VERSION 5.7 ;
  NOWIREEXTENSIONATPIN ON ;
  DIVIDERCHAR "/" ;
  BUSBITCHARS "[]" ;
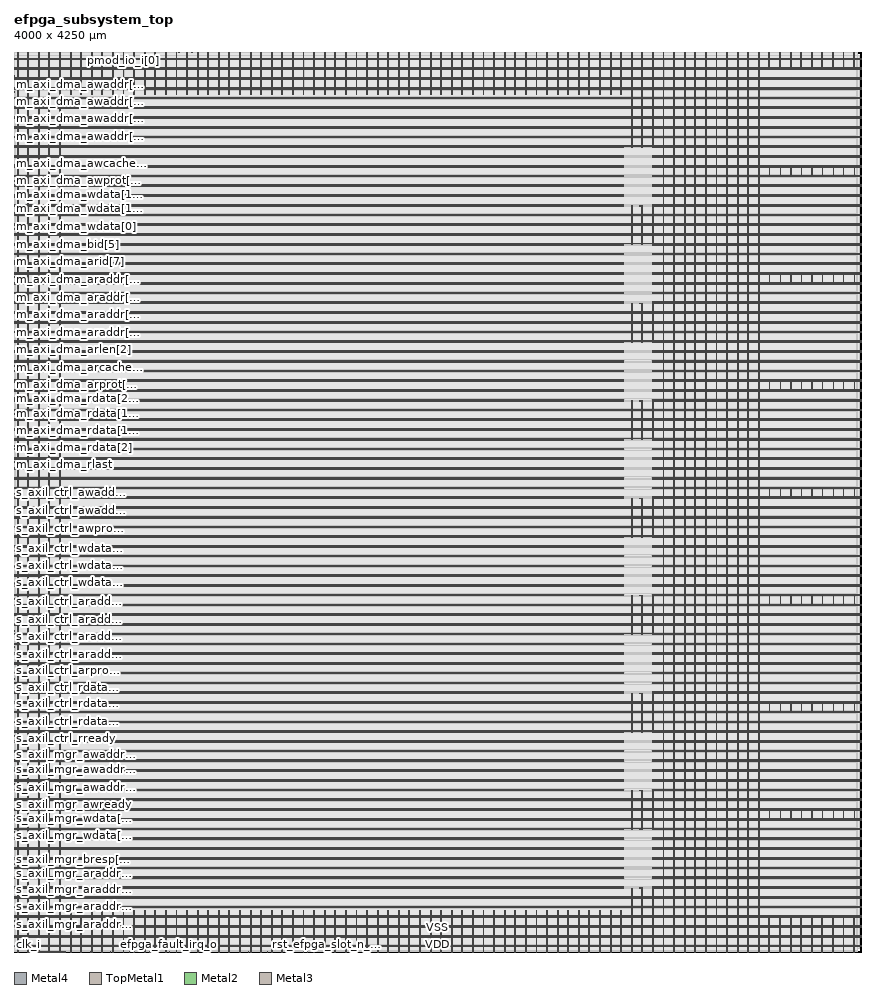
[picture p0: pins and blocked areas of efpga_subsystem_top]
MACRO efpga_subsystem_top
  CLASS BLOCK ;
  FOREIGN efpga_subsystem_top ;
  ORIGIN 0.000 0.000 ;
  SIZE 4000.000 BY 4250.000 ;
  PIN VDD
    DIRECTION INOUT ;
    USE POWER ;
    PORT
      LAYER Metal4 ;
        RECT 15.260 0.000 16.260 4250.000 ;
    END
    PORT
      LAYER Metal4 ;
        RECT 65.260 0.000 66.260 4250.000 ;
    END
    PORT
      LAYER Metal4 ;
        RECT 115.260 0.000 116.260 4250.000 ;
    END
    PORT
      LAYER Metal4 ;
        RECT 165.260 0.000 166.260 4250.000 ;
    END
    PORT
      LAYER Metal4 ;
        RECT 215.260 0.000 216.260 4250.000 ;
    END
    PORT
      LAYER Metal4 ;
        RECT 265.260 0.000 266.260 196.145 ;
    END
    PORT
      LAYER Metal4 ;
        RECT 265.260 4048.995 266.260 4250.000 ;
    END
    PORT
      LAYER Metal4 ;
        RECT 315.260 0.000 316.260 196.145 ;
    END
    PORT
      LAYER Metal4 ;
        RECT 315.260 4048.995 316.260 4250.000 ;
    END
    PORT
      LAYER Metal4 ;
        RECT 365.260 0.000 366.260 196.145 ;
    END
    PORT
      LAYER Metal4 ;
        RECT 365.260 4048.995 366.260 4250.000 ;
    END
    PORT
      LAYER Metal4 ;
        RECT 415.260 0.000 416.260 196.145 ;
    END
    PORT
      LAYER Metal4 ;
        RECT 415.260 4048.995 416.260 4250.000 ;
    END
    PORT
      LAYER Metal4 ;
        RECT 465.260 0.000 466.260 196.145 ;
    END
    PORT
      LAYER Metal4 ;
        RECT 465.260 4048.995 466.260 4250.000 ;
    END
    PORT
      LAYER Metal4 ;
        RECT 515.260 0.000 516.260 196.145 ;
    END
    PORT
      LAYER Metal4 ;
        RECT 515.260 4048.995 516.260 4250.000 ;
    END
    PORT
      LAYER Metal4 ;
        RECT 565.260 0.000 566.260 196.145 ;
    END
    PORT
      LAYER Metal4 ;
        RECT 565.260 4048.995 566.260 4250.000 ;
    END
    PORT
      LAYER Metal4 ;
        RECT 615.260 0.000 616.260 196.145 ;
    END
    PORT
      LAYER Metal4 ;
        RECT 615.260 4048.995 616.260 4250.000 ;
    END
    PORT
      LAYER Metal4 ;
        RECT 665.260 0.000 666.260 196.145 ;
    END
    PORT
      LAYER Metal4 ;
        RECT 665.260 4048.995 666.260 4250.000 ;
    END
    PORT
      LAYER Metal4 ;
        RECT 715.260 0.000 716.260 196.145 ;
    END
    PORT
      LAYER Metal4 ;
        RECT 715.260 4048.995 716.260 4250.000 ;
    END
    PORT
      LAYER Metal4 ;
        RECT 765.260 0.000 766.260 196.145 ;
    END
    PORT
      LAYER Metal4 ;
        RECT 765.260 4048.995 766.260 4250.000 ;
    END
    PORT
      LAYER Metal4 ;
        RECT 815.260 0.000 816.260 196.145 ;
    END
    PORT
      LAYER Metal4 ;
        RECT 815.260 4048.995 816.260 4250.000 ;
    END
    PORT
      LAYER Metal4 ;
        RECT 865.260 0.000 866.260 196.145 ;
    END
    PORT
      LAYER Metal4 ;
        RECT 865.260 4048.995 866.260 4250.000 ;
    END
    PORT
      LAYER Metal4 ;
        RECT 915.260 0.000 916.260 196.145 ;
    END
    PORT
      LAYER Metal4 ;
        RECT 915.260 4048.995 916.260 4250.000 ;
    END
    PORT
      LAYER Metal4 ;
        RECT 965.260 0.000 966.260 196.145 ;
    END
    PORT
      LAYER Metal4 ;
        RECT 965.260 4048.995 966.260 4250.000 ;
    END
    PORT
      LAYER Metal4 ;
        RECT 1015.260 0.000 1016.260 196.145 ;
    END
    PORT
      LAYER Metal4 ;
        RECT 1015.260 4048.995 1016.260 4250.000 ;
    END
    PORT
      LAYER Metal4 ;
        RECT 1065.260 0.000 1066.260 196.145 ;
    END
    PORT
      LAYER Metal4 ;
        RECT 1065.260 4048.995 1066.260 4250.000 ;
    END
    PORT
      LAYER Metal4 ;
        RECT 1115.260 0.000 1116.260 196.145 ;
    END
    PORT
      LAYER Metal4 ;
        RECT 1115.260 4048.995 1116.260 4250.000 ;
    END
    PORT
      LAYER Metal4 ;
        RECT 1165.260 0.000 1166.260 196.145 ;
    END
    PORT
      LAYER Metal4 ;
        RECT 1165.260 4048.995 1166.260 4250.000 ;
    END
    PORT
      LAYER Metal4 ;
        RECT 1215.260 0.000 1216.260 196.145 ;
    END
    PORT
      LAYER Metal4 ;
        RECT 1215.260 4048.995 1216.260 4250.000 ;
    END
    PORT
      LAYER Metal4 ;
        RECT 1265.260 0.000 1266.260 196.145 ;
    END
    PORT
      LAYER Metal4 ;
        RECT 1265.260 4048.995 1266.260 4250.000 ;
    END
    PORT
      LAYER Metal4 ;
        RECT 1315.260 0.000 1316.260 196.145 ;
    END
    PORT
      LAYER Metal4 ;
        RECT 1315.260 4048.995 1316.260 4250.000 ;
    END
    PORT
      LAYER Metal4 ;
        RECT 1365.260 0.000 1366.260 196.145 ;
    END
    PORT
      LAYER Metal4 ;
        RECT 1365.260 4048.995 1366.260 4250.000 ;
    END
    PORT
      LAYER Metal4 ;
        RECT 1415.260 0.000 1416.260 196.145 ;
    END
    PORT
      LAYER Metal4 ;
        RECT 1415.260 4048.995 1416.260 4250.000 ;
    END
    PORT
      LAYER Metal4 ;
        RECT 1465.260 0.000 1466.260 196.145 ;
    END
    PORT
      LAYER Metal4 ;
        RECT 1465.260 4048.995 1466.260 4250.000 ;
    END
    PORT
      LAYER Metal4 ;
        RECT 1515.260 0.000 1516.260 196.145 ;
    END
    PORT
      LAYER Metal4 ;
        RECT 1515.260 4048.995 1516.260 4250.000 ;
    END
    PORT
      LAYER Metal4 ;
        RECT 1565.260 0.000 1566.260 196.145 ;
    END
    PORT
      LAYER Metal4 ;
        RECT 1565.260 4048.995 1566.260 4250.000 ;
    END
    PORT
      LAYER Metal4 ;
        RECT 1615.260 0.000 1616.260 196.145 ;
    END
    PORT
      LAYER Metal4 ;
        RECT 1615.260 4048.995 1616.260 4250.000 ;
    END
    PORT
      LAYER Metal4 ;
        RECT 1665.260 0.000 1666.260 196.145 ;
    END
    PORT
      LAYER Metal4 ;
        RECT 1665.260 4048.995 1666.260 4250.000 ;
    END
    PORT
      LAYER Metal4 ;
        RECT 1715.260 0.000 1716.260 195.630 ;
    END
    PORT
      LAYER Metal4 ;
        RECT 1715.260 4049.510 1716.260 4250.000 ;
    END
    PORT
      LAYER Metal4 ;
        RECT 1765.260 0.000 1766.260 195.630 ;
    END
    PORT
      LAYER Metal4 ;
        RECT 1765.260 4049.510 1766.260 4250.000 ;
    END
    PORT
      LAYER Metal4 ;
        RECT 1815.260 0.000 1816.260 195.630 ;
    END
    PORT
      LAYER Metal4 ;
        RECT 1815.260 4049.510 1816.260 4250.000 ;
    END
    PORT
      LAYER Metal4 ;
        RECT 1865.260 0.000 1866.260 195.630 ;
    END
    PORT
      LAYER Metal4 ;
        RECT 1865.260 4049.510 1866.260 4250.000 ;
    END
    PORT
      LAYER Metal4 ;
        RECT 1915.260 0.000 1916.260 195.630 ;
    END
    PORT
      LAYER Metal4 ;
        RECT 1915.260 4049.510 1916.260 4250.000 ;
    END
    PORT
      LAYER Metal4 ;
        RECT 1965.260 0.000 1966.260 195.630 ;
    END
    PORT
      LAYER Metal4 ;
        RECT 1965.260 4049.510 1966.260 4250.000 ;
    END
    PORT
      LAYER Metal4 ;
        RECT 2015.260 0.000 2016.260 196.145 ;
    END
    PORT
      LAYER Metal4 ;
        RECT 2015.260 4048.995 2016.260 4250.000 ;
    END
    PORT
      LAYER Metal4 ;
        RECT 2065.260 0.000 2066.260 196.145 ;
    END
    PORT
      LAYER Metal4 ;
        RECT 2065.260 4048.995 2066.260 4250.000 ;
    END
    PORT
      LAYER Metal4 ;
        RECT 2115.260 0.000 2116.260 196.145 ;
    END
    PORT
      LAYER Metal4 ;
        RECT 2115.260 4048.995 2116.260 4250.000 ;
    END
    PORT
      LAYER Metal4 ;
        RECT 2165.260 0.000 2166.260 196.145 ;
    END
    PORT
      LAYER Metal4 ;
        RECT 2165.260 4048.995 2166.260 4250.000 ;
    END
    PORT
      LAYER Metal4 ;
        RECT 2215.260 0.000 2216.260 196.145 ;
    END
    PORT
      LAYER Metal4 ;
        RECT 2215.260 4048.995 2216.260 4250.000 ;
    END
    PORT
      LAYER Metal4 ;
        RECT 2265.260 0.000 2266.260 196.145 ;
    END
    PORT
      LAYER Metal4 ;
        RECT 2265.260 4048.995 2266.260 4250.000 ;
    END
    PORT
      LAYER Metal4 ;
        RECT 2315.260 0.000 2316.260 196.145 ;
    END
    PORT
      LAYER Metal4 ;
        RECT 2315.260 4048.995 2316.260 4250.000 ;
    END
    PORT
      LAYER Metal4 ;
        RECT 2365.260 0.000 2366.260 196.145 ;
    END
    PORT
      LAYER Metal4 ;
        RECT 2365.260 4048.995 2366.260 4250.000 ;
    END
    PORT
      LAYER Metal4 ;
        RECT 2415.260 0.000 2416.260 196.145 ;
    END
    PORT
      LAYER Metal4 ;
        RECT 2415.260 4048.995 2416.260 4250.000 ;
    END
    PORT
      LAYER Metal4 ;
        RECT 2465.260 0.000 2466.260 196.145 ;
    END
    PORT
      LAYER Metal4 ;
        RECT 2465.260 4048.995 2466.260 4250.000 ;
    END
    PORT
      LAYER Metal4 ;
        RECT 2515.260 0.000 2516.260 196.145 ;
    END
    PORT
      LAYER Metal4 ;
        RECT 2515.260 4048.995 2516.260 4250.000 ;
    END
    PORT
      LAYER Metal4 ;
        RECT 2565.260 0.000 2566.260 196.145 ;
    END
    PORT
      LAYER Metal4 ;
        RECT 2565.260 4048.995 2566.260 4250.000 ;
    END
    PORT
      LAYER Metal4 ;
        RECT 2615.260 0.000 2616.260 196.145 ;
    END
    PORT
      LAYER Metal4 ;
        RECT 2615.260 4048.995 2616.260 4250.000 ;
    END
    PORT
      LAYER Metal4 ;
        RECT 2665.260 0.000 2666.260 196.145 ;
    END
    PORT
      LAYER Metal4 ;
        RECT 2665.260 4048.995 2666.260 4250.000 ;
    END
    PORT
      LAYER Metal4 ;
        RECT 2715.260 0.000 2716.260 196.145 ;
    END
    PORT
      LAYER Metal4 ;
        RECT 2715.260 4048.995 2716.260 4250.000 ;
    END
    PORT
      LAYER Metal4 ;
        RECT 2765.260 0.000 2766.260 196.145 ;
    END
    PORT
      LAYER Metal4 ;
        RECT 2765.260 4048.995 2766.260 4250.000 ;
    END
    PORT
      LAYER Metal4 ;
        RECT 2815.260 0.000 2816.260 196.145 ;
    END
    PORT
      LAYER Metal4 ;
        RECT 2815.260 4048.995 2816.260 4250.000 ;
    END
    PORT
      LAYER Metal4 ;
        RECT 2865.260 0.000 2866.260 196.145 ;
    END
    PORT
      LAYER Metal4 ;
        RECT 2865.260 4048.995 2866.260 4250.000 ;
    END
    PORT
      LAYER Metal4 ;
        RECT 2915.260 0.000 2916.260 301.730 ;
    END
    PORT
      LAYER Metal4 ;
        RECT 2915.260 577.210 2916.260 762.050 ;
    END
    PORT
      LAYER Metal4 ;
        RECT 2915.260 1037.530 2916.260 1222.370 ;
    END
    PORT
      LAYER Metal4 ;
        RECT 2915.260 1497.850 2916.260 1682.690 ;
    END
    PORT
      LAYER Metal4 ;
        RECT 2915.260 1958.170 2916.260 2143.010 ;
    END
    PORT
      LAYER Metal4 ;
        RECT 2915.260 2418.490 2916.260 2603.330 ;
    END
    PORT
      LAYER Metal4 ;
        RECT 2915.260 2878.810 2916.260 3063.650 ;
    END
    PORT
      LAYER Metal4 ;
        RECT 2915.260 3339.130 2916.260 3523.970 ;
    END
    PORT
      LAYER Metal4 ;
        RECT 2915.260 3799.450 2916.260 4250.000 ;
    END
    PORT
      LAYER Metal4 ;
        RECT 2965.260 0.000 2966.260 301.730 ;
    END
    PORT
      LAYER Metal4 ;
        RECT 2965.260 577.210 2966.260 762.050 ;
    END
    PORT
      LAYER Metal4 ;
        RECT 2965.260 1037.530 2966.260 1222.370 ;
    END
    PORT
      LAYER Metal4 ;
        RECT 2965.260 1497.850 2966.260 1682.690 ;
    END
    PORT
      LAYER Metal4 ;
        RECT 2965.260 1958.170 2966.260 2143.010 ;
    END
    PORT
      LAYER Metal4 ;
        RECT 2965.260 2418.490 2966.260 2603.330 ;
    END
    PORT
      LAYER Metal4 ;
        RECT 2965.260 2878.810 2966.260 3063.650 ;
    END
    PORT
      LAYER Metal4 ;
        RECT 2965.260 3339.130 2966.260 3523.970 ;
    END
    PORT
      LAYER Metal4 ;
        RECT 2965.260 3799.450 2966.260 4250.000 ;
    END
    PORT
      LAYER Metal4 ;
        RECT 3015.260 0.000 3016.260 301.730 ;
    END
    PORT
      LAYER Metal4 ;
        RECT 3015.260 577.210 3016.260 762.050 ;
    END
    PORT
      LAYER Metal4 ;
        RECT 3015.260 1037.530 3016.260 1222.370 ;
    END
    PORT
      LAYER Metal4 ;
        RECT 3015.260 1497.850 3016.260 1682.690 ;
    END
    PORT
      LAYER Metal4 ;
        RECT 3015.260 1958.170 3016.260 2143.010 ;
    END
    PORT
      LAYER Metal4 ;
        RECT 3015.260 2418.490 3016.260 2603.330 ;
    END
    PORT
      LAYER Metal4 ;
        RECT 3015.260 2878.810 3016.260 3063.650 ;
    END
    PORT
      LAYER Metal4 ;
        RECT 3015.260 3339.130 3016.260 3523.970 ;
    END
    PORT
      LAYER Metal4 ;
        RECT 3015.260 3799.450 3016.260 4250.000 ;
    END
    PORT
      LAYER Metal4 ;
        RECT 3065.260 0.000 3066.260 4250.000 ;
    END
    PORT
      LAYER Metal4 ;
        RECT 3115.260 0.000 3116.260 4250.000 ;
    END
    PORT
      LAYER Metal4 ;
        RECT 3165.260 0.000 3166.260 4250.000 ;
    END
    PORT
      LAYER Metal4 ;
        RECT 3215.260 0.000 3216.260 4250.000 ;
    END
    PORT
      LAYER Metal4 ;
        RECT 3265.260 0.000 3266.260 4250.000 ;
    END
    PORT
      LAYER Metal4 ;
        RECT 3315.260 0.000 3316.260 4250.000 ;
    END
    PORT
      LAYER Metal4 ;
        RECT 3365.260 0.000 3366.260 4250.000 ;
    END
    PORT
      LAYER Metal4 ;
        RECT 3415.260 0.000 3416.260 4250.000 ;
    END
    PORT
      LAYER Metal4 ;
        RECT 3465.260 0.000 3466.260 4250.000 ;
    END
    PORT
      LAYER Metal4 ;
        RECT 3515.260 0.000 3516.260 4250.000 ;
    END
    PORT
      LAYER Metal4 ;
        RECT 3565.260 0.000 3566.260 160.655 ;
    END
    PORT
      LAYER Metal4 ;
        RECT 3565.260 4170.510 3566.260 4250.000 ;
    END
    PORT
      LAYER Metal4 ;
        RECT 3615.260 0.000 3616.260 160.655 ;
    END
    PORT
      LAYER Metal4 ;
        RECT 3615.260 4170.510 3616.260 4250.000 ;
    END
    PORT
      LAYER Metal4 ;
        RECT 3665.260 0.000 3666.260 160.655 ;
    END
    PORT
      LAYER Metal4 ;
        RECT 3665.260 4170.510 3666.260 4250.000 ;
    END
    PORT
      LAYER Metal4 ;
        RECT 3715.260 0.000 3716.260 160.655 ;
    END
    PORT
      LAYER Metal4 ;
        RECT 3715.260 4170.510 3716.260 4250.000 ;
    END
    PORT
      LAYER Metal4 ;
        RECT 3765.260 0.000 3766.260 160.655 ;
    END
    PORT
      LAYER Metal4 ;
        RECT 3765.260 4170.510 3766.260 4250.000 ;
    END
    PORT
      LAYER Metal4 ;
        RECT 3815.260 0.000 3816.260 160.655 ;
    END
    PORT
      LAYER Metal4 ;
        RECT 3815.260 4170.510 3816.260 4250.000 ;
    END
    PORT
      LAYER Metal4 ;
        RECT 3865.260 0.000 3866.260 160.655 ;
    END
    PORT
      LAYER Metal4 ;
        RECT 3865.260 4170.510 3866.260 4250.000 ;
    END
    PORT
      LAYER Metal4 ;
        RECT 3915.260 0.000 3916.260 160.655 ;
    END
    PORT
      LAYER Metal4 ;
        RECT 3915.260 4170.510 3916.260 4250.000 ;
    END
    PORT
      LAYER Metal4 ;
        RECT 3965.260 0.000 3966.260 160.655 ;
    END
    PORT
      LAYER Metal4 ;
        RECT 3965.260 4170.510 3966.260 4250.000 ;
    END
    PORT
      LAYER TopMetal1 ;
        RECT 0.000 24.120 4000.000 26.120 ;
    END
    PORT
      LAYER TopMetal1 ;
        RECT 0.000 70.150 4000.000 72.150 ;
    END
    PORT
      LAYER TopMetal1 ;
        RECT 0.000 116.180 4000.000 118.180 ;
    END
    PORT
      LAYER TopMetal1 ;
        RECT 0.000 162.210 4000.000 164.210 ;
    END
    PORT
      LAYER TopMetal1 ;
        RECT 0.000 208.240 4000.000 210.240 ;
    END
    PORT
      LAYER TopMetal1 ;
        RECT 0.000 254.270 4000.000 256.270 ;
    END
    PORT
      LAYER TopMetal1 ;
        RECT 0.000 300.300 2879.840 302.300 ;
    END
    PORT
      LAYER TopMetal1 ;
        RECT 0.000 346.330 2879.840 348.330 ;
    END
    PORT
      LAYER TopMetal1 ;
        RECT 0.000 392.360 2879.840 394.360 ;
    END
    PORT
      LAYER TopMetal1 ;
        RECT 0.000 438.390 2879.840 440.390 ;
    END
    PORT
      LAYER TopMetal1 ;
        RECT 0.000 484.420 2879.840 486.420 ;
    END
    PORT
      LAYER TopMetal1 ;
        RECT 0.000 530.450 2879.840 532.450 ;
    END
    PORT
      LAYER TopMetal1 ;
        RECT 0.000 576.480 2879.840 578.480 ;
    END
    PORT
      LAYER TopMetal1 ;
        RECT 0.000 622.510 4000.000 624.510 ;
    END
    PORT
      LAYER TopMetal1 ;
        RECT 0.000 668.540 4000.000 670.540 ;
    END
    PORT
      LAYER TopMetal1 ;
        RECT 0.000 714.570 4000.000 716.570 ;
    END
    PORT
      LAYER TopMetal1 ;
        RECT 0.000 760.600 2879.840 762.600 ;
    END
    PORT
      LAYER TopMetal1 ;
        RECT 0.000 806.630 2879.840 808.630 ;
    END
    PORT
      LAYER TopMetal1 ;
        RECT 0.000 852.660 2879.840 854.660 ;
    END
    PORT
      LAYER TopMetal1 ;
        RECT 0.000 898.690 2879.840 900.690 ;
    END
    PORT
      LAYER TopMetal1 ;
        RECT 0.000 944.720 2879.840 946.720 ;
    END
    PORT
      LAYER TopMetal1 ;
        RECT 0.000 990.750 2879.840 992.750 ;
    END
    PORT
      LAYER TopMetal1 ;
        RECT 0.000 1036.780 2879.840 1038.780 ;
    END
    PORT
      LAYER TopMetal1 ;
        RECT 0.000 1082.810 4000.000 1084.810 ;
    END
    PORT
      LAYER TopMetal1 ;
        RECT 0.000 1128.840 4000.000 1130.840 ;
    END
    PORT
      LAYER TopMetal1 ;
        RECT 0.000 1174.870 4000.000 1176.870 ;
    END
    PORT
      LAYER TopMetal1 ;
        RECT 0.000 1220.900 2879.840 1222.900 ;
    END
    PORT
      LAYER TopMetal1 ;
        RECT 0.000 1266.930 2879.840 1268.930 ;
    END
    PORT
      LAYER TopMetal1 ;
        RECT 0.000 1312.960 2879.840 1314.960 ;
    END
    PORT
      LAYER TopMetal1 ;
        RECT 0.000 1358.990 2879.840 1360.990 ;
    END
    PORT
      LAYER TopMetal1 ;
        RECT 0.000 1405.020 2879.840 1407.020 ;
    END
    PORT
      LAYER TopMetal1 ;
        RECT 0.000 1451.050 2879.840 1453.050 ;
    END
    PORT
      LAYER TopMetal1 ;
        RECT 0.000 1497.080 2879.840 1499.080 ;
    END
    PORT
      LAYER TopMetal1 ;
        RECT 0.000 1543.110 4000.000 1545.110 ;
    END
    PORT
      LAYER TopMetal1 ;
        RECT 0.000 1589.140 4000.000 1591.140 ;
    END
    PORT
      LAYER TopMetal1 ;
        RECT 0.000 1635.170 4000.000 1637.170 ;
    END
    PORT
      LAYER TopMetal1 ;
        RECT 0.000 1681.200 2879.840 1683.200 ;
    END
    PORT
      LAYER TopMetal1 ;
        RECT 0.000 1727.230 2879.840 1729.230 ;
    END
    PORT
      LAYER TopMetal1 ;
        RECT 0.000 1773.260 2879.840 1775.260 ;
    END
    PORT
      LAYER TopMetal1 ;
        RECT 0.000 1819.290 2879.840 1821.290 ;
    END
    PORT
      LAYER TopMetal1 ;
        RECT 0.000 1865.320 2879.840 1867.320 ;
    END
    PORT
      LAYER TopMetal1 ;
        RECT 0.000 1911.350 2879.840 1913.350 ;
    END
    PORT
      LAYER TopMetal1 ;
        RECT 0.000 1957.380 2879.840 1959.380 ;
    END
    PORT
      LAYER TopMetal1 ;
        RECT 0.000 2003.410 4000.000 2005.410 ;
    END
    PORT
      LAYER TopMetal1 ;
        RECT 0.000 2049.440 4000.000 2051.440 ;
    END
    PORT
      LAYER TopMetal1 ;
        RECT 0.000 2095.470 4000.000 2097.470 ;
    END
    PORT
      LAYER TopMetal1 ;
        RECT 0.000 2141.500 2879.840 2143.500 ;
    END
    PORT
      LAYER TopMetal1 ;
        RECT 0.000 2187.530 2879.840 2189.530 ;
    END
    PORT
      LAYER TopMetal1 ;
        RECT 0.000 2233.560 2879.840 2235.560 ;
    END
    PORT
      LAYER TopMetal1 ;
        RECT 0.000 2279.590 2879.840 2281.590 ;
    END
    PORT
      LAYER TopMetal1 ;
        RECT 0.000 2325.620 2879.840 2327.620 ;
    END
    PORT
      LAYER TopMetal1 ;
        RECT 0.000 2371.650 2879.840 2373.650 ;
    END
    PORT
      LAYER TopMetal1 ;
        RECT 0.000 2417.680 2879.840 2419.680 ;
    END
    PORT
      LAYER TopMetal1 ;
        RECT 0.000 2463.710 4000.000 2465.710 ;
    END
    PORT
      LAYER TopMetal1 ;
        RECT 0.000 2509.740 4000.000 2511.740 ;
    END
    PORT
      LAYER TopMetal1 ;
        RECT 0.000 2555.770 4000.000 2557.770 ;
    END
    PORT
      LAYER TopMetal1 ;
        RECT 0.000 2601.800 2879.840 2603.800 ;
    END
    PORT
      LAYER TopMetal1 ;
        RECT 0.000 2647.830 2879.840 2649.830 ;
    END
    PORT
      LAYER TopMetal1 ;
        RECT 0.000 2693.860 2879.840 2695.860 ;
    END
    PORT
      LAYER TopMetal1 ;
        RECT 0.000 2739.890 2879.840 2741.890 ;
    END
    PORT
      LAYER TopMetal1 ;
        RECT 0.000 2785.920 2879.840 2787.920 ;
    END
    PORT
      LAYER TopMetal1 ;
        RECT 0.000 2831.950 2879.840 2833.950 ;
    END
    PORT
      LAYER TopMetal1 ;
        RECT 0.000 2877.980 2879.840 2879.980 ;
    END
    PORT
      LAYER TopMetal1 ;
        RECT 0.000 2924.010 4000.000 2926.010 ;
    END
    PORT
      LAYER TopMetal1 ;
        RECT 0.000 2970.040 4000.000 2972.040 ;
    END
    PORT
      LAYER TopMetal1 ;
        RECT 0.000 3016.070 4000.000 3018.070 ;
    END
    PORT
      LAYER TopMetal1 ;
        RECT 0.000 3062.100 2879.840 3064.100 ;
    END
    PORT
      LAYER TopMetal1 ;
        RECT 0.000 3108.130 2879.840 3110.130 ;
    END
    PORT
      LAYER TopMetal1 ;
        RECT 0.000 3154.160 2879.840 3156.160 ;
    END
    PORT
      LAYER TopMetal1 ;
        RECT 0.000 3200.190 2879.840 3202.190 ;
    END
    PORT
      LAYER TopMetal1 ;
        RECT 0.000 3246.220 2879.840 3248.220 ;
    END
    PORT
      LAYER TopMetal1 ;
        RECT 0.000 3292.250 2879.840 3294.250 ;
    END
    PORT
      LAYER TopMetal1 ;
        RECT 0.000 3338.280 2879.840 3340.280 ;
    END
    PORT
      LAYER TopMetal1 ;
        RECT 0.000 3384.310 4000.000 3386.310 ;
    END
    PORT
      LAYER TopMetal1 ;
        RECT 0.000 3430.340 4000.000 3432.340 ;
    END
    PORT
      LAYER TopMetal1 ;
        RECT 0.000 3476.370 4000.000 3478.370 ;
    END
    PORT
      LAYER TopMetal1 ;
        RECT 0.000 3522.400 2879.840 3524.400 ;
    END
    PORT
      LAYER TopMetal1 ;
        RECT 0.000 3568.430 2879.840 3570.430 ;
    END
    PORT
      LAYER TopMetal1 ;
        RECT 0.000 3614.460 2879.840 3616.460 ;
    END
    PORT
      LAYER TopMetal1 ;
        RECT 0.000 3660.490 2879.840 3662.490 ;
    END
    PORT
      LAYER TopMetal1 ;
        RECT 0.000 3706.520 2879.840 3708.520 ;
    END
    PORT
      LAYER TopMetal1 ;
        RECT 0.000 3752.550 2879.840 3754.550 ;
    END
    PORT
      LAYER TopMetal1 ;
        RECT 0.000 3798.580 2879.840 3800.580 ;
    END
    PORT
      LAYER TopMetal1 ;
        RECT 0.000 3844.610 4000.000 3846.610 ;
    END
    PORT
      LAYER TopMetal1 ;
        RECT 0.000 3890.640 4000.000 3892.640 ;
    END
    PORT
      LAYER TopMetal1 ;
        RECT 0.000 3936.670 4000.000 3938.670 ;
    END
    PORT
      LAYER TopMetal1 ;
        RECT 0.000 3982.700 4000.000 3984.700 ;
    END
    PORT
      LAYER TopMetal1 ;
        RECT 0.000 4028.730 4000.000 4030.730 ;
    END
    PORT
      LAYER TopMetal1 ;
        RECT 0.000 4074.760 4000.000 4076.760 ;
    END
    PORT
      LAYER TopMetal1 ;
        RECT 0.000 4120.790 4000.000 4122.790 ;
    END
    PORT
      LAYER TopMetal1 ;
        RECT 0.000 4166.820 4000.000 4168.820 ;
    END
    PORT
      LAYER TopMetal1 ;
        RECT 0.000 4212.850 4000.000 4214.850 ;
    END
    PORT
      LAYER TopMetal1 ;
        RECT 2954.400 300.300 2969.840 302.300 ;
    END
    PORT
      LAYER TopMetal1 ;
        RECT 2954.400 576.480 2969.840 578.480 ;
    END
    PORT
      LAYER TopMetal1 ;
        RECT 2954.400 760.600 2969.840 762.600 ;
    END
    PORT
      LAYER TopMetal1 ;
        RECT 2954.400 1220.900 2969.840 1222.900 ;
    END
    PORT
      LAYER TopMetal1 ;
        RECT 2954.400 1681.200 2969.840 1683.200 ;
    END
    PORT
      LAYER TopMetal1 ;
        RECT 2954.400 2141.500 2969.840 2143.500 ;
    END
    PORT
      LAYER TopMetal1 ;
        RECT 2954.400 2601.800 2969.840 2603.800 ;
    END
    PORT
      LAYER TopMetal1 ;
        RECT 2954.400 3062.100 2969.840 3064.100 ;
    END
    PORT
      LAYER TopMetal1 ;
        RECT 2954.400 3522.400 2969.840 3524.400 ;
    END
    PORT
      LAYER TopMetal1 ;
        RECT 3014.400 300.300 4000.000 302.300 ;
    END
    PORT
      LAYER TopMetal1 ;
        RECT 3014.400 346.330 4000.000 348.330 ;
    END
    PORT
      LAYER TopMetal1 ;
        RECT 3014.400 392.360 4000.000 394.360 ;
    END
    PORT
      LAYER TopMetal1 ;
        RECT 3014.400 438.390 4000.000 440.390 ;
    END
    PORT
      LAYER TopMetal1 ;
        RECT 3014.400 484.420 4000.000 486.420 ;
    END
    PORT
      LAYER TopMetal1 ;
        RECT 3014.400 530.450 4000.000 532.450 ;
    END
    PORT
      LAYER TopMetal1 ;
        RECT 3014.400 576.480 4000.000 578.480 ;
    END
    PORT
      LAYER TopMetal1 ;
        RECT 3014.400 760.600 4000.000 762.600 ;
    END
    PORT
      LAYER TopMetal1 ;
        RECT 3014.400 806.630 4000.000 808.630 ;
    END
    PORT
      LAYER TopMetal1 ;
        RECT 3014.400 852.660 4000.000 854.660 ;
    END
    PORT
      LAYER TopMetal1 ;
        RECT 3014.400 898.690 4000.000 900.690 ;
    END
    PORT
      LAYER TopMetal1 ;
        RECT 3014.400 944.720 4000.000 946.720 ;
    END
    PORT
      LAYER TopMetal1 ;
        RECT 3014.400 990.750 4000.000 992.750 ;
    END
    PORT
      LAYER TopMetal1 ;
        RECT 3014.400 1036.780 4000.000 1038.780 ;
    END
    PORT
      LAYER TopMetal1 ;
        RECT 3014.400 1220.900 4000.000 1222.900 ;
    END
    PORT
      LAYER TopMetal1 ;
        RECT 3014.400 1266.930 4000.000 1268.930 ;
    END
    PORT
      LAYER TopMetal1 ;
        RECT 3014.400 1312.960 4000.000 1314.960 ;
    END
    PORT
      LAYER TopMetal1 ;
        RECT 3014.400 1358.990 4000.000 1360.990 ;
    END
    PORT
      LAYER TopMetal1 ;
        RECT 3014.400 1405.020 4000.000 1407.020 ;
    END
    PORT
      LAYER TopMetal1 ;
        RECT 3014.400 1451.050 4000.000 1453.050 ;
    END
    PORT
      LAYER TopMetal1 ;
        RECT 3014.400 1497.080 4000.000 1499.080 ;
    END
    PORT
      LAYER TopMetal1 ;
        RECT 3014.400 1681.200 4000.000 1683.200 ;
    END
    PORT
      LAYER TopMetal1 ;
        RECT 3014.400 1727.230 4000.000 1729.230 ;
    END
    PORT
      LAYER TopMetal1 ;
        RECT 3014.400 1773.260 4000.000 1775.260 ;
    END
    PORT
      LAYER TopMetal1 ;
        RECT 3014.400 1819.290 4000.000 1821.290 ;
    END
    PORT
      LAYER TopMetal1 ;
        RECT 3014.400 1865.320 4000.000 1867.320 ;
    END
    PORT
      LAYER TopMetal1 ;
        RECT 3014.400 1911.350 4000.000 1913.350 ;
    END
    PORT
      LAYER TopMetal1 ;
        RECT 3014.400 1957.380 4000.000 1959.380 ;
    END
    PORT
      LAYER TopMetal1 ;
        RECT 3014.400 2141.500 4000.000 2143.500 ;
    END
    PORT
      LAYER TopMetal1 ;
        RECT 3014.400 2187.530 4000.000 2189.530 ;
    END
    PORT
      LAYER TopMetal1 ;
        RECT 3014.400 2233.560 4000.000 2235.560 ;
    END
    PORT
      LAYER TopMetal1 ;
        RECT 3014.400 2279.590 4000.000 2281.590 ;
    END
    PORT
      LAYER TopMetal1 ;
        RECT 3014.400 2325.620 4000.000 2327.620 ;
    END
    PORT
      LAYER TopMetal1 ;
        RECT 3014.400 2371.650 4000.000 2373.650 ;
    END
    PORT
      LAYER TopMetal1 ;
        RECT 3014.400 2417.680 4000.000 2419.680 ;
    END
    PORT
      LAYER TopMetal1 ;
        RECT 3014.400 2601.800 4000.000 2603.800 ;
    END
    PORT
      LAYER TopMetal1 ;
        RECT 3014.400 2647.830 4000.000 2649.830 ;
    END
    PORT
      LAYER TopMetal1 ;
        RECT 3014.400 2693.860 4000.000 2695.860 ;
    END
    PORT
      LAYER TopMetal1 ;
        RECT 3014.400 2739.890 4000.000 2741.890 ;
    END
    PORT
      LAYER TopMetal1 ;
        RECT 3014.400 2785.920 4000.000 2787.920 ;
    END
    PORT
      LAYER TopMetal1 ;
        RECT 3014.400 2831.950 4000.000 2833.950 ;
    END
    PORT
      LAYER TopMetal1 ;
        RECT 3014.400 2877.980 4000.000 2879.980 ;
    END
    PORT
      LAYER TopMetal1 ;
        RECT 3014.400 3062.100 4000.000 3064.100 ;
    END
    PORT
      LAYER TopMetal1 ;
        RECT 3014.400 3108.130 4000.000 3110.130 ;
    END
    PORT
      LAYER TopMetal1 ;
        RECT 3014.400 3154.160 4000.000 3156.160 ;
    END
    PORT
      LAYER TopMetal1 ;
        RECT 3014.400 3200.190 4000.000 3202.190 ;
    END
    PORT
      LAYER TopMetal1 ;
        RECT 3014.400 3246.220 4000.000 3248.220 ;
    END
    PORT
      LAYER TopMetal1 ;
        RECT 3014.400 3292.250 4000.000 3294.250 ;
    END
    PORT
      LAYER TopMetal1 ;
        RECT 3014.400 3338.280 4000.000 3340.280 ;
    END
    PORT
      LAYER TopMetal1 ;
        RECT 3014.400 3522.400 4000.000 3524.400 ;
    END
    PORT
      LAYER TopMetal1 ;
        RECT 3014.400 3568.430 4000.000 3570.430 ;
    END
    PORT
      LAYER TopMetal1 ;
        RECT 3014.400 3614.460 4000.000 3616.460 ;
    END
    PORT
      LAYER TopMetal1 ;
        RECT 3014.400 3660.490 4000.000 3662.490 ;
    END
    PORT
      LAYER TopMetal1 ;
        RECT 3014.400 3706.520 4000.000 3708.520 ;
    END
    PORT
      LAYER TopMetal1 ;
        RECT 3014.400 3752.550 4000.000 3754.550 ;
    END
    PORT
      LAYER TopMetal1 ;
        RECT 3014.400 3798.580 4000.000 3800.580 ;
    END
  END VDD
  PIN VSS
    DIRECTION INOUT ;
    USE GROUND ;
    PORT
      LAYER Metal4 ;
        RECT 18.260 0.000 19.260 4250.000 ;
    END
    PORT
      LAYER Metal4 ;
        RECT 68.260 0.000 69.260 4250.000 ;
    END
    PORT
      LAYER Metal4 ;
        RECT 118.260 0.000 119.260 4250.000 ;
    END
    PORT
      LAYER Metal4 ;
        RECT 168.260 0.000 169.260 4250.000 ;
    END
    PORT
      LAYER Metal4 ;
        RECT 218.260 0.000 219.260 4250.000 ;
    END
    PORT
      LAYER Metal4 ;
        RECT 268.260 0.000 269.260 196.145 ;
    END
    PORT
      LAYER Metal4 ;
        RECT 268.260 4048.995 269.260 4250.000 ;
    END
    PORT
      LAYER Metal4 ;
        RECT 318.260 0.000 319.260 196.145 ;
    END
    PORT
      LAYER Metal4 ;
        RECT 318.260 4048.995 319.260 4250.000 ;
    END
    PORT
      LAYER Metal4 ;
        RECT 368.260 0.000 369.260 196.145 ;
    END
    PORT
      LAYER Metal4 ;
        RECT 368.260 4048.995 369.260 4250.000 ;
    END
    PORT
      LAYER Metal4 ;
        RECT 418.260 0.000 419.260 196.145 ;
    END
    PORT
      LAYER Metal4 ;
        RECT 418.260 4048.995 419.260 4250.000 ;
    END
    PORT
      LAYER Metal4 ;
        RECT 468.260 0.000 469.260 196.145 ;
    END
    PORT
      LAYER Metal4 ;
        RECT 468.260 4048.995 469.260 4250.000 ;
    END
    PORT
      LAYER Metal4 ;
        RECT 518.260 0.000 519.260 196.145 ;
    END
    PORT
      LAYER Metal4 ;
        RECT 518.260 4048.995 519.260 4250.000 ;
    END
    PORT
      LAYER Metal4 ;
        RECT 568.260 0.000 569.260 196.145 ;
    END
    PORT
      LAYER Metal4 ;
        RECT 568.260 4048.995 569.260 4250.000 ;
    END
    PORT
      LAYER Metal4 ;
        RECT 618.260 0.000 619.260 196.145 ;
    END
    PORT
      LAYER Metal4 ;
        RECT 618.260 4048.995 619.260 4250.000 ;
    END
    PORT
      LAYER Metal4 ;
        RECT 668.260 0.000 669.260 196.145 ;
    END
    PORT
      LAYER Metal4 ;
        RECT 668.260 4048.995 669.260 4250.000 ;
    END
    PORT
      LAYER Metal4 ;
        RECT 718.260 0.000 719.260 196.145 ;
    END
    PORT
      LAYER Metal4 ;
        RECT 718.260 4048.995 719.260 4250.000 ;
    END
    PORT
      LAYER Metal4 ;
        RECT 768.260 0.000 769.260 196.145 ;
    END
    PORT
      LAYER Metal4 ;
        RECT 768.260 4048.995 769.260 4250.000 ;
    END
    PORT
      LAYER Metal4 ;
        RECT 818.260 0.000 819.260 196.145 ;
    END
    PORT
      LAYER Metal4 ;
        RECT 818.260 4048.995 819.260 4250.000 ;
    END
    PORT
      LAYER Metal4 ;
        RECT 868.260 0.000 869.260 196.145 ;
    END
    PORT
      LAYER Metal4 ;
        RECT 868.260 4048.995 869.260 4250.000 ;
    END
    PORT
      LAYER Metal4 ;
        RECT 918.260 0.000 919.260 196.145 ;
    END
    PORT
      LAYER Metal4 ;
        RECT 918.260 4048.995 919.260 4250.000 ;
    END
    PORT
      LAYER Metal4 ;
        RECT 968.260 0.000 969.260 196.145 ;
    END
    PORT
      LAYER Metal4 ;
        RECT 968.260 4048.995 969.260 4250.000 ;
    END
    PORT
      LAYER Metal4 ;
        RECT 1018.260 0.000 1019.260 196.145 ;
    END
    PORT
      LAYER Metal4 ;
        RECT 1018.260 4048.995 1019.260 4250.000 ;
    END
    PORT
      LAYER Metal4 ;
        RECT 1068.260 0.000 1069.260 196.145 ;
    END
    PORT
      LAYER Metal4 ;
        RECT 1068.260 4048.995 1069.260 4250.000 ;
    END
    PORT
      LAYER Metal4 ;
        RECT 1118.260 0.000 1119.260 196.145 ;
    END
    PORT
      LAYER Metal4 ;
        RECT 1118.260 4048.995 1119.260 4250.000 ;
    END
    PORT
      LAYER Metal4 ;
        RECT 1168.260 0.000 1169.260 196.145 ;
    END
    PORT
      LAYER Metal4 ;
        RECT 1168.260 4048.995 1169.260 4250.000 ;
    END
    PORT
      LAYER Metal4 ;
        RECT 1218.260 0.000 1219.260 196.145 ;
    END
    PORT
      LAYER Metal4 ;
        RECT 1218.260 4048.995 1219.260 4250.000 ;
    END
    PORT
      LAYER Metal4 ;
        RECT 1268.260 0.000 1269.260 196.145 ;
    END
    PORT
      LAYER Metal4 ;
        RECT 1268.260 4048.995 1269.260 4250.000 ;
    END
    PORT
      LAYER Metal4 ;
        RECT 1318.260 0.000 1319.260 196.145 ;
    END
    PORT
      LAYER Metal4 ;
        RECT 1318.260 4048.995 1319.260 4250.000 ;
    END
    PORT
      LAYER Metal4 ;
        RECT 1368.260 0.000 1369.260 196.145 ;
    END
    PORT
      LAYER Metal4 ;
        RECT 1368.260 4048.995 1369.260 4250.000 ;
    END
    PORT
      LAYER Metal4 ;
        RECT 1418.260 0.000 1419.260 196.145 ;
    END
    PORT
      LAYER Metal4 ;
        RECT 1418.260 4048.995 1419.260 4250.000 ;
    END
    PORT
      LAYER Metal4 ;
        RECT 1468.260 0.000 1469.260 196.145 ;
    END
    PORT
      LAYER Metal4 ;
        RECT 1468.260 4048.995 1469.260 4250.000 ;
    END
    PORT
      LAYER Metal4 ;
        RECT 1518.260 0.000 1519.260 196.145 ;
    END
    PORT
      LAYER Metal4 ;
        RECT 1518.260 4048.995 1519.260 4250.000 ;
    END
    PORT
      LAYER Metal4 ;
        RECT 1568.260 0.000 1569.260 196.145 ;
    END
    PORT
      LAYER Metal4 ;
        RECT 1568.260 4048.995 1569.260 4250.000 ;
    END
    PORT
      LAYER Metal4 ;
        RECT 1618.260 0.000 1619.260 196.145 ;
    END
    PORT
      LAYER Metal4 ;
        RECT 1618.260 4048.995 1619.260 4250.000 ;
    END
    PORT
      LAYER Metal4 ;
        RECT 1668.260 0.000 1669.260 196.145 ;
    END
    PORT
      LAYER Metal4 ;
        RECT 1668.260 4048.995 1669.260 4250.000 ;
    END
    PORT
      LAYER Metal4 ;
        RECT 1718.260 0.000 1719.260 196.145 ;
    END
    PORT
      LAYER Metal4 ;
        RECT 1718.260 4048.995 1719.260 4250.000 ;
    END
    PORT
      LAYER Metal4 ;
        RECT 1768.260 0.000 1769.260 196.145 ;
    END
    PORT
      LAYER Metal4 ;
        RECT 1768.260 4048.995 1769.260 4250.000 ;
    END
    PORT
      LAYER Metal4 ;
        RECT 1818.260 0.000 1819.260 196.145 ;
    END
    PORT
      LAYER Metal4 ;
        RECT 1818.260 4048.995 1819.260 4250.000 ;
    END
    PORT
      LAYER Metal4 ;
        RECT 1868.260 0.000 1869.260 196.145 ;
    END
    PORT
      LAYER Metal4 ;
        RECT 1868.260 4048.995 1869.260 4250.000 ;
    END
    PORT
      LAYER Metal4 ;
        RECT 1918.260 0.000 1919.260 196.145 ;
    END
    PORT
      LAYER Metal4 ;
        RECT 1918.260 4048.995 1919.260 4250.000 ;
    END
    PORT
      LAYER Metal4 ;
        RECT 1968.260 0.000 1969.260 196.145 ;
    END
    PORT
      LAYER Metal4 ;
        RECT 1968.260 4048.995 1969.260 4250.000 ;
    END
    PORT
      LAYER Metal4 ;
        RECT 2018.260 0.000 2019.260 196.145 ;
    END
    PORT
      LAYER Metal4 ;
        RECT 2018.260 4048.995 2019.260 4250.000 ;
    END
    PORT
      LAYER Metal4 ;
        RECT 2068.260 0.000 2069.260 196.145 ;
    END
    PORT
      LAYER Metal4 ;
        RECT 2068.260 4048.995 2069.260 4250.000 ;
    END
    PORT
      LAYER Metal4 ;
        RECT 2118.260 0.000 2119.260 196.145 ;
    END
    PORT
      LAYER Metal4 ;
        RECT 2118.260 4048.995 2119.260 4250.000 ;
    END
    PORT
      LAYER Metal4 ;
        RECT 2168.260 0.000 2169.260 196.145 ;
    END
    PORT
      LAYER Metal4 ;
        RECT 2168.260 4048.995 2169.260 4250.000 ;
    END
    PORT
      LAYER Metal4 ;
        RECT 2218.260 0.000 2219.260 196.145 ;
    END
    PORT
      LAYER Metal4 ;
        RECT 2218.260 4048.995 2219.260 4250.000 ;
    END
    PORT
      LAYER Metal4 ;
        RECT 2268.260 0.000 2269.260 196.145 ;
    END
    PORT
      LAYER Metal4 ;
        RECT 2268.260 4048.995 2269.260 4250.000 ;
    END
    PORT
      LAYER Metal4 ;
        RECT 2318.260 0.000 2319.260 196.145 ;
    END
    PORT
      LAYER Metal4 ;
        RECT 2318.260 4048.995 2319.260 4250.000 ;
    END
    PORT
      LAYER Metal4 ;
        RECT 2368.260 0.000 2369.260 196.145 ;
    END
    PORT
      LAYER Metal4 ;
        RECT 2368.260 4048.995 2369.260 4250.000 ;
    END
    PORT
      LAYER Metal4 ;
        RECT 2418.260 0.000 2419.260 196.145 ;
    END
    PORT
      LAYER Metal4 ;
        RECT 2418.260 4048.995 2419.260 4250.000 ;
    END
    PORT
      LAYER Metal4 ;
        RECT 2468.260 0.000 2469.260 196.145 ;
    END
    PORT
      LAYER Metal4 ;
        RECT 2468.260 4048.995 2469.260 4250.000 ;
    END
    PORT
      LAYER Metal4 ;
        RECT 2518.260 0.000 2519.260 196.145 ;
    END
    PORT
      LAYER Metal4 ;
        RECT 2518.260 4048.995 2519.260 4250.000 ;
    END
    PORT
      LAYER Metal4 ;
        RECT 2568.260 0.000 2569.260 196.145 ;
    END
    PORT
      LAYER Metal4 ;
        RECT 2568.260 4048.995 2569.260 4250.000 ;
    END
    PORT
      LAYER Metal4 ;
        RECT 2618.260 0.000 2619.260 196.145 ;
    END
    PORT
      LAYER Metal4 ;
        RECT 2618.260 4048.995 2619.260 4250.000 ;
    END
    PORT
      LAYER Metal4 ;
        RECT 2668.260 0.000 2669.260 196.145 ;
    END
    PORT
      LAYER Metal4 ;
        RECT 2668.260 4048.995 2669.260 4250.000 ;
    END
    PORT
      LAYER Metal4 ;
        RECT 2718.260 0.000 2719.260 196.145 ;
    END
    PORT
      LAYER Metal4 ;
        RECT 2718.260 4048.995 2719.260 4250.000 ;
    END
    PORT
      LAYER Metal4 ;
        RECT 2768.260 0.000 2769.260 196.145 ;
    END
    PORT
      LAYER Metal4 ;
        RECT 2768.260 4048.995 2769.260 4250.000 ;
    END
    PORT
      LAYER Metal4 ;
        RECT 2818.260 0.000 2819.260 196.145 ;
    END
    PORT
      LAYER Metal4 ;
        RECT 2818.260 4048.995 2819.260 4250.000 ;
    END
    PORT
      LAYER Metal4 ;
        RECT 2868.260 0.000 2869.260 196.145 ;
    END
    PORT
      LAYER Metal4 ;
        RECT 2868.260 4048.995 2869.260 4250.000 ;
    END
    PORT
      LAYER Metal4 ;
        RECT 2918.260 0.000 2919.260 301.730 ;
    END
    PORT
      LAYER Metal4 ;
        RECT 2918.260 577.210 2919.260 762.050 ;
    END
    PORT
      LAYER Metal4 ;
        RECT 2918.260 1037.530 2919.260 1222.370 ;
    END
    PORT
      LAYER Metal4 ;
        RECT 2918.260 1497.850 2919.260 1682.690 ;
    END
    PORT
      LAYER Metal4 ;
        RECT 2918.260 1958.170 2919.260 2143.010 ;
    END
    PORT
      LAYER Metal4 ;
        RECT 2918.260 2418.490 2919.260 2603.330 ;
    END
    PORT
      LAYER Metal4 ;
        RECT 2918.260 2878.810 2919.260 3063.650 ;
    END
    PORT
      LAYER Metal4 ;
        RECT 2918.260 3339.130 2919.260 3523.970 ;
    END
    PORT
      LAYER Metal4 ;
        RECT 2918.260 3799.450 2919.260 4250.000 ;
    END
    PORT
      LAYER Metal4 ;
        RECT 2968.260 0.000 2969.260 301.730 ;
    END
    PORT
      LAYER Metal4 ;
        RECT 2968.260 577.210 2969.260 762.050 ;
    END
    PORT
      LAYER Metal4 ;
        RECT 2968.260 1037.530 2969.260 1222.370 ;
    END
    PORT
      LAYER Metal4 ;
        RECT 2968.260 1497.850 2969.260 1682.690 ;
    END
    PORT
      LAYER Metal4 ;
        RECT 2968.260 1958.170 2969.260 2143.010 ;
    END
    PORT
      LAYER Metal4 ;
        RECT 2968.260 2418.490 2969.260 2603.330 ;
    END
    PORT
      LAYER Metal4 ;
        RECT 2968.260 2878.810 2969.260 3063.650 ;
    END
    PORT
      LAYER Metal4 ;
        RECT 2968.260 3339.130 2969.260 3523.970 ;
    END
    PORT
      LAYER Metal4 ;
        RECT 2968.260 3799.450 2969.260 4250.000 ;
    END
    PORT
      LAYER Metal4 ;
        RECT 3018.260 0.000 3019.260 301.730 ;
    END
    PORT
      LAYER Metal4 ;
        RECT 3018.260 577.210 3019.260 762.050 ;
    END
    PORT
      LAYER Metal4 ;
        RECT 3018.260 1037.530 3019.260 1222.370 ;
    END
    PORT
      LAYER Metal4 ;
        RECT 3018.260 1497.850 3019.260 1682.690 ;
    END
    PORT
      LAYER Metal4 ;
        RECT 3018.260 1958.170 3019.260 2143.010 ;
    END
    PORT
      LAYER Metal4 ;
        RECT 3018.260 2418.490 3019.260 2603.330 ;
    END
    PORT
      LAYER Metal4 ;
        RECT 3018.260 2878.810 3019.260 3063.650 ;
    END
    PORT
      LAYER Metal4 ;
        RECT 3018.260 3339.130 3019.260 3523.970 ;
    END
    PORT
      LAYER Metal4 ;
        RECT 3018.260 3799.450 3019.260 4250.000 ;
    END
    PORT
      LAYER Metal4 ;
        RECT 3068.260 0.000 3069.260 4250.000 ;
    END
    PORT
      LAYER Metal4 ;
        RECT 3118.260 0.000 3119.260 4250.000 ;
    END
    PORT
      LAYER Metal4 ;
        RECT 3168.260 0.000 3169.260 4250.000 ;
    END
    PORT
      LAYER Metal4 ;
        RECT 3218.260 0.000 3219.260 4250.000 ;
    END
    PORT
      LAYER Metal4 ;
        RECT 3268.260 0.000 3269.260 4250.000 ;
    END
    PORT
      LAYER Metal4 ;
        RECT 3318.260 0.000 3319.260 4250.000 ;
    END
    PORT
      LAYER Metal4 ;
        RECT 3368.260 0.000 3369.260 4250.000 ;
    END
    PORT
      LAYER Metal4 ;
        RECT 3418.260 0.000 3419.260 4250.000 ;
    END
    PORT
      LAYER Metal4 ;
        RECT 3468.260 0.000 3469.260 4250.000 ;
    END
    PORT
      LAYER Metal4 ;
        RECT 3518.260 0.000 3519.260 4250.000 ;
    END
    PORT
      LAYER Metal4 ;
        RECT 3568.260 0.000 3569.260 160.655 ;
    END
    PORT
      LAYER Metal4 ;
        RECT 3568.260 626.200 3569.260 666.985 ;
    END
    PORT
      LAYER Metal4 ;
        RECT 3568.260 1132.530 3569.260 1173.315 ;
    END
    PORT
      LAYER Metal4 ;
        RECT 3568.260 1638.860 3569.260 1679.645 ;
    END
    PORT
      LAYER Metal4 ;
        RECT 3568.260 2145.190 3569.260 2185.975 ;
    END
    PORT
      LAYER Metal4 ;
        RECT 3568.260 2651.520 3569.260 2692.305 ;
    END
    PORT
      LAYER Metal4 ;
        RECT 3568.260 3157.850 3569.260 3198.635 ;
    END
    PORT
      LAYER Metal4 ;
        RECT 3568.260 3664.180 3569.260 3704.965 ;
    END
    PORT
      LAYER Metal4 ;
        RECT 3568.260 4170.510 3569.260 4250.000 ;
    END
    PORT
      LAYER Metal4 ;
        RECT 3618.260 0.000 3619.260 160.655 ;
    END
    PORT
      LAYER Metal4 ;
        RECT 3618.260 626.200 3619.260 666.985 ;
    END
    PORT
      LAYER Metal4 ;
        RECT 3618.260 1132.530 3619.260 1173.315 ;
    END
    PORT
      LAYER Metal4 ;
        RECT 3618.260 1638.860 3619.260 1679.645 ;
    END
    PORT
      LAYER Metal4 ;
        RECT 3618.260 2145.190 3619.260 2185.975 ;
    END
    PORT
      LAYER Metal4 ;
        RECT 3618.260 2651.520 3619.260 2692.305 ;
    END
    PORT
      LAYER Metal4 ;
        RECT 3618.260 3157.850 3619.260 3198.635 ;
    END
    PORT
      LAYER Metal4 ;
        RECT 3618.260 3664.180 3619.260 3704.965 ;
    END
    PORT
      LAYER Metal4 ;
        RECT 3618.260 4170.510 3619.260 4250.000 ;
    END
    PORT
      LAYER Metal4 ;
        RECT 3668.260 0.000 3669.260 160.655 ;
    END
    PORT
      LAYER Metal4 ;
        RECT 3668.260 626.200 3669.260 666.985 ;
    END
    PORT
      LAYER Metal4 ;
        RECT 3668.260 1132.530 3669.260 1173.315 ;
    END
    PORT
      LAYER Metal4 ;
        RECT 3668.260 1638.860 3669.260 1679.645 ;
    END
    PORT
      LAYER Metal4 ;
        RECT 3668.260 2145.190 3669.260 2185.975 ;
    END
    PORT
      LAYER Metal4 ;
        RECT 3668.260 2651.520 3669.260 2692.305 ;
    END
    PORT
      LAYER Metal4 ;
        RECT 3668.260 3157.850 3669.260 3198.635 ;
    END
    PORT
      LAYER Metal4 ;
        RECT 3668.260 3664.180 3669.260 3704.965 ;
    END
    PORT
      LAYER Metal4 ;
        RECT 3668.260 4170.510 3669.260 4250.000 ;
    END
    PORT
      LAYER Metal4 ;
        RECT 3718.260 0.000 3719.260 160.655 ;
    END
    PORT
      LAYER Metal4 ;
        RECT 3718.260 626.200 3719.260 666.985 ;
    END
    PORT
      LAYER Metal4 ;
        RECT 3718.260 1132.530 3719.260 1173.315 ;
    END
    PORT
      LAYER Metal4 ;
        RECT 3718.260 1638.860 3719.260 1679.645 ;
    END
    PORT
      LAYER Metal4 ;
        RECT 3718.260 2145.190 3719.260 2185.975 ;
    END
    PORT
      LAYER Metal4 ;
        RECT 3718.260 2651.520 3719.260 2692.305 ;
    END
    PORT
      LAYER Metal4 ;
        RECT 3718.260 3157.850 3719.260 3198.635 ;
    END
    PORT
      LAYER Metal4 ;
        RECT 3718.260 3664.180 3719.260 3704.965 ;
    END
    PORT
      LAYER Metal4 ;
        RECT 3718.260 4170.510 3719.260 4250.000 ;
    END
    PORT
      LAYER Metal4 ;
        RECT 3768.260 0.000 3769.260 160.655 ;
    END
    PORT
      LAYER Metal4 ;
        RECT 3768.260 626.200 3769.260 666.985 ;
    END
    PORT
      LAYER Metal4 ;
        RECT 3768.260 1132.530 3769.260 1173.315 ;
    END
    PORT
      LAYER Metal4 ;
        RECT 3768.260 1638.860 3769.260 1679.645 ;
    END
    PORT
      LAYER Metal4 ;
        RECT 3768.260 2145.190 3769.260 2185.975 ;
    END
    PORT
      LAYER Metal4 ;
        RECT 3768.260 2651.520 3769.260 2692.305 ;
    END
    PORT
      LAYER Metal4 ;
        RECT 3768.260 3157.850 3769.260 3198.635 ;
    END
    PORT
      LAYER Metal4 ;
        RECT 3768.260 3664.180 3769.260 3704.965 ;
    END
    PORT
      LAYER Metal4 ;
        RECT 3768.260 4170.510 3769.260 4250.000 ;
    END
    PORT
      LAYER Metal4 ;
        RECT 3818.260 0.000 3819.260 160.655 ;
    END
    PORT
      LAYER Metal4 ;
        RECT 3818.260 626.200 3819.260 666.985 ;
    END
    PORT
      LAYER Metal4 ;
        RECT 3818.260 1132.530 3819.260 1173.315 ;
    END
    PORT
      LAYER Metal4 ;
        RECT 3818.260 1638.860 3819.260 1679.645 ;
    END
    PORT
      LAYER Metal4 ;
        RECT 3818.260 2145.190 3819.260 2185.975 ;
    END
    PORT
      LAYER Metal4 ;
        RECT 3818.260 2651.520 3819.260 2692.305 ;
    END
    PORT
      LAYER Metal4 ;
        RECT 3818.260 3157.850 3819.260 3198.635 ;
    END
    PORT
      LAYER Metal4 ;
        RECT 3818.260 3664.180 3819.260 3704.965 ;
    END
    PORT
      LAYER Metal4 ;
        RECT 3818.260 4170.510 3819.260 4250.000 ;
    END
    PORT
      LAYER Metal4 ;
        RECT 3868.260 0.000 3869.260 160.655 ;
    END
    PORT
      LAYER Metal4 ;
        RECT 3868.260 626.200 3869.260 666.985 ;
    END
    PORT
      LAYER Metal4 ;
        RECT 3868.260 1132.530 3869.260 1173.315 ;
    END
    PORT
      LAYER Metal4 ;
        RECT 3868.260 1638.860 3869.260 1679.645 ;
    END
    PORT
      LAYER Metal4 ;
        RECT 3868.260 2145.190 3869.260 2185.975 ;
    END
    PORT
      LAYER Metal4 ;
        RECT 3868.260 2651.520 3869.260 2692.305 ;
    END
    PORT
      LAYER Metal4 ;
        RECT 3868.260 3157.850 3869.260 3198.635 ;
    END
    PORT
      LAYER Metal4 ;
        RECT 3868.260 3664.180 3869.260 3704.965 ;
    END
    PORT
      LAYER Metal4 ;
        RECT 3868.260 4170.510 3869.260 4250.000 ;
    END
    PORT
      LAYER Metal4 ;
        RECT 3918.260 0.000 3919.260 160.655 ;
    END
    PORT
      LAYER Metal4 ;
        RECT 3918.260 626.200 3919.260 666.985 ;
    END
    PORT
      LAYER Metal4 ;
        RECT 3918.260 1132.530 3919.260 1173.315 ;
    END
    PORT
      LAYER Metal4 ;
        RECT 3918.260 1638.860 3919.260 1679.645 ;
    END
    PORT
      LAYER Metal4 ;
        RECT 3918.260 2145.190 3919.260 2185.975 ;
    END
    PORT
      LAYER Metal4 ;
        RECT 3918.260 2651.520 3919.260 2692.305 ;
    END
    PORT
      LAYER Metal4 ;
        RECT 3918.260 3157.850 3919.260 3198.635 ;
    END
    PORT
      LAYER Metal4 ;
        RECT 3918.260 3664.180 3919.260 3704.965 ;
    END
    PORT
      LAYER Metal4 ;
        RECT 3918.260 4170.510 3919.260 4250.000 ;
    END
    PORT
      LAYER Metal4 ;
        RECT 3968.260 0.000 3969.260 160.655 ;
    END
    PORT
      LAYER Metal4 ;
        RECT 3968.260 626.200 3969.260 666.985 ;
    END
    PORT
      LAYER Metal4 ;
        RECT 3968.260 1132.530 3969.260 1173.315 ;
    END
    PORT
      LAYER Metal4 ;
        RECT 3968.260 1638.860 3969.260 1679.645 ;
    END
    PORT
      LAYER Metal4 ;
        RECT 3968.260 2145.190 3969.260 2185.975 ;
    END
    PORT
      LAYER Metal4 ;
        RECT 3968.260 2651.520 3969.260 2692.305 ;
    END
    PORT
      LAYER Metal4 ;
        RECT 3968.260 3157.850 3969.260 3198.635 ;
    END
    PORT
      LAYER Metal4 ;
        RECT 3968.260 3664.180 3969.260 3704.965 ;
    END
    PORT
      LAYER Metal4 ;
        RECT 3968.260 4170.510 3969.260 4250.000 ;
    END
    PORT
      LAYER TopMetal1 ;
        RECT 0.000 30.120 4000.000 32.120 ;
    END
    PORT
      LAYER TopMetal1 ;
        RECT 0.000 76.150 4000.000 78.150 ;
    END
    PORT
      LAYER TopMetal1 ;
        RECT 0.000 122.180 4000.000 124.180 ;
    END
    PORT
      LAYER TopMetal1 ;
        RECT 0.000 168.210 4000.000 170.210 ;
    END
    PORT
      LAYER TopMetal1 ;
        RECT 0.000 214.240 4000.000 216.240 ;
    END
    PORT
      LAYER TopMetal1 ;
        RECT 0.000 260.270 4000.000 262.270 ;
    END
    PORT
      LAYER TopMetal1 ;
        RECT 0.000 306.300 2879.840 308.300 ;
    END
    PORT
      LAYER TopMetal1 ;
        RECT 0.000 352.330 2879.840 354.330 ;
    END
    PORT
      LAYER TopMetal1 ;
        RECT 0.000 398.360 2879.840 400.360 ;
    END
    PORT
      LAYER TopMetal1 ;
        RECT 0.000 444.390 2879.840 446.390 ;
    END
    PORT
      LAYER TopMetal1 ;
        RECT 0.000 490.420 2879.840 492.420 ;
    END
    PORT
      LAYER TopMetal1 ;
        RECT 0.000 536.450 2879.840 538.450 ;
    END
    PORT
      LAYER TopMetal1 ;
        RECT 0.000 582.480 4000.000 584.480 ;
    END
    PORT
      LAYER TopMetal1 ;
        RECT 0.000 628.510 4000.000 630.510 ;
    END
    PORT
      LAYER TopMetal1 ;
        RECT 0.000 674.540 4000.000 676.540 ;
    END
    PORT
      LAYER TopMetal1 ;
        RECT 0.000 720.570 4000.000 722.570 ;
    END
    PORT
      LAYER TopMetal1 ;
        RECT 0.000 766.600 2879.840 768.600 ;
    END
    PORT
      LAYER TopMetal1 ;
        RECT 0.000 812.630 2879.840 814.630 ;
    END
    PORT
      LAYER TopMetal1 ;
        RECT 0.000 858.660 2879.840 860.660 ;
    END
    PORT
      LAYER TopMetal1 ;
        RECT 0.000 904.690 2879.840 906.690 ;
    END
    PORT
      LAYER TopMetal1 ;
        RECT 0.000 950.720 2879.840 952.720 ;
    END
    PORT
      LAYER TopMetal1 ;
        RECT 0.000 996.750 2879.840 998.750 ;
    END
    PORT
      LAYER TopMetal1 ;
        RECT 0.000 1042.780 4000.000 1044.780 ;
    END
    PORT
      LAYER TopMetal1 ;
        RECT 0.000 1088.810 4000.000 1090.810 ;
    END
    PORT
      LAYER TopMetal1 ;
        RECT 0.000 1134.840 4000.000 1136.840 ;
    END
    PORT
      LAYER TopMetal1 ;
        RECT 0.000 1180.870 4000.000 1182.870 ;
    END
    PORT
      LAYER TopMetal1 ;
        RECT 0.000 1226.900 2879.840 1228.900 ;
    END
    PORT
      LAYER TopMetal1 ;
        RECT 0.000 1272.930 2879.840 1274.930 ;
    END
    PORT
      LAYER TopMetal1 ;
        RECT 0.000 1318.960 2879.840 1320.960 ;
    END
    PORT
      LAYER TopMetal1 ;
        RECT 0.000 1364.990 2879.840 1366.990 ;
    END
    PORT
      LAYER TopMetal1 ;
        RECT 0.000 1411.020 2879.840 1413.020 ;
    END
    PORT
      LAYER TopMetal1 ;
        RECT 0.000 1457.050 2879.840 1459.050 ;
    END
    PORT
      LAYER TopMetal1 ;
        RECT 0.000 1503.080 4000.000 1505.080 ;
    END
    PORT
      LAYER TopMetal1 ;
        RECT 0.000 1549.110 4000.000 1551.110 ;
    END
    PORT
      LAYER TopMetal1 ;
        RECT 0.000 1595.140 4000.000 1597.140 ;
    END
    PORT
      LAYER TopMetal1 ;
        RECT 0.000 1641.170 4000.000 1643.170 ;
    END
    PORT
      LAYER TopMetal1 ;
        RECT 0.000 1687.200 2879.840 1689.200 ;
    END
    PORT
      LAYER TopMetal1 ;
        RECT 0.000 1733.230 2879.840 1735.230 ;
    END
    PORT
      LAYER TopMetal1 ;
        RECT 0.000 1779.260 2879.840 1781.260 ;
    END
    PORT
      LAYER TopMetal1 ;
        RECT 0.000 1825.290 2879.840 1827.290 ;
    END
    PORT
      LAYER TopMetal1 ;
        RECT 0.000 1871.320 2879.840 1873.320 ;
    END
    PORT
      LAYER TopMetal1 ;
        RECT 0.000 1917.350 2879.840 1919.350 ;
    END
    PORT
      LAYER TopMetal1 ;
        RECT 0.000 1963.380 4000.000 1965.380 ;
    END
    PORT
      LAYER TopMetal1 ;
        RECT 0.000 2009.410 4000.000 2011.410 ;
    END
    PORT
      LAYER TopMetal1 ;
        RECT 0.000 2055.440 4000.000 2057.440 ;
    END
    PORT
      LAYER TopMetal1 ;
        RECT 0.000 2101.470 4000.000 2103.470 ;
    END
    PORT
      LAYER TopMetal1 ;
        RECT 0.000 2147.500 2879.840 2149.500 ;
    END
    PORT
      LAYER TopMetal1 ;
        RECT 0.000 2193.530 2879.840 2195.530 ;
    END
    PORT
      LAYER TopMetal1 ;
        RECT 0.000 2239.560 2879.840 2241.560 ;
    END
    PORT
      LAYER TopMetal1 ;
        RECT 0.000 2285.590 2879.840 2287.590 ;
    END
    PORT
      LAYER TopMetal1 ;
        RECT 0.000 2331.620 2879.840 2333.620 ;
    END
    PORT
      LAYER TopMetal1 ;
        RECT 0.000 2377.650 2879.840 2379.650 ;
    END
    PORT
      LAYER TopMetal1 ;
        RECT 0.000 2423.680 4000.000 2425.680 ;
    END
    PORT
      LAYER TopMetal1 ;
        RECT 0.000 2469.710 4000.000 2471.710 ;
    END
    PORT
      LAYER TopMetal1 ;
        RECT 0.000 2515.740 4000.000 2517.740 ;
    END
    PORT
      LAYER TopMetal1 ;
        RECT 0.000 2561.770 4000.000 2563.770 ;
    END
    PORT
      LAYER TopMetal1 ;
        RECT 0.000 2607.800 2879.840 2609.800 ;
    END
    PORT
      LAYER TopMetal1 ;
        RECT 0.000 2653.830 2879.840 2655.830 ;
    END
    PORT
      LAYER TopMetal1 ;
        RECT 0.000 2699.860 2879.840 2701.860 ;
    END
    PORT
      LAYER TopMetal1 ;
        RECT 0.000 2745.890 2879.840 2747.890 ;
    END
    PORT
      LAYER TopMetal1 ;
        RECT 0.000 2791.920 2879.840 2793.920 ;
    END
    PORT
      LAYER TopMetal1 ;
        RECT 0.000 2837.950 2879.840 2839.950 ;
    END
    PORT
      LAYER TopMetal1 ;
        RECT 0.000 2883.980 4000.000 2885.980 ;
    END
    PORT
      LAYER TopMetal1 ;
        RECT 0.000 2930.010 4000.000 2932.010 ;
    END
    PORT
      LAYER TopMetal1 ;
        RECT 0.000 2976.040 4000.000 2978.040 ;
    END
    PORT
      LAYER TopMetal1 ;
        RECT 0.000 3022.070 4000.000 3024.070 ;
    END
    PORT
      LAYER TopMetal1 ;
        RECT 0.000 3068.100 2879.840 3070.100 ;
    END
    PORT
      LAYER TopMetal1 ;
        RECT 0.000 3114.130 2879.840 3116.130 ;
    END
    PORT
      LAYER TopMetal1 ;
        RECT 0.000 3160.160 2879.840 3162.160 ;
    END
    PORT
      LAYER TopMetal1 ;
        RECT 0.000 3206.190 2879.840 3208.190 ;
    END
    PORT
      LAYER TopMetal1 ;
        RECT 0.000 3252.220 2879.840 3254.220 ;
    END
    PORT
      LAYER TopMetal1 ;
        RECT 0.000 3298.250 2879.840 3300.250 ;
    END
    PORT
      LAYER TopMetal1 ;
        RECT 0.000 3344.280 4000.000 3346.280 ;
    END
    PORT
      LAYER TopMetal1 ;
        RECT 0.000 3390.310 4000.000 3392.310 ;
    END
    PORT
      LAYER TopMetal1 ;
        RECT 0.000 3436.340 4000.000 3438.340 ;
    END
    PORT
      LAYER TopMetal1 ;
        RECT 0.000 3482.370 4000.000 3484.370 ;
    END
    PORT
      LAYER TopMetal1 ;
        RECT 0.000 3528.400 2879.840 3530.400 ;
    END
    PORT
      LAYER TopMetal1 ;
        RECT 0.000 3574.430 2879.840 3576.430 ;
    END
    PORT
      LAYER TopMetal1 ;
        RECT 0.000 3620.460 2879.840 3622.460 ;
    END
    PORT
      LAYER TopMetal1 ;
        RECT 0.000 3666.490 2879.840 3668.490 ;
    END
    PORT
      LAYER TopMetal1 ;
        RECT 0.000 3712.520 2879.840 3714.520 ;
    END
    PORT
      LAYER TopMetal1 ;
        RECT 0.000 3758.550 2879.840 3760.550 ;
    END
    PORT
      LAYER TopMetal1 ;
        RECT 0.000 3804.580 4000.000 3806.580 ;
    END
    PORT
      LAYER TopMetal1 ;
        RECT 0.000 3850.610 4000.000 3852.610 ;
    END
    PORT
      LAYER TopMetal1 ;
        RECT 0.000 3896.640 4000.000 3898.640 ;
    END
    PORT
      LAYER TopMetal1 ;
        RECT 0.000 3942.670 4000.000 3944.670 ;
    END
    PORT
      LAYER TopMetal1 ;
        RECT 0.000 3988.700 4000.000 3990.700 ;
    END
    PORT
      LAYER TopMetal1 ;
        RECT 0.000 4034.730 4000.000 4036.730 ;
    END
    PORT
      LAYER TopMetal1 ;
        RECT 0.000 4080.760 4000.000 4082.760 ;
    END
    PORT
      LAYER TopMetal1 ;
        RECT 0.000 4126.790 4000.000 4128.790 ;
    END
    PORT
      LAYER TopMetal1 ;
        RECT 0.000 4172.820 4000.000 4174.820 ;
    END
    PORT
      LAYER TopMetal1 ;
        RECT 0.000 4218.850 4000.000 4220.850 ;
    END
    PORT
      LAYER TopMetal1 ;
        RECT 3014.400 306.300 4000.000 308.300 ;
    END
    PORT
      LAYER TopMetal1 ;
        RECT 3014.400 352.330 4000.000 354.330 ;
    END
    PORT
      LAYER TopMetal1 ;
        RECT 3014.400 398.360 4000.000 400.360 ;
    END
    PORT
      LAYER TopMetal1 ;
        RECT 3014.400 444.390 4000.000 446.390 ;
    END
    PORT
      LAYER TopMetal1 ;
        RECT 3014.400 490.420 4000.000 492.420 ;
    END
    PORT
      LAYER TopMetal1 ;
        RECT 3014.400 536.450 4000.000 538.450 ;
    END
    PORT
      LAYER TopMetal1 ;
        RECT 3014.400 766.600 4000.000 768.600 ;
    END
    PORT
      LAYER TopMetal1 ;
        RECT 3014.400 812.630 4000.000 814.630 ;
    END
    PORT
      LAYER TopMetal1 ;
        RECT 3014.400 858.660 4000.000 860.660 ;
    END
    PORT
      LAYER TopMetal1 ;
        RECT 3014.400 904.690 4000.000 906.690 ;
    END
    PORT
      LAYER TopMetal1 ;
        RECT 3014.400 950.720 4000.000 952.720 ;
    END
    PORT
      LAYER TopMetal1 ;
        RECT 3014.400 996.750 4000.000 998.750 ;
    END
    PORT
      LAYER TopMetal1 ;
        RECT 3014.400 1226.900 4000.000 1228.900 ;
    END
    PORT
      LAYER TopMetal1 ;
        RECT 3014.400 1272.930 4000.000 1274.930 ;
    END
    PORT
      LAYER TopMetal1 ;
        RECT 3014.400 1318.960 4000.000 1320.960 ;
    END
    PORT
      LAYER TopMetal1 ;
        RECT 3014.400 1364.990 4000.000 1366.990 ;
    END
    PORT
      LAYER TopMetal1 ;
        RECT 3014.400 1411.020 4000.000 1413.020 ;
    END
    PORT
      LAYER TopMetal1 ;
        RECT 3014.400 1457.050 4000.000 1459.050 ;
    END
    PORT
      LAYER TopMetal1 ;
        RECT 3014.400 1687.200 4000.000 1689.200 ;
    END
    PORT
      LAYER TopMetal1 ;
        RECT 3014.400 1733.230 4000.000 1735.230 ;
    END
    PORT
      LAYER TopMetal1 ;
        RECT 3014.400 1779.260 4000.000 1781.260 ;
    END
    PORT
      LAYER TopMetal1 ;
        RECT 3014.400 1825.290 4000.000 1827.290 ;
    END
    PORT
      LAYER TopMetal1 ;
        RECT 3014.400 1871.320 4000.000 1873.320 ;
    END
    PORT
      LAYER TopMetal1 ;
        RECT 3014.400 1917.350 4000.000 1919.350 ;
    END
    PORT
      LAYER TopMetal1 ;
        RECT 3014.400 2147.500 4000.000 2149.500 ;
    END
    PORT
      LAYER TopMetal1 ;
        RECT 3014.400 2193.530 4000.000 2195.530 ;
    END
    PORT
      LAYER TopMetal1 ;
        RECT 3014.400 2239.560 4000.000 2241.560 ;
    END
    PORT
      LAYER TopMetal1 ;
        RECT 3014.400 2285.590 4000.000 2287.590 ;
    END
    PORT
      LAYER TopMetal1 ;
        RECT 3014.400 2331.620 4000.000 2333.620 ;
    END
    PORT
      LAYER TopMetal1 ;
        RECT 3014.400 2377.650 4000.000 2379.650 ;
    END
    PORT
      LAYER TopMetal1 ;
        RECT 3014.400 2607.800 4000.000 2609.800 ;
    END
    PORT
      LAYER TopMetal1 ;
        RECT 3014.400 2653.830 4000.000 2655.830 ;
    END
    PORT
      LAYER TopMetal1 ;
        RECT 3014.400 2699.860 4000.000 2701.860 ;
    END
    PORT
      LAYER TopMetal1 ;
        RECT 3014.400 2745.890 4000.000 2747.890 ;
    END
    PORT
      LAYER TopMetal1 ;
        RECT 3014.400 2791.920 4000.000 2793.920 ;
    END
    PORT
      LAYER TopMetal1 ;
        RECT 3014.400 2837.950 4000.000 2839.950 ;
    END
    PORT
      LAYER TopMetal1 ;
        RECT 3014.400 3068.100 4000.000 3070.100 ;
    END
    PORT
      LAYER TopMetal1 ;
        RECT 3014.400 3114.130 4000.000 3116.130 ;
    END
    PORT
      LAYER TopMetal1 ;
        RECT 3014.400 3160.160 4000.000 3162.160 ;
    END
    PORT
      LAYER TopMetal1 ;
        RECT 3014.400 3206.190 4000.000 3208.190 ;
    END
    PORT
      LAYER TopMetal1 ;
        RECT 3014.400 3252.220 4000.000 3254.220 ;
    END
    PORT
      LAYER TopMetal1 ;
        RECT 3014.400 3298.250 4000.000 3300.250 ;
    END
    PORT
      LAYER TopMetal1 ;
        RECT 3014.400 3528.400 4000.000 3530.400 ;
    END
    PORT
      LAYER TopMetal1 ;
        RECT 3014.400 3574.430 4000.000 3576.430 ;
    END
    PORT
      LAYER TopMetal1 ;
        RECT 3014.400 3620.460 4000.000 3622.460 ;
    END
    PORT
      LAYER TopMetal1 ;
        RECT 3014.400 3666.490 4000.000 3668.490 ;
    END
    PORT
      LAYER TopMetal1 ;
        RECT 3014.400 3712.520 4000.000 3714.520 ;
    END
    PORT
      LAYER TopMetal1 ;
        RECT 3014.400 3758.550 4000.000 3760.550 ;
    END
  END VSS
  PIN clk_i
    DIRECTION INPUT ;
    USE SIGNAL ;
    ANTENNAGATEAREA 2.901600 ;
    ANTENNADIFFAREA 4.030800 ;
    PORT
      LAYER Metal2 ;
        RECT 65.560 0.000 65.960 0.400 ;
    END
  END clk_i
  PIN efpga_cfg_sclk_i
    DIRECTION INPUT ;
    USE SIGNAL ;
    ANTENNAGATEAREA 0.180700 ;
    ANTENNADIFFAREA 2.015400 ;
    PORT
      LAYER Metal2 ;
        RECT 50.200 4249.600 50.600 4250.000 ;
    END
  END efpga_cfg_sclk_i
  PIN efpga_cfg_sdata_i
    DIRECTION INPUT ;
    USE SIGNAL ;
    ANTENNAGATEAREA 0.180700 ;
    ANTENNADIFFAREA 2.015400 ;
    PORT
      LAYER Metal2 ;
        RECT 150.040 4249.600 150.440 4250.000 ;
    END
  END efpga_cfg_sdata_i
  PIN efpga_fault_irq_o
    DIRECTION OUTPUT ;
    USE SIGNAL ;
    ANTENNADIFFAREA 0.708600 ;
    PORT
      LAYER Metal2 ;
        RECT 732.760 0.000 733.160 0.400 ;
    END
  END efpga_fault_irq_o
  PIN efpga_usr_irq_o[0]
    DIRECTION OUTPUT ;
    USE SIGNAL ;
    ANTENNADIFFAREA 0.708600 ;
    PORT
      LAYER Metal2 ;
        RECT 360.280 0.000 360.680 0.400 ;
    END
  END efpga_usr_irq_o[0]
  PIN efpga_usr_irq_o[1]
    DIRECTION OUTPUT ;
    USE SIGNAL ;
    ANTENNADIFFAREA 0.708600 ;
    PORT
      LAYER Metal2 ;
        RECT 453.400 0.000 453.800 0.400 ;
    END
  END efpga_usr_irq_o[1]
  PIN efpga_usr_irq_o[2]
    DIRECTION OUTPUT ;
    USE SIGNAL ;
    ANTENNADIFFAREA 0.708600 ;
    PORT
      LAYER Metal2 ;
        RECT 546.520 0.000 546.920 0.400 ;
    END
  END efpga_usr_irq_o[2]
  PIN efpga_usr_irq_o[3]
    DIRECTION OUTPUT ;
    USE SIGNAL ;
    ANTENNADIFFAREA 0.708600 ;
    PORT
      LAYER Metal2 ;
        RECT 639.640 0.000 640.040 0.400 ;
    END
  END efpga_usr_irq_o[3]
  PIN m_axi_dma_araddr[0]
    DIRECTION OUTPUT ;
    USE SIGNAL ;
    ANTENNADIFFAREA 0.708600 ;
    PORT
      LAYER Metal3 ;
        RECT 0.000 2893.180 0.400 2893.580 ;
    END
  END m_axi_dma_araddr[0]
  PIN m_axi_dma_araddr[10]
    DIRECTION OUTPUT ;
    USE SIGNAL ;
    ANTENNADIFFAREA 0.708600 ;
    PORT
      LAYER Metal3 ;
        RECT 0.000 2977.180 0.400 2977.580 ;
    END
  END m_axi_dma_araddr[10]
  PIN m_axi_dma_araddr[11]
    DIRECTION OUTPUT ;
    USE SIGNAL ;
    ANTENNADIFFAREA 0.708600 ;
    PORT
      LAYER Metal3 ;
        RECT 0.000 2985.580 0.400 2985.980 ;
    END
  END m_axi_dma_araddr[11]
  PIN m_axi_dma_araddr[12]
    DIRECTION OUTPUT ;
    USE SIGNAL ;
    ANTENNADIFFAREA 0.708600 ;
    PORT
      LAYER Metal3 ;
        RECT 0.000 2993.980 0.400 2994.380 ;
    END
  END m_axi_dma_araddr[12]
  PIN m_axi_dma_araddr[13]
    DIRECTION OUTPUT ;
    USE SIGNAL ;
    ANTENNADIFFAREA 0.708600 ;
    PORT
      LAYER Metal3 ;
        RECT 0.000 3002.380 0.400 3002.780 ;
    END
  END m_axi_dma_araddr[13]
  PIN m_axi_dma_araddr[14]
    DIRECTION OUTPUT ;
    USE SIGNAL ;
    ANTENNADIFFAREA 0.708600 ;
    PORT
      LAYER Metal3 ;
        RECT 0.000 3010.780 0.400 3011.180 ;
    END
  END m_axi_dma_araddr[14]
  PIN m_axi_dma_araddr[15]
    DIRECTION OUTPUT ;
    USE SIGNAL ;
    ANTENNADIFFAREA 0.708600 ;
    PORT
      LAYER Metal3 ;
        RECT 0.000 3019.180 0.400 3019.580 ;
    END
  END m_axi_dma_araddr[15]
  PIN m_axi_dma_araddr[16]
    DIRECTION OUTPUT ;
    USE SIGNAL ;
    ANTENNADIFFAREA 0.708600 ;
    PORT
      LAYER Metal3 ;
        RECT 0.000 3027.580 0.400 3027.980 ;
    END
  END m_axi_dma_araddr[16]
  PIN m_axi_dma_araddr[17]
    DIRECTION OUTPUT ;
    USE SIGNAL ;
    ANTENNADIFFAREA 0.708600 ;
    PORT
      LAYER Metal3 ;
        RECT 0.000 3035.980 0.400 3036.380 ;
    END
  END m_axi_dma_araddr[17]
  PIN m_axi_dma_araddr[18]
    DIRECTION OUTPUT ;
    USE SIGNAL ;
    ANTENNADIFFAREA 0.708600 ;
    PORT
      LAYER Metal3 ;
        RECT 0.000 3044.380 0.400 3044.780 ;
    END
  END m_axi_dma_araddr[18]
  PIN m_axi_dma_araddr[19]
    DIRECTION OUTPUT ;
    USE SIGNAL ;
    ANTENNADIFFAREA 0.708600 ;
    PORT
      LAYER Metal3 ;
        RECT 0.000 3052.780 0.400 3053.180 ;
    END
  END m_axi_dma_araddr[19]
  PIN m_axi_dma_araddr[1]
    DIRECTION OUTPUT ;
    USE SIGNAL ;
    ANTENNADIFFAREA 0.708600 ;
    PORT
      LAYER Metal3 ;
        RECT 0.000 2901.580 0.400 2901.980 ;
    END
  END m_axi_dma_araddr[1]
  PIN m_axi_dma_araddr[20]
    DIRECTION OUTPUT ;
    USE SIGNAL ;
    ANTENNADIFFAREA 0.708600 ;
    PORT
      LAYER Metal3 ;
        RECT 0.000 3061.180 0.400 3061.580 ;
    END
  END m_axi_dma_araddr[20]
  PIN m_axi_dma_araddr[21]
    DIRECTION OUTPUT ;
    USE SIGNAL ;
    ANTENNADIFFAREA 0.708600 ;
    PORT
      LAYER Metal3 ;
        RECT 0.000 3069.580 0.400 3069.980 ;
    END
  END m_axi_dma_araddr[21]
  PIN m_axi_dma_araddr[22]
    DIRECTION OUTPUT ;
    USE SIGNAL ;
    ANTENNADIFFAREA 0.708600 ;
    PORT
      LAYER Metal3 ;
        RECT 0.000 3077.980 0.400 3078.380 ;
    END
  END m_axi_dma_araddr[22]
  PIN m_axi_dma_araddr[23]
    DIRECTION OUTPUT ;
    USE SIGNAL ;
    ANTENNADIFFAREA 0.708600 ;
    PORT
      LAYER Metal3 ;
        RECT 0.000 3086.380 0.400 3086.780 ;
    END
  END m_axi_dma_araddr[23]
  PIN m_axi_dma_araddr[24]
    DIRECTION OUTPUT ;
    USE SIGNAL ;
    ANTENNADIFFAREA 0.708600 ;
    PORT
      LAYER Metal3 ;
        RECT 0.000 3094.780 0.400 3095.180 ;
    END
  END m_axi_dma_araddr[24]
  PIN m_axi_dma_araddr[25]
    DIRECTION OUTPUT ;
    USE SIGNAL ;
    ANTENNADIFFAREA 0.708600 ;
    PORT
      LAYER Metal3 ;
        RECT 0.000 3103.180 0.400 3103.580 ;
    END
  END m_axi_dma_araddr[25]
  PIN m_axi_dma_araddr[26]
    DIRECTION OUTPUT ;
    USE SIGNAL ;
    ANTENNADIFFAREA 0.708600 ;
    PORT
      LAYER Metal3 ;
        RECT 0.000 3111.580 0.400 3111.980 ;
    END
  END m_axi_dma_araddr[26]
  PIN m_axi_dma_araddr[27]
    DIRECTION OUTPUT ;
    USE SIGNAL ;
    ANTENNADIFFAREA 0.708600 ;
    PORT
      LAYER Metal3 ;
        RECT 0.000 3119.980 0.400 3120.380 ;
    END
  END m_axi_dma_araddr[27]
  PIN m_axi_dma_araddr[28]
    DIRECTION OUTPUT ;
    USE SIGNAL ;
    ANTENNADIFFAREA 0.708600 ;
    PORT
      LAYER Metal3 ;
        RECT 0.000 3128.380 0.400 3128.780 ;
    END
  END m_axi_dma_araddr[28]
  PIN m_axi_dma_araddr[29]
    DIRECTION OUTPUT ;
    USE SIGNAL ;
    ANTENNADIFFAREA 0.708600 ;
    PORT
      LAYER Metal3 ;
        RECT 0.000 3136.780 0.400 3137.180 ;
    END
  END m_axi_dma_araddr[29]
  PIN m_axi_dma_araddr[2]
    DIRECTION OUTPUT ;
    USE SIGNAL ;
    ANTENNADIFFAREA 0.708600 ;
    PORT
      LAYER Metal3 ;
        RECT 0.000 2909.980 0.400 2910.380 ;
    END
  END m_axi_dma_araddr[2]
  PIN m_axi_dma_araddr[30]
    DIRECTION OUTPUT ;
    USE SIGNAL ;
    ANTENNADIFFAREA 0.708600 ;
    PORT
      LAYER Metal3 ;
        RECT 0.000 3145.180 0.400 3145.580 ;
    END
  END m_axi_dma_araddr[30]
  PIN m_axi_dma_araddr[31]
    DIRECTION OUTPUT ;
    USE SIGNAL ;
    ANTENNADIFFAREA 0.708600 ;
    PORT
      LAYER Metal3 ;
        RECT 0.000 3153.580 0.400 3153.980 ;
    END
  END m_axi_dma_araddr[31]
  PIN m_axi_dma_araddr[3]
    DIRECTION OUTPUT ;
    USE SIGNAL ;
    ANTENNADIFFAREA 0.708600 ;
    PORT
      LAYER Metal3 ;
        RECT 0.000 2918.380 0.400 2918.780 ;
    END
  END m_axi_dma_araddr[3]
  PIN m_axi_dma_araddr[4]
    DIRECTION OUTPUT ;
    USE SIGNAL ;
    ANTENNADIFFAREA 0.708600 ;
    PORT
      LAYER Metal3 ;
        RECT 0.000 2926.780 0.400 2927.180 ;
    END
  END m_axi_dma_araddr[4]
  PIN m_axi_dma_araddr[5]
    DIRECTION OUTPUT ;
    USE SIGNAL ;
    ANTENNADIFFAREA 0.708600 ;
    PORT
      LAYER Metal3 ;
        RECT 0.000 2935.180 0.400 2935.580 ;
    END
  END m_axi_dma_araddr[5]
  PIN m_axi_dma_araddr[6]
    DIRECTION OUTPUT ;
    USE SIGNAL ;
    ANTENNADIFFAREA 0.708600 ;
    PORT
      LAYER Metal3 ;
        RECT 0.000 2943.580 0.400 2943.980 ;
    END
  END m_axi_dma_araddr[6]
  PIN m_axi_dma_araddr[7]
    DIRECTION OUTPUT ;
    USE SIGNAL ;
    ANTENNADIFFAREA 0.708600 ;
    PORT
      LAYER Metal3 ;
        RECT 0.000 2951.980 0.400 2952.380 ;
    END
  END m_axi_dma_araddr[7]
  PIN m_axi_dma_araddr[8]
    DIRECTION OUTPUT ;
    USE SIGNAL ;
    ANTENNADIFFAREA 0.708600 ;
    PORT
      LAYER Metal3 ;
        RECT 0.000 2960.380 0.400 2960.780 ;
    END
  END m_axi_dma_araddr[8]
  PIN m_axi_dma_araddr[9]
    DIRECTION OUTPUT ;
    USE SIGNAL ;
    ANTENNADIFFAREA 0.708600 ;
    PORT
      LAYER Metal3 ;
        RECT 0.000 2968.780 0.400 2969.180 ;
    END
  END m_axi_dma_araddr[9]
  PIN m_axi_dma_arburst[0]
    DIRECTION OUTPUT ;
    USE SIGNAL ;
    ANTENNADIFFAREA 0.708600 ;
    PORT
      LAYER Metal3 ;
        RECT 0.000 2783.980 0.400 2784.380 ;
    END
  END m_axi_dma_arburst[0]
  PIN m_axi_dma_arburst[1]
    DIRECTION OUTPUT ;
    USE SIGNAL ;
    ANTENNADIFFAREA 0.708600 ;
    PORT
      LAYER Metal3 ;
        RECT 0.000 2792.380 0.400 2792.780 ;
    END
  END m_axi_dma_arburst[1]
  PIN m_axi_dma_arcache[0]
    DIRECTION OUTPUT ;
    USE SIGNAL ;
    ANTENNADIFFAREA 0.708600 ;
    PORT
      LAYER Metal3 ;
        RECT 0.000 2741.980 0.400 2742.380 ;
    END
  END m_axi_dma_arcache[0]
  PIN m_axi_dma_arcache[1]
    DIRECTION OUTPUT ;
    USE SIGNAL ;
    ANTENNADIFFAREA 0.708600 ;
    PORT
      LAYER Metal3 ;
        RECT 0.000 2750.380 0.400 2750.780 ;
    END
  END m_axi_dma_arcache[1]
  PIN m_axi_dma_arcache[2]
    DIRECTION OUTPUT ;
    USE SIGNAL ;
    ANTENNADIFFAREA 0.708600 ;
    PORT
      LAYER Metal3 ;
        RECT 0.000 2758.780 0.400 2759.180 ;
    END
  END m_axi_dma_arcache[2]
  PIN m_axi_dma_arcache[3]
    DIRECTION OUTPUT ;
    USE SIGNAL ;
    ANTENNADIFFAREA 0.708600 ;
    PORT
      LAYER Metal3 ;
        RECT 0.000 2767.180 0.400 2767.580 ;
    END
  END m_axi_dma_arcache[3]
  PIN m_axi_dma_arid[0]
    DIRECTION OUTPUT ;
    USE SIGNAL ;
    ANTENNADIFFAREA 0.708600 ;
    PORT
      LAYER Metal3 ;
        RECT 0.000 3161.980 0.400 3162.380 ;
    END
  END m_axi_dma_arid[0]
  PIN m_axi_dma_arid[1]
    DIRECTION OUTPUT ;
    USE SIGNAL ;
    ANTENNADIFFAREA 0.299200 ;
    PORT
      LAYER Metal3 ;
        RECT 0.000 3170.380 0.400 3170.780 ;
    END
  END m_axi_dma_arid[1]
  PIN m_axi_dma_arid[2]
    DIRECTION OUTPUT ;
    USE SIGNAL ;
    ANTENNADIFFAREA 0.299200 ;
    PORT
      LAYER Metal3 ;
        RECT 0.000 3178.780 0.400 3179.180 ;
    END
  END m_axi_dma_arid[2]
  PIN m_axi_dma_arid[3]
    DIRECTION OUTPUT ;
    USE SIGNAL ;
    ANTENNADIFFAREA 0.299200 ;
    PORT
      LAYER Metal3 ;
        RECT 0.000 3187.180 0.400 3187.580 ;
    END
  END m_axi_dma_arid[3]
  PIN m_axi_dma_arid[4]
    DIRECTION OUTPUT ;
    USE SIGNAL ;
    ANTENNADIFFAREA 0.299200 ;
    PORT
      LAYER Metal3 ;
        RECT 0.000 3195.580 0.400 3195.980 ;
    END
  END m_axi_dma_arid[4]
  PIN m_axi_dma_arid[5]
    DIRECTION OUTPUT ;
    USE SIGNAL ;
    ANTENNADIFFAREA 0.299200 ;
    PORT
      LAYER Metal3 ;
        RECT 0.000 3203.980 0.400 3204.380 ;
    END
  END m_axi_dma_arid[5]
  PIN m_axi_dma_arid[6]
    DIRECTION OUTPUT ;
    USE SIGNAL ;
    ANTENNADIFFAREA 0.299200 ;
    PORT
      LAYER Metal3 ;
        RECT 0.000 3212.380 0.400 3212.780 ;
    END
  END m_axi_dma_arid[6]
  PIN m_axi_dma_arid[7]
    DIRECTION OUTPUT ;
    USE SIGNAL ;
    ANTENNADIFFAREA 0.299200 ;
    PORT
      LAYER Metal3 ;
        RECT 0.000 3220.780 0.400 3221.180 ;
    END
  END m_axi_dma_arid[7]
  PIN m_axi_dma_arlen[0]
    DIRECTION OUTPUT ;
    USE SIGNAL ;
    ANTENNADIFFAREA 0.708600 ;
    PORT
      LAYER Metal3 ;
        RECT 0.000 2825.980 0.400 2826.380 ;
    END
  END m_axi_dma_arlen[0]
  PIN m_axi_dma_arlen[1]
    DIRECTION OUTPUT ;
    USE SIGNAL ;
    ANTENNADIFFAREA 0.708600 ;
    PORT
      LAYER Metal3 ;
        RECT 0.000 2834.380 0.400 2834.780 ;
    END
  END m_axi_dma_arlen[1]
  PIN m_axi_dma_arlen[2]
    DIRECTION OUTPUT ;
    USE SIGNAL ;
    ANTENNADIFFAREA 0.708600 ;
    PORT
      LAYER Metal3 ;
        RECT 0.000 2842.780 0.400 2843.180 ;
    END
  END m_axi_dma_arlen[2]
  PIN m_axi_dma_arlen[3]
    DIRECTION OUTPUT ;
    USE SIGNAL ;
    ANTENNADIFFAREA 0.708600 ;
    PORT
      LAYER Metal3 ;
        RECT 0.000 2851.180 0.400 2851.580 ;
    END
  END m_axi_dma_arlen[3]
  PIN m_axi_dma_arlen[4]
    DIRECTION OUTPUT ;
    USE SIGNAL ;
    ANTENNADIFFAREA 0.708600 ;
    PORT
      LAYER Metal3 ;
        RECT 0.000 2859.580 0.400 2859.980 ;
    END
  END m_axi_dma_arlen[4]
  PIN m_axi_dma_arlen[5]
    DIRECTION OUTPUT ;
    USE SIGNAL ;
    ANTENNADIFFAREA 0.708600 ;
    PORT
      LAYER Metal3 ;
        RECT 0.000 2867.980 0.400 2868.380 ;
    END
  END m_axi_dma_arlen[5]
  PIN m_axi_dma_arlen[6]
    DIRECTION OUTPUT ;
    USE SIGNAL ;
    ANTENNADIFFAREA 0.708600 ;
    PORT
      LAYER Metal3 ;
        RECT 0.000 2876.380 0.400 2876.780 ;
    END
  END m_axi_dma_arlen[6]
  PIN m_axi_dma_arlen[7]
    DIRECTION OUTPUT ;
    USE SIGNAL ;
    ANTENNADIFFAREA 0.708600 ;
    PORT
      LAYER Metal3 ;
        RECT 0.000 2884.780 0.400 2885.180 ;
    END
  END m_axi_dma_arlen[7]
  PIN m_axi_dma_arlock
    DIRECTION OUTPUT ;
    USE SIGNAL ;
    ANTENNADIFFAREA 0.708600 ;
    PORT
      LAYER Metal3 ;
        RECT 0.000 2775.580 0.400 2775.980 ;
    END
  END m_axi_dma_arlock
  PIN m_axi_dma_arprot[0]
    DIRECTION OUTPUT ;
    USE SIGNAL ;
    ANTENNADIFFAREA 0.708600 ;
    PORT
      LAYER Metal3 ;
        RECT 0.000 2716.780 0.400 2717.180 ;
    END
  END m_axi_dma_arprot[0]
  PIN m_axi_dma_arprot[1]
    DIRECTION OUTPUT ;
    USE SIGNAL ;
    ANTENNADIFFAREA 0.708600 ;
    PORT
      LAYER Metal3 ;
        RECT 0.000 2725.180 0.400 2725.580 ;
    END
  END m_axi_dma_arprot[1]
  PIN m_axi_dma_arprot[2]
    DIRECTION OUTPUT ;
    USE SIGNAL ;
    ANTENNADIFFAREA 0.708600 ;
    PORT
      LAYER Metal3 ;
        RECT 0.000 2733.580 0.400 2733.980 ;
    END
  END m_axi_dma_arprot[2]
  PIN m_axi_dma_arready
    DIRECTION INPUT ;
    USE SIGNAL ;
    ANTENNAGATEAREA 0.180700 ;
    ANTENNADIFFAREA 2.015400 ;
    PORT
      LAYER Metal3 ;
        RECT 0.000 2699.980 0.400 2700.380 ;
    END
  END m_axi_dma_arready
  PIN m_axi_dma_arsize[0]
    DIRECTION OUTPUT ;
    USE SIGNAL ;
    ANTENNADIFFAREA 0.708600 ;
    PORT
      LAYER Metal3 ;
        RECT 0.000 2800.780 0.400 2801.180 ;
    END
  END m_axi_dma_arsize[0]
  PIN m_axi_dma_arsize[1]
    DIRECTION OUTPUT ;
    USE SIGNAL ;
    ANTENNADIFFAREA 0.708600 ;
    PORT
      LAYER Metal3 ;
        RECT 0.000 2809.180 0.400 2809.580 ;
    END
  END m_axi_dma_arsize[1]
  PIN m_axi_dma_arsize[2]
    DIRECTION OUTPUT ;
    USE SIGNAL ;
    ANTENNADIFFAREA 0.708600 ;
    PORT
      LAYER Metal3 ;
        RECT 0.000 2817.580 0.400 2817.980 ;
    END
  END m_axi_dma_arsize[2]
  PIN m_axi_dma_arvalid
    DIRECTION OUTPUT ;
    USE SIGNAL ;
    ANTENNADIFFAREA 0.708600 ;
    PORT
      LAYER Metal3 ;
        RECT 0.000 2708.380 0.400 2708.780 ;
    END
  END m_axi_dma_arvalid
  PIN m_axi_dma_awaddr[0]
    DIRECTION OUTPUT ;
    USE SIGNAL ;
    ANTENNADIFFAREA 0.708600 ;
    PORT
      LAYER Metal3 ;
        RECT 0.000 3850.780 0.400 3851.180 ;
    END
  END m_axi_dma_awaddr[0]
  PIN m_axi_dma_awaddr[10]
    DIRECTION OUTPUT ;
    USE SIGNAL ;
    ANTENNADIFFAREA 0.708600 ;
    PORT
      LAYER Metal3 ;
        RECT 0.000 3934.780 0.400 3935.180 ;
    END
  END m_axi_dma_awaddr[10]
  PIN m_axi_dma_awaddr[11]
    DIRECTION OUTPUT ;
    USE SIGNAL ;
    ANTENNADIFFAREA 0.708600 ;
    PORT
      LAYER Metal3 ;
        RECT 0.000 3943.180 0.400 3943.580 ;
    END
  END m_axi_dma_awaddr[11]
  PIN m_axi_dma_awaddr[12]
    DIRECTION OUTPUT ;
    USE SIGNAL ;
    ANTENNADIFFAREA 0.708600 ;
    PORT
      LAYER Metal3 ;
        RECT 0.000 3951.580 0.400 3951.980 ;
    END
  END m_axi_dma_awaddr[12]
  PIN m_axi_dma_awaddr[13]
    DIRECTION OUTPUT ;
    USE SIGNAL ;
    ANTENNADIFFAREA 0.708600 ;
    PORT
      LAYER Metal3 ;
        RECT 0.000 3959.980 0.400 3960.380 ;
    END
  END m_axi_dma_awaddr[13]
  PIN m_axi_dma_awaddr[14]
    DIRECTION OUTPUT ;
    USE SIGNAL ;
    ANTENNADIFFAREA 0.708600 ;
    PORT
      LAYER Metal3 ;
        RECT 0.000 3968.380 0.400 3968.780 ;
    END
  END m_axi_dma_awaddr[14]
  PIN m_axi_dma_awaddr[15]
    DIRECTION OUTPUT ;
    USE SIGNAL ;
    ANTENNADIFFAREA 0.708600 ;
    PORT
      LAYER Metal3 ;
        RECT 0.000 3976.780 0.400 3977.180 ;
    END
  END m_axi_dma_awaddr[15]
  PIN m_axi_dma_awaddr[16]
    DIRECTION OUTPUT ;
    USE SIGNAL ;
    ANTENNADIFFAREA 0.708600 ;
    PORT
      LAYER Metal3 ;
        RECT 0.000 3985.180 0.400 3985.580 ;
    END
  END m_axi_dma_awaddr[16]
  PIN m_axi_dma_awaddr[17]
    DIRECTION OUTPUT ;
    USE SIGNAL ;
    ANTENNADIFFAREA 0.708600 ;
    PORT
      LAYER Metal3 ;
        RECT 0.000 3993.580 0.400 3993.980 ;
    END
  END m_axi_dma_awaddr[17]
  PIN m_axi_dma_awaddr[18]
    DIRECTION OUTPUT ;
    USE SIGNAL ;
    ANTENNADIFFAREA 0.708600 ;
    PORT
      LAYER Metal3 ;
        RECT 0.000 4001.980 0.400 4002.380 ;
    END
  END m_axi_dma_awaddr[18]
  PIN m_axi_dma_awaddr[19]
    DIRECTION OUTPUT ;
    USE SIGNAL ;
    ANTENNADIFFAREA 0.708600 ;
    PORT
      LAYER Metal3 ;
        RECT 0.000 4010.380 0.400 4010.780 ;
    END
  END m_axi_dma_awaddr[19]
  PIN m_axi_dma_awaddr[1]
    DIRECTION OUTPUT ;
    USE SIGNAL ;
    ANTENNADIFFAREA 0.708600 ;
    PORT
      LAYER Metal3 ;
        RECT 0.000 3859.180 0.400 3859.580 ;
    END
  END m_axi_dma_awaddr[1]
  PIN m_axi_dma_awaddr[20]
    DIRECTION OUTPUT ;
    USE SIGNAL ;
    ANTENNADIFFAREA 0.708600 ;
    PORT
      LAYER Metal3 ;
        RECT 0.000 4018.780 0.400 4019.180 ;
    END
  END m_axi_dma_awaddr[20]
  PIN m_axi_dma_awaddr[21]
    DIRECTION OUTPUT ;
    USE SIGNAL ;
    ANTENNADIFFAREA 0.708600 ;
    PORT
      LAYER Metal3 ;
        RECT 0.000 4027.180 0.400 4027.580 ;
    END
  END m_axi_dma_awaddr[21]
  PIN m_axi_dma_awaddr[22]
    DIRECTION OUTPUT ;
    USE SIGNAL ;
    ANTENNADIFFAREA 0.708600 ;
    PORT
      LAYER Metal3 ;
        RECT 0.000 4035.580 0.400 4035.980 ;
    END
  END m_axi_dma_awaddr[22]
  PIN m_axi_dma_awaddr[23]
    DIRECTION OUTPUT ;
    USE SIGNAL ;
    ANTENNADIFFAREA 0.708600 ;
    PORT
      LAYER Metal3 ;
        RECT 0.000 4043.980 0.400 4044.380 ;
    END
  END m_axi_dma_awaddr[23]
  PIN m_axi_dma_awaddr[24]
    DIRECTION OUTPUT ;
    USE SIGNAL ;
    ANTENNADIFFAREA 0.708600 ;
    PORT
      LAYER Metal3 ;
        RECT 0.000 4052.380 0.400 4052.780 ;
    END
  END m_axi_dma_awaddr[24]
  PIN m_axi_dma_awaddr[25]
    DIRECTION OUTPUT ;
    USE SIGNAL ;
    ANTENNADIFFAREA 0.708600 ;
    PORT
      LAYER Metal3 ;
        RECT 0.000 4060.780 0.400 4061.180 ;
    END
  END m_axi_dma_awaddr[25]
  PIN m_axi_dma_awaddr[26]
    DIRECTION OUTPUT ;
    USE SIGNAL ;
    ANTENNADIFFAREA 0.708600 ;
    PORT
      LAYER Metal3 ;
        RECT 0.000 4069.180 0.400 4069.580 ;
    END
  END m_axi_dma_awaddr[26]
  PIN m_axi_dma_awaddr[27]
    DIRECTION OUTPUT ;
    USE SIGNAL ;
    ANTENNADIFFAREA 0.708600 ;
    PORT
      LAYER Metal3 ;
        RECT 0.000 4077.580 0.400 4077.980 ;
    END
  END m_axi_dma_awaddr[27]
  PIN m_axi_dma_awaddr[28]
    DIRECTION OUTPUT ;
    USE SIGNAL ;
    ANTENNADIFFAREA 0.708600 ;
    PORT
      LAYER Metal3 ;
        RECT 0.000 4085.980 0.400 4086.380 ;
    END
  END m_axi_dma_awaddr[28]
  PIN m_axi_dma_awaddr[29]
    DIRECTION OUTPUT ;
    USE SIGNAL ;
    ANTENNADIFFAREA 0.708600 ;
    PORT
      LAYER Metal3 ;
        RECT 0.000 4094.380 0.400 4094.780 ;
    END
  END m_axi_dma_awaddr[29]
  PIN m_axi_dma_awaddr[2]
    DIRECTION OUTPUT ;
    USE SIGNAL ;
    ANTENNADIFFAREA 0.708600 ;
    PORT
      LAYER Metal3 ;
        RECT 0.000 3867.580 0.400 3867.980 ;
    END
  END m_axi_dma_awaddr[2]
  PIN m_axi_dma_awaddr[30]
    DIRECTION OUTPUT ;
    USE SIGNAL ;
    ANTENNADIFFAREA 0.708600 ;
    PORT
      LAYER Metal3 ;
        RECT 0.000 4102.780 0.400 4103.180 ;
    END
  END m_axi_dma_awaddr[30]
  PIN m_axi_dma_awaddr[31]
    DIRECTION OUTPUT ;
    USE SIGNAL ;
    ANTENNADIFFAREA 0.708600 ;
    PORT
      LAYER Metal3 ;
        RECT 0.000 4111.180 0.400 4111.580 ;
    END
  END m_axi_dma_awaddr[31]
  PIN m_axi_dma_awaddr[3]
    DIRECTION OUTPUT ;
    USE SIGNAL ;
    ANTENNADIFFAREA 0.708600 ;
    PORT
      LAYER Metal3 ;
        RECT 0.000 3875.980 0.400 3876.380 ;
    END
  END m_axi_dma_awaddr[3]
  PIN m_axi_dma_awaddr[4]
    DIRECTION OUTPUT ;
    USE SIGNAL ;
    ANTENNADIFFAREA 0.708600 ;
    PORT
      LAYER Metal3 ;
        RECT 0.000 3884.380 0.400 3884.780 ;
    END
  END m_axi_dma_awaddr[4]
  PIN m_axi_dma_awaddr[5]
    DIRECTION OUTPUT ;
    USE SIGNAL ;
    ANTENNADIFFAREA 0.708600 ;
    PORT
      LAYER Metal3 ;
        RECT 0.000 3892.780 0.400 3893.180 ;
    END
  END m_axi_dma_awaddr[5]
  PIN m_axi_dma_awaddr[6]
    DIRECTION OUTPUT ;
    USE SIGNAL ;
    ANTENNADIFFAREA 0.708600 ;
    PORT
      LAYER Metal3 ;
        RECT 0.000 3901.180 0.400 3901.580 ;
    END
  END m_axi_dma_awaddr[6]
  PIN m_axi_dma_awaddr[7]
    DIRECTION OUTPUT ;
    USE SIGNAL ;
    ANTENNADIFFAREA 0.708600 ;
    PORT
      LAYER Metal3 ;
        RECT 0.000 3909.580 0.400 3909.980 ;
    END
  END m_axi_dma_awaddr[7]
  PIN m_axi_dma_awaddr[8]
    DIRECTION OUTPUT ;
    USE SIGNAL ;
    ANTENNADIFFAREA 0.708600 ;
    PORT
      LAYER Metal3 ;
        RECT 0.000 3917.980 0.400 3918.380 ;
    END
  END m_axi_dma_awaddr[8]
  PIN m_axi_dma_awaddr[9]
    DIRECTION OUTPUT ;
    USE SIGNAL ;
    ANTENNADIFFAREA 0.708600 ;
    PORT
      LAYER Metal3 ;
        RECT 0.000 3926.380 0.400 3926.780 ;
    END
  END m_axi_dma_awaddr[9]
  PIN m_axi_dma_awburst[0]
    DIRECTION OUTPUT ;
    USE SIGNAL ;
    ANTENNADIFFAREA 0.708600 ;
    PORT
      LAYER Metal3 ;
        RECT 0.000 3741.580 0.400 3741.980 ;
    END
  END m_axi_dma_awburst[0]
  PIN m_axi_dma_awburst[1]
    DIRECTION OUTPUT ;
    USE SIGNAL ;
    ANTENNADIFFAREA 0.708600 ;
    PORT
      LAYER Metal3 ;
        RECT 0.000 3749.980 0.400 3750.380 ;
    END
  END m_axi_dma_awburst[1]
  PIN m_axi_dma_awcache[0]
    DIRECTION OUTPUT ;
    USE SIGNAL ;
    ANTENNADIFFAREA 0.708600 ;
    PORT
      LAYER Metal3 ;
        RECT 0.000 3699.580 0.400 3699.980 ;
    END
  END m_axi_dma_awcache[0]
  PIN m_axi_dma_awcache[1]
    DIRECTION OUTPUT ;
    USE SIGNAL ;
    ANTENNADIFFAREA 0.708600 ;
    PORT
      LAYER Metal3 ;
        RECT 0.000 3707.980 0.400 3708.380 ;
    END
  END m_axi_dma_awcache[1]
  PIN m_axi_dma_awcache[2]
    DIRECTION OUTPUT ;
    USE SIGNAL ;
    ANTENNADIFFAREA 0.708600 ;
    PORT
      LAYER Metal3 ;
        RECT 0.000 3716.380 0.400 3716.780 ;
    END
  END m_axi_dma_awcache[2]
  PIN m_axi_dma_awcache[3]
    DIRECTION OUTPUT ;
    USE SIGNAL ;
    ANTENNADIFFAREA 0.708600 ;
    PORT
      LAYER Metal3 ;
        RECT 0.000 3724.780 0.400 3725.180 ;
    END
  END m_axi_dma_awcache[3]
  PIN m_axi_dma_awid[0]
    DIRECTION OUTPUT ;
    USE SIGNAL ;
    ANTENNADIFFAREA 0.708600 ;
    PORT
      LAYER Metal3 ;
        RECT 0.000 4119.580 0.400 4119.980 ;
    END
  END m_axi_dma_awid[0]
  PIN m_axi_dma_awid[1]
    DIRECTION OUTPUT ;
    USE SIGNAL ;
    ANTENNADIFFAREA 0.299200 ;
    PORT
      LAYER Metal3 ;
        RECT 0.000 4127.980 0.400 4128.380 ;
    END
  END m_axi_dma_awid[1]
  PIN m_axi_dma_awid[2]
    DIRECTION OUTPUT ;
    USE SIGNAL ;
    ANTENNADIFFAREA 0.299200 ;
    PORT
      LAYER Metal3 ;
        RECT 0.000 4136.380 0.400 4136.780 ;
    END
  END m_axi_dma_awid[2]
  PIN m_axi_dma_awid[3]
    DIRECTION OUTPUT ;
    USE SIGNAL ;
    ANTENNADIFFAREA 0.299200 ;
    PORT
      LAYER Metal3 ;
        RECT 0.000 4144.780 0.400 4145.180 ;
    END
  END m_axi_dma_awid[3]
  PIN m_axi_dma_awid[4]
    DIRECTION OUTPUT ;
    USE SIGNAL ;
    ANTENNADIFFAREA 0.299200 ;
    PORT
      LAYER Metal3 ;
        RECT 0.000 4153.180 0.400 4153.580 ;
    END
  END m_axi_dma_awid[4]
  PIN m_axi_dma_awid[5]
    DIRECTION OUTPUT ;
    USE SIGNAL ;
    ANTENNADIFFAREA 0.299200 ;
    PORT
      LAYER Metal3 ;
        RECT 0.000 4161.580 0.400 4161.980 ;
    END
  END m_axi_dma_awid[5]
  PIN m_axi_dma_awid[6]
    DIRECTION OUTPUT ;
    USE SIGNAL ;
    ANTENNADIFFAREA 0.299200 ;
    PORT
      LAYER Metal3 ;
        RECT 0.000 4169.980 0.400 4170.380 ;
    END
  END m_axi_dma_awid[6]
  PIN m_axi_dma_awid[7]
    DIRECTION OUTPUT ;
    USE SIGNAL ;
    ANTENNADIFFAREA 0.299200 ;
    PORT
      LAYER Metal3 ;
        RECT 0.000 4178.380 0.400 4178.780 ;
    END
  END m_axi_dma_awid[7]
  PIN m_axi_dma_awlen[0]
    DIRECTION OUTPUT ;
    USE SIGNAL ;
    ANTENNADIFFAREA 0.708600 ;
    PORT
      LAYER Metal3 ;
        RECT 0.000 3783.580 0.400 3783.980 ;
    END
  END m_axi_dma_awlen[0]
  PIN m_axi_dma_awlen[1]
    DIRECTION OUTPUT ;
    USE SIGNAL ;
    ANTENNADIFFAREA 0.708600 ;
    PORT
      LAYER Metal3 ;
        RECT 0.000 3791.980 0.400 3792.380 ;
    END
  END m_axi_dma_awlen[1]
  PIN m_axi_dma_awlen[2]
    DIRECTION OUTPUT ;
    USE SIGNAL ;
    ANTENNADIFFAREA 0.708600 ;
    PORT
      LAYER Metal3 ;
        RECT 0.000 3800.380 0.400 3800.780 ;
    END
  END m_axi_dma_awlen[2]
  PIN m_axi_dma_awlen[3]
    DIRECTION OUTPUT ;
    USE SIGNAL ;
    ANTENNADIFFAREA 0.708600 ;
    PORT
      LAYER Metal3 ;
        RECT 0.000 3808.780 0.400 3809.180 ;
    END
  END m_axi_dma_awlen[3]
  PIN m_axi_dma_awlen[4]
    DIRECTION OUTPUT ;
    USE SIGNAL ;
    ANTENNADIFFAREA 0.708600 ;
    PORT
      LAYER Metal3 ;
        RECT 0.000 3817.180 0.400 3817.580 ;
    END
  END m_axi_dma_awlen[4]
  PIN m_axi_dma_awlen[5]
    DIRECTION OUTPUT ;
    USE SIGNAL ;
    ANTENNADIFFAREA 0.708600 ;
    PORT
      LAYER Metal3 ;
        RECT 0.000 3825.580 0.400 3825.980 ;
    END
  END m_axi_dma_awlen[5]
  PIN m_axi_dma_awlen[6]
    DIRECTION OUTPUT ;
    USE SIGNAL ;
    ANTENNADIFFAREA 0.708600 ;
    PORT
      LAYER Metal3 ;
        RECT 0.000 3833.980 0.400 3834.380 ;
    END
  END m_axi_dma_awlen[6]
  PIN m_axi_dma_awlen[7]
    DIRECTION OUTPUT ;
    USE SIGNAL ;
    ANTENNADIFFAREA 0.708600 ;
    PORT
      LAYER Metal3 ;
        RECT 0.000 3842.380 0.400 3842.780 ;
    END
  END m_axi_dma_awlen[7]
  PIN m_axi_dma_awlock
    DIRECTION OUTPUT ;
    USE SIGNAL ;
    ANTENNADIFFAREA 0.708600 ;
    PORT
      LAYER Metal3 ;
        RECT 0.000 3733.180 0.400 3733.580 ;
    END
  END m_axi_dma_awlock
  PIN m_axi_dma_awprot[0]
    DIRECTION OUTPUT ;
    USE SIGNAL ;
    ANTENNADIFFAREA 0.708600 ;
    PORT
      LAYER Metal3 ;
        RECT 0.000 3674.380 0.400 3674.780 ;
    END
  END m_axi_dma_awprot[0]
  PIN m_axi_dma_awprot[1]
    DIRECTION OUTPUT ;
    USE SIGNAL ;
    ANTENNADIFFAREA 0.708600 ;
    PORT
      LAYER Metal3 ;
        RECT 0.000 3682.780 0.400 3683.180 ;
    END
  END m_axi_dma_awprot[1]
  PIN m_axi_dma_awprot[2]
    DIRECTION OUTPUT ;
    USE SIGNAL ;
    ANTENNADIFFAREA 0.708600 ;
    PORT
      LAYER Metal3 ;
        RECT 0.000 3691.180 0.400 3691.580 ;
    END
  END m_axi_dma_awprot[2]
  PIN m_axi_dma_awready
    DIRECTION INPUT ;
    USE SIGNAL ;
    ANTENNAGATEAREA 0.180700 ;
    ANTENNADIFFAREA 2.015400 ;
    PORT
      LAYER Metal3 ;
        RECT 0.000 3657.580 0.400 3657.980 ;
    END
  END m_axi_dma_awready
  PIN m_axi_dma_awsize[0]
    DIRECTION OUTPUT ;
    USE SIGNAL ;
    ANTENNADIFFAREA 0.708600 ;
    PORT
      LAYER Metal3 ;
        RECT 0.000 3758.380 0.400 3758.780 ;
    END
  END m_axi_dma_awsize[0]
  PIN m_axi_dma_awsize[1]
    DIRECTION OUTPUT ;
    USE SIGNAL ;
    ANTENNADIFFAREA 0.708600 ;
    PORT
      LAYER Metal3 ;
        RECT 0.000 3766.780 0.400 3767.180 ;
    END
  END m_axi_dma_awsize[1]
  PIN m_axi_dma_awsize[2]
    DIRECTION OUTPUT ;
    USE SIGNAL ;
    ANTENNADIFFAREA 0.708600 ;
    PORT
      LAYER Metal3 ;
        RECT 0.000 3775.180 0.400 3775.580 ;
    END
  END m_axi_dma_awsize[2]
  PIN m_axi_dma_awvalid
    DIRECTION OUTPUT ;
    USE SIGNAL ;
    ANTENNADIFFAREA 0.708600 ;
    PORT
      LAYER Metal3 ;
        RECT 0.000 3665.980 0.400 3666.380 ;
    END
  END m_axi_dma_awvalid
  PIN m_axi_dma_bid[0]
    DIRECTION INPUT ;
    USE SIGNAL ;
    PORT
      LAYER Metal3 ;
        RECT 0.000 3262.780 0.400 3263.180 ;
    END
  END m_axi_dma_bid[0]
  PIN m_axi_dma_bid[1]
    DIRECTION INPUT ;
    USE SIGNAL ;
    PORT
      LAYER Metal3 ;
        RECT 0.000 3271.180 0.400 3271.580 ;
    END
  END m_axi_dma_bid[1]
  PIN m_axi_dma_bid[2]
    DIRECTION INPUT ;
    USE SIGNAL ;
    PORT
      LAYER Metal3 ;
        RECT 0.000 3279.580 0.400 3279.980 ;
    END
  END m_axi_dma_bid[2]
  PIN m_axi_dma_bid[3]
    DIRECTION INPUT ;
    USE SIGNAL ;
    PORT
      LAYER Metal3 ;
        RECT 0.000 3287.980 0.400 3288.380 ;
    END
  END m_axi_dma_bid[3]
  PIN m_axi_dma_bid[4]
    DIRECTION INPUT ;
    USE SIGNAL ;
    PORT
      LAYER Metal3 ;
        RECT 0.000 3296.380 0.400 3296.780 ;
    END
  END m_axi_dma_bid[4]
  PIN m_axi_dma_bid[5]
    DIRECTION INPUT ;
    USE SIGNAL ;
    PORT
      LAYER Metal3 ;
        RECT 0.000 3304.780 0.400 3305.180 ;
    END
  END m_axi_dma_bid[5]
  PIN m_axi_dma_bid[6]
    DIRECTION INPUT ;
    USE SIGNAL ;
    PORT
      LAYER Metal3 ;
        RECT 0.000 3313.180 0.400 3313.580 ;
    END
  END m_axi_dma_bid[6]
  PIN m_axi_dma_bid[7]
    DIRECTION INPUT ;
    USE SIGNAL ;
    PORT
      LAYER Metal3 ;
        RECT 0.000 3321.580 0.400 3321.980 ;
    END
  END m_axi_dma_bid[7]
  PIN m_axi_dma_bready
    DIRECTION OUTPUT ;
    USE SIGNAL ;
    ANTENNADIFFAREA 0.708600 ;
    PORT
      LAYER Metal3 ;
        RECT 0.000 3229.180 0.400 3229.580 ;
    END
  END m_axi_dma_bready
  PIN m_axi_dma_bresp[0]
    DIRECTION INPUT ;
    USE SIGNAL ;
    ANTENNAGATEAREA 0.180700 ;
    ANTENNADIFFAREA 2.015400 ;
    PORT
      LAYER Metal3 ;
        RECT 0.000 3245.980 0.400 3246.380 ;
    END
  END m_axi_dma_bresp[0]
  PIN m_axi_dma_bresp[1]
    DIRECTION INPUT ;
    USE SIGNAL ;
    ANTENNAGATEAREA 0.180700 ;
    ANTENNADIFFAREA 2.015400 ;
    PORT
      LAYER Metal3 ;
        RECT 0.000 3254.380 0.400 3254.780 ;
    END
  END m_axi_dma_bresp[1]
  PIN m_axi_dma_bvalid
    DIRECTION INPUT ;
    USE SIGNAL ;
    ANTENNAGATEAREA 0.180700 ;
    ANTENNADIFFAREA 2.015400 ;
    PORT
      LAYER Metal3 ;
        RECT 0.000 3237.580 0.400 3237.980 ;
    END
  END m_axi_dma_bvalid
  PIN m_axi_dma_rdata[0]
    DIRECTION INPUT ;
    USE SIGNAL ;
    ANTENNAGATEAREA 0.180700 ;
    ANTENNADIFFAREA 2.015400 ;
    PORT
      LAYER Metal3 ;
        RECT 0.000 2363.980 0.400 2364.380 ;
    END
  END m_axi_dma_rdata[0]
  PIN m_axi_dma_rdata[10]
    DIRECTION INPUT ;
    USE SIGNAL ;
    ANTENNAGATEAREA 0.180700 ;
    ANTENNADIFFAREA 2.015400 ;
    PORT
      LAYER Metal3 ;
        RECT 0.000 2447.980 0.400 2448.380 ;
    END
  END m_axi_dma_rdata[10]
  PIN m_axi_dma_rdata[11]
    DIRECTION INPUT ;
    USE SIGNAL ;
    ANTENNAGATEAREA 0.180700 ;
    ANTENNADIFFAREA 2.015400 ;
    PORT
      LAYER Metal3 ;
        RECT 0.000 2456.380 0.400 2456.780 ;
    END
  END m_axi_dma_rdata[11]
  PIN m_axi_dma_rdata[12]
    DIRECTION INPUT ;
    USE SIGNAL ;
    ANTENNAGATEAREA 0.180700 ;
    ANTENNADIFFAREA 2.015400 ;
    PORT
      LAYER Metal3 ;
        RECT 0.000 2464.780 0.400 2465.180 ;
    END
  END m_axi_dma_rdata[12]
  PIN m_axi_dma_rdata[13]
    DIRECTION INPUT ;
    USE SIGNAL ;
    ANTENNAGATEAREA 0.180700 ;
    ANTENNADIFFAREA 2.015400 ;
    PORT
      LAYER Metal3 ;
        RECT 0.000 2473.180 0.400 2473.580 ;
    END
  END m_axi_dma_rdata[13]
  PIN m_axi_dma_rdata[14]
    DIRECTION INPUT ;
    USE SIGNAL ;
    ANTENNAGATEAREA 0.180700 ;
    ANTENNADIFFAREA 2.015400 ;
    PORT
      LAYER Metal3 ;
        RECT 0.000 2481.580 0.400 2481.980 ;
    END
  END m_axi_dma_rdata[14]
  PIN m_axi_dma_rdata[15]
    DIRECTION INPUT ;
    USE SIGNAL ;
    ANTENNAGATEAREA 0.180700 ;
    ANTENNADIFFAREA 2.015400 ;
    PORT
      LAYER Metal3 ;
        RECT 0.000 2489.980 0.400 2490.380 ;
    END
  END m_axi_dma_rdata[15]
  PIN m_axi_dma_rdata[16]
    DIRECTION INPUT ;
    USE SIGNAL ;
    ANTENNAGATEAREA 0.180700 ;
    ANTENNADIFFAREA 2.015400 ;
    PORT
      LAYER Metal3 ;
        RECT 0.000 2498.380 0.400 2498.780 ;
    END
  END m_axi_dma_rdata[16]
  PIN m_axi_dma_rdata[17]
    DIRECTION INPUT ;
    USE SIGNAL ;
    ANTENNAGATEAREA 0.180700 ;
    ANTENNADIFFAREA 2.015400 ;
    PORT
      LAYER Metal3 ;
        RECT 0.000 2506.780 0.400 2507.180 ;
    END
  END m_axi_dma_rdata[17]
  PIN m_axi_dma_rdata[18]
    DIRECTION INPUT ;
    USE SIGNAL ;
    ANTENNAGATEAREA 0.180700 ;
    ANTENNADIFFAREA 2.015400 ;
    PORT
      LAYER Metal3 ;
        RECT 0.000 2515.180 0.400 2515.580 ;
    END
  END m_axi_dma_rdata[18]
  PIN m_axi_dma_rdata[19]
    DIRECTION INPUT ;
    USE SIGNAL ;
    ANTENNAGATEAREA 0.180700 ;
    ANTENNADIFFAREA 2.015400 ;
    PORT
      LAYER Metal3 ;
        RECT 0.000 2523.580 0.400 2523.980 ;
    END
  END m_axi_dma_rdata[19]
  PIN m_axi_dma_rdata[1]
    DIRECTION INPUT ;
    USE SIGNAL ;
    ANTENNAGATEAREA 0.180700 ;
    ANTENNADIFFAREA 2.015400 ;
    PORT
      LAYER Metal3 ;
        RECT 0.000 2372.380 0.400 2372.780 ;
    END
  END m_axi_dma_rdata[1]
  PIN m_axi_dma_rdata[20]
    DIRECTION INPUT ;
    USE SIGNAL ;
    ANTENNAGATEAREA 0.180700 ;
    ANTENNADIFFAREA 2.015400 ;
    PORT
      LAYER Metal3 ;
        RECT 0.000 2531.980 0.400 2532.380 ;
    END
  END m_axi_dma_rdata[20]
  PIN m_axi_dma_rdata[21]
    DIRECTION INPUT ;
    USE SIGNAL ;
    ANTENNAGATEAREA 0.180700 ;
    ANTENNADIFFAREA 2.015400 ;
    PORT
      LAYER Metal3 ;
        RECT 0.000 2540.380 0.400 2540.780 ;
    END
  END m_axi_dma_rdata[21]
  PIN m_axi_dma_rdata[22]
    DIRECTION INPUT ;
    USE SIGNAL ;
    ANTENNAGATEAREA 0.180700 ;
    ANTENNADIFFAREA 2.015400 ;
    PORT
      LAYER Metal3 ;
        RECT 0.000 2548.780 0.400 2549.180 ;
    END
  END m_axi_dma_rdata[22]
  PIN m_axi_dma_rdata[23]
    DIRECTION INPUT ;
    USE SIGNAL ;
    ANTENNAGATEAREA 0.180700 ;
    ANTENNADIFFAREA 2.015400 ;
    PORT
      LAYER Metal3 ;
        RECT 0.000 2557.180 0.400 2557.580 ;
    END
  END m_axi_dma_rdata[23]
  PIN m_axi_dma_rdata[24]
    DIRECTION INPUT ;
    USE SIGNAL ;
    ANTENNAGATEAREA 0.180700 ;
    ANTENNADIFFAREA 2.015400 ;
    PORT
      LAYER Metal3 ;
        RECT 0.000 2565.580 0.400 2565.980 ;
    END
  END m_axi_dma_rdata[24]
  PIN m_axi_dma_rdata[25]
    DIRECTION INPUT ;
    USE SIGNAL ;
    ANTENNAGATEAREA 0.180700 ;
    ANTENNADIFFAREA 2.015400 ;
    PORT
      LAYER Metal3 ;
        RECT 0.000 2573.980 0.400 2574.380 ;
    END
  END m_axi_dma_rdata[25]
  PIN m_axi_dma_rdata[26]
    DIRECTION INPUT ;
    USE SIGNAL ;
    ANTENNAGATEAREA 0.180700 ;
    ANTENNADIFFAREA 2.015400 ;
    PORT
      LAYER Metal3 ;
        RECT 0.000 2582.380 0.400 2582.780 ;
    END
  END m_axi_dma_rdata[26]
  PIN m_axi_dma_rdata[27]
    DIRECTION INPUT ;
    USE SIGNAL ;
    ANTENNAGATEAREA 0.180700 ;
    ANTENNADIFFAREA 2.015400 ;
    PORT
      LAYER Metal3 ;
        RECT 0.000 2590.780 0.400 2591.180 ;
    END
  END m_axi_dma_rdata[27]
  PIN m_axi_dma_rdata[28]
    DIRECTION INPUT ;
    USE SIGNAL ;
    ANTENNAGATEAREA 0.180700 ;
    ANTENNADIFFAREA 2.015400 ;
    PORT
      LAYER Metal3 ;
        RECT 0.000 2599.180 0.400 2599.580 ;
    END
  END m_axi_dma_rdata[28]
  PIN m_axi_dma_rdata[29]
    DIRECTION INPUT ;
    USE SIGNAL ;
    ANTENNAGATEAREA 0.180700 ;
    ANTENNADIFFAREA 2.015400 ;
    PORT
      LAYER Metal3 ;
        RECT 0.000 2607.580 0.400 2607.980 ;
    END
  END m_axi_dma_rdata[29]
  PIN m_axi_dma_rdata[2]
    DIRECTION INPUT ;
    USE SIGNAL ;
    ANTENNAGATEAREA 0.180700 ;
    ANTENNADIFFAREA 2.015400 ;
    PORT
      LAYER Metal3 ;
        RECT 0.000 2380.780 0.400 2381.180 ;
    END
  END m_axi_dma_rdata[2]
  PIN m_axi_dma_rdata[30]
    DIRECTION INPUT ;
    USE SIGNAL ;
    ANTENNAGATEAREA 0.180700 ;
    ANTENNADIFFAREA 2.015400 ;
    PORT
      LAYER Metal3 ;
        RECT 0.000 2615.980 0.400 2616.380 ;
    END
  END m_axi_dma_rdata[30]
  PIN m_axi_dma_rdata[31]
    DIRECTION INPUT ;
    USE SIGNAL ;
    ANTENNAGATEAREA 0.180700 ;
    ANTENNADIFFAREA 2.015400 ;
    PORT
      LAYER Metal3 ;
        RECT 0.000 2624.380 0.400 2624.780 ;
    END
  END m_axi_dma_rdata[31]
  PIN m_axi_dma_rdata[3]
    DIRECTION INPUT ;
    USE SIGNAL ;
    ANTENNAGATEAREA 0.180700 ;
    ANTENNADIFFAREA 2.015400 ;
    PORT
      LAYER Metal3 ;
        RECT 0.000 2389.180 0.400 2389.580 ;
    END
  END m_axi_dma_rdata[3]
  PIN m_axi_dma_rdata[4]
    DIRECTION INPUT ;
    USE SIGNAL ;
    ANTENNAGATEAREA 0.180700 ;
    ANTENNADIFFAREA 2.015400 ;
    PORT
      LAYER Metal3 ;
        RECT 0.000 2397.580 0.400 2397.980 ;
    END
  END m_axi_dma_rdata[4]
  PIN m_axi_dma_rdata[5]
    DIRECTION INPUT ;
    USE SIGNAL ;
    ANTENNAGATEAREA 0.180700 ;
    ANTENNADIFFAREA 2.015400 ;
    PORT
      LAYER Metal3 ;
        RECT 0.000 2405.980 0.400 2406.380 ;
    END
  END m_axi_dma_rdata[5]
  PIN m_axi_dma_rdata[6]
    DIRECTION INPUT ;
    USE SIGNAL ;
    ANTENNAGATEAREA 0.180700 ;
    ANTENNADIFFAREA 2.015400 ;
    PORT
      LAYER Metal3 ;
        RECT 0.000 2414.380 0.400 2414.780 ;
    END
  END m_axi_dma_rdata[6]
  PIN m_axi_dma_rdata[7]
    DIRECTION INPUT ;
    USE SIGNAL ;
    ANTENNAGATEAREA 0.180700 ;
    ANTENNADIFFAREA 2.015400 ;
    PORT
      LAYER Metal3 ;
        RECT 0.000 2422.780 0.400 2423.180 ;
    END
  END m_axi_dma_rdata[7]
  PIN m_axi_dma_rdata[8]
    DIRECTION INPUT ;
    USE SIGNAL ;
    ANTENNAGATEAREA 0.180700 ;
    ANTENNADIFFAREA 2.015400 ;
    PORT
      LAYER Metal3 ;
        RECT 0.000 2431.180 0.400 2431.580 ;
    END
  END m_axi_dma_rdata[8]
  PIN m_axi_dma_rdata[9]
    DIRECTION INPUT ;
    USE SIGNAL ;
    ANTENNAGATEAREA 0.180700 ;
    ANTENNADIFFAREA 2.015400 ;
    PORT
      LAYER Metal3 ;
        RECT 0.000 2439.580 0.400 2439.980 ;
    END
  END m_axi_dma_rdata[9]
  PIN m_axi_dma_rid[0]
    DIRECTION INPUT ;
    USE SIGNAL ;
    PORT
      LAYER Metal3 ;
        RECT 0.000 2632.780 0.400 2633.180 ;
    END
  END m_axi_dma_rid[0]
  PIN m_axi_dma_rid[1]
    DIRECTION INPUT ;
    USE SIGNAL ;
    PORT
      LAYER Metal3 ;
        RECT 0.000 2641.180 0.400 2641.580 ;
    END
  END m_axi_dma_rid[1]
  PIN m_axi_dma_rid[2]
    DIRECTION INPUT ;
    USE SIGNAL ;
    PORT
      LAYER Metal3 ;
        RECT 0.000 2649.580 0.400 2649.980 ;
    END
  END m_axi_dma_rid[2]
  PIN m_axi_dma_rid[3]
    DIRECTION INPUT ;
    USE SIGNAL ;
    PORT
      LAYER Metal3 ;
        RECT 0.000 2657.980 0.400 2658.380 ;
    END
  END m_axi_dma_rid[3]
  PIN m_axi_dma_rid[4]
    DIRECTION INPUT ;
    USE SIGNAL ;
    PORT
      LAYER Metal3 ;
        RECT 0.000 2666.380 0.400 2666.780 ;
    END
  END m_axi_dma_rid[4]
  PIN m_axi_dma_rid[5]
    DIRECTION INPUT ;
    USE SIGNAL ;
    PORT
      LAYER Metal3 ;
        RECT 0.000 2674.780 0.400 2675.180 ;
    END
  END m_axi_dma_rid[5]
  PIN m_axi_dma_rid[6]
    DIRECTION INPUT ;
    USE SIGNAL ;
    PORT
      LAYER Metal3 ;
        RECT 0.000 2683.180 0.400 2683.580 ;
    END
  END m_axi_dma_rid[6]
  PIN m_axi_dma_rid[7]
    DIRECTION INPUT ;
    USE SIGNAL ;
    PORT
      LAYER Metal3 ;
        RECT 0.000 2691.580 0.400 2691.980 ;
    END
  END m_axi_dma_rid[7]
  PIN m_axi_dma_rlast
    DIRECTION INPUT ;
    USE SIGNAL ;
    ANTENNAGATEAREA 0.180700 ;
    ANTENNADIFFAREA 2.015400 ;
    PORT
      LAYER Metal3 ;
        RECT 0.000 2338.780 0.400 2339.180 ;
    END
  END m_axi_dma_rlast
  PIN m_axi_dma_rready
    DIRECTION OUTPUT ;
    USE SIGNAL ;
    ANTENNADIFFAREA 0.708600 ;
    PORT
      LAYER Metal3 ;
        RECT 0.000 2321.980 0.400 2322.380 ;
    END
  END m_axi_dma_rready
  PIN m_axi_dma_rresp[0]
    DIRECTION INPUT ;
    USE SIGNAL ;
    ANTENNAGATEAREA 0.180700 ;
    ANTENNADIFFAREA 2.015400 ;
    PORT
      LAYER Metal3 ;
        RECT 0.000 2347.180 0.400 2347.580 ;
    END
  END m_axi_dma_rresp[0]
  PIN m_axi_dma_rresp[1]
    DIRECTION INPUT ;
    USE SIGNAL ;
    ANTENNAGATEAREA 0.180700 ;
    ANTENNADIFFAREA 2.015400 ;
    PORT
      LAYER Metal3 ;
        RECT 0.000 2355.580 0.400 2355.980 ;
    END
  END m_axi_dma_rresp[1]
  PIN m_axi_dma_rvalid
    DIRECTION INPUT ;
    USE SIGNAL ;
    ANTENNAGATEAREA 0.180700 ;
    ANTENNADIFFAREA 2.015400 ;
    PORT
      LAYER Metal3 ;
        RECT 0.000 2330.380 0.400 2330.780 ;
    END
  END m_axi_dma_rvalid
  PIN m_axi_dma_wdata[0]
    DIRECTION OUTPUT ;
    USE SIGNAL ;
    ANTENNADIFFAREA 0.708600 ;
    PORT
      LAYER Metal3 ;
        RECT 0.000 3388.780 0.400 3389.180 ;
    END
  END m_axi_dma_wdata[0]
  PIN m_axi_dma_wdata[10]
    DIRECTION OUTPUT ;
    USE SIGNAL ;
    ANTENNADIFFAREA 0.708600 ;
    PORT
      LAYER Metal3 ;
        RECT 0.000 3472.780 0.400 3473.180 ;
    END
  END m_axi_dma_wdata[10]
  PIN m_axi_dma_wdata[11]
    DIRECTION OUTPUT ;
    USE SIGNAL ;
    ANTENNADIFFAREA 0.708600 ;
    PORT
      LAYER Metal3 ;
        RECT 0.000 3481.180 0.400 3481.580 ;
    END
  END m_axi_dma_wdata[11]
  PIN m_axi_dma_wdata[12]
    DIRECTION OUTPUT ;
    USE SIGNAL ;
    ANTENNADIFFAREA 0.708600 ;
    PORT
      LAYER Metal3 ;
        RECT 0.000 3489.580 0.400 3489.980 ;
    END
  END m_axi_dma_wdata[12]
  PIN m_axi_dma_wdata[13]
    DIRECTION OUTPUT ;
    USE SIGNAL ;
    ANTENNADIFFAREA 0.708600 ;
    PORT
      LAYER Metal3 ;
        RECT 0.000 3497.980 0.400 3498.380 ;
    END
  END m_axi_dma_wdata[13]
  PIN m_axi_dma_wdata[14]
    DIRECTION OUTPUT ;
    USE SIGNAL ;
    ANTENNADIFFAREA 0.708600 ;
    PORT
      LAYER Metal3 ;
        RECT 0.000 3506.380 0.400 3506.780 ;
    END
  END m_axi_dma_wdata[14]
  PIN m_axi_dma_wdata[15]
    DIRECTION OUTPUT ;
    USE SIGNAL ;
    ANTENNADIFFAREA 0.708600 ;
    PORT
      LAYER Metal3 ;
        RECT 0.000 3514.780 0.400 3515.180 ;
    END
  END m_axi_dma_wdata[15]
  PIN m_axi_dma_wdata[16]
    DIRECTION OUTPUT ;
    USE SIGNAL ;
    ANTENNADIFFAREA 0.708600 ;
    PORT
      LAYER Metal3 ;
        RECT 0.000 3523.180 0.400 3523.580 ;
    END
  END m_axi_dma_wdata[16]
  PIN m_axi_dma_wdata[17]
    DIRECTION OUTPUT ;
    USE SIGNAL ;
    ANTENNADIFFAREA 0.708600 ;
    PORT
      LAYER Metal3 ;
        RECT 0.000 3531.580 0.400 3531.980 ;
    END
  END m_axi_dma_wdata[17]
  PIN m_axi_dma_wdata[18]
    DIRECTION OUTPUT ;
    USE SIGNAL ;
    ANTENNADIFFAREA 0.708600 ;
    PORT
      LAYER Metal3 ;
        RECT 0.000 3539.980 0.400 3540.380 ;
    END
  END m_axi_dma_wdata[18]
  PIN m_axi_dma_wdata[19]
    DIRECTION OUTPUT ;
    USE SIGNAL ;
    ANTENNADIFFAREA 0.708600 ;
    PORT
      LAYER Metal3 ;
        RECT 0.000 3548.380 0.400 3548.780 ;
    END
  END m_axi_dma_wdata[19]
  PIN m_axi_dma_wdata[1]
    DIRECTION OUTPUT ;
    USE SIGNAL ;
    ANTENNADIFFAREA 0.708600 ;
    PORT
      LAYER Metal3 ;
        RECT 0.000 3397.180 0.400 3397.580 ;
    END
  END m_axi_dma_wdata[1]
  PIN m_axi_dma_wdata[20]
    DIRECTION OUTPUT ;
    USE SIGNAL ;
    ANTENNADIFFAREA 0.708600 ;
    PORT
      LAYER Metal3 ;
        RECT 0.000 3556.780 0.400 3557.180 ;
    END
  END m_axi_dma_wdata[20]
  PIN m_axi_dma_wdata[21]
    DIRECTION OUTPUT ;
    USE SIGNAL ;
    ANTENNADIFFAREA 0.708600 ;
    PORT
      LAYER Metal3 ;
        RECT 0.000 3565.180 0.400 3565.580 ;
    END
  END m_axi_dma_wdata[21]
  PIN m_axi_dma_wdata[22]
    DIRECTION OUTPUT ;
    USE SIGNAL ;
    ANTENNADIFFAREA 0.708600 ;
    PORT
      LAYER Metal3 ;
        RECT 0.000 3573.580 0.400 3573.980 ;
    END
  END m_axi_dma_wdata[22]
  PIN m_axi_dma_wdata[23]
    DIRECTION OUTPUT ;
    USE SIGNAL ;
    ANTENNADIFFAREA 0.708600 ;
    PORT
      LAYER Metal3 ;
        RECT 0.000 3581.980 0.400 3582.380 ;
    END
  END m_axi_dma_wdata[23]
  PIN m_axi_dma_wdata[24]
    DIRECTION OUTPUT ;
    USE SIGNAL ;
    ANTENNADIFFAREA 0.708600 ;
    PORT
      LAYER Metal3 ;
        RECT 0.000 3590.380 0.400 3590.780 ;
    END
  END m_axi_dma_wdata[24]
  PIN m_axi_dma_wdata[25]
    DIRECTION OUTPUT ;
    USE SIGNAL ;
    ANTENNADIFFAREA 0.708600 ;
    PORT
      LAYER Metal3 ;
        RECT 0.000 3598.780 0.400 3599.180 ;
    END
  END m_axi_dma_wdata[25]
  PIN m_axi_dma_wdata[26]
    DIRECTION OUTPUT ;
    USE SIGNAL ;
    ANTENNADIFFAREA 0.708600 ;
    PORT
      LAYER Metal3 ;
        RECT 0.000 3607.180 0.400 3607.580 ;
    END
  END m_axi_dma_wdata[26]
  PIN m_axi_dma_wdata[27]
    DIRECTION OUTPUT ;
    USE SIGNAL ;
    ANTENNADIFFAREA 0.708600 ;
    PORT
      LAYER Metal3 ;
        RECT 0.000 3615.580 0.400 3615.980 ;
    END
  END m_axi_dma_wdata[27]
  PIN m_axi_dma_wdata[28]
    DIRECTION OUTPUT ;
    USE SIGNAL ;
    ANTENNADIFFAREA 0.708600 ;
    PORT
      LAYER Metal3 ;
        RECT 0.000 3623.980 0.400 3624.380 ;
    END
  END m_axi_dma_wdata[28]
  PIN m_axi_dma_wdata[29]
    DIRECTION OUTPUT ;
    USE SIGNAL ;
    ANTENNADIFFAREA 0.708600 ;
    PORT
      LAYER Metal3 ;
        RECT 0.000 3632.380 0.400 3632.780 ;
    END
  END m_axi_dma_wdata[29]
  PIN m_axi_dma_wdata[2]
    DIRECTION OUTPUT ;
    USE SIGNAL ;
    ANTENNADIFFAREA 0.708600 ;
    PORT
      LAYER Metal3 ;
        RECT 0.000 3405.580 0.400 3405.980 ;
    END
  END m_axi_dma_wdata[2]
  PIN m_axi_dma_wdata[30]
    DIRECTION OUTPUT ;
    USE SIGNAL ;
    ANTENNADIFFAREA 0.708600 ;
    PORT
      LAYER Metal3 ;
        RECT 0.000 3640.780 0.400 3641.180 ;
    END
  END m_axi_dma_wdata[30]
  PIN m_axi_dma_wdata[31]
    DIRECTION OUTPUT ;
    USE SIGNAL ;
    ANTENNADIFFAREA 0.708600 ;
    PORT
      LAYER Metal3 ;
        RECT 0.000 3649.180 0.400 3649.580 ;
    END
  END m_axi_dma_wdata[31]
  PIN m_axi_dma_wdata[3]
    DIRECTION OUTPUT ;
    USE SIGNAL ;
    ANTENNADIFFAREA 0.708600 ;
    PORT
      LAYER Metal3 ;
        RECT 0.000 3413.980 0.400 3414.380 ;
    END
  END m_axi_dma_wdata[3]
  PIN m_axi_dma_wdata[4]
    DIRECTION OUTPUT ;
    USE SIGNAL ;
    ANTENNADIFFAREA 0.708600 ;
    PORT
      LAYER Metal3 ;
        RECT 0.000 3422.380 0.400 3422.780 ;
    END
  END m_axi_dma_wdata[4]
  PIN m_axi_dma_wdata[5]
    DIRECTION OUTPUT ;
    USE SIGNAL ;
    ANTENNADIFFAREA 0.708600 ;
    PORT
      LAYER Metal3 ;
        RECT 0.000 3430.780 0.400 3431.180 ;
    END
  END m_axi_dma_wdata[5]
  PIN m_axi_dma_wdata[6]
    DIRECTION OUTPUT ;
    USE SIGNAL ;
    ANTENNADIFFAREA 0.708600 ;
    PORT
      LAYER Metal3 ;
        RECT 0.000 3439.180 0.400 3439.580 ;
    END
  END m_axi_dma_wdata[6]
  PIN m_axi_dma_wdata[7]
    DIRECTION OUTPUT ;
    USE SIGNAL ;
    ANTENNADIFFAREA 0.708600 ;
    PORT
      LAYER Metal3 ;
        RECT 0.000 3447.580 0.400 3447.980 ;
    END
  END m_axi_dma_wdata[7]
  PIN m_axi_dma_wdata[8]
    DIRECTION OUTPUT ;
    USE SIGNAL ;
    ANTENNADIFFAREA 0.708600 ;
    PORT
      LAYER Metal3 ;
        RECT 0.000 3455.980 0.400 3456.380 ;
    END
  END m_axi_dma_wdata[8]
  PIN m_axi_dma_wdata[9]
    DIRECTION OUTPUT ;
    USE SIGNAL ;
    ANTENNADIFFAREA 0.708600 ;
    PORT
      LAYER Metal3 ;
        RECT 0.000 3464.380 0.400 3464.780 ;
    END
  END m_axi_dma_wdata[9]
  PIN m_axi_dma_wlast
    DIRECTION OUTPUT ;
    USE SIGNAL ;
    ANTENNADIFFAREA 0.708600 ;
    PORT
      LAYER Metal3 ;
        RECT 0.000 3346.780 0.400 3347.180 ;
    END
  END m_axi_dma_wlast
  PIN m_axi_dma_wready
    DIRECTION INPUT ;
    USE SIGNAL ;
    ANTENNAGATEAREA 0.180700 ;
    ANTENNADIFFAREA 2.015400 ;
    PORT
      LAYER Metal3 ;
        RECT 0.000 3329.980 0.400 3330.380 ;
    END
  END m_axi_dma_wready
  PIN m_axi_dma_wstrb[0]
    DIRECTION OUTPUT ;
    USE SIGNAL ;
    ANTENNADIFFAREA 0.708600 ;
    PORT
      LAYER Metal3 ;
        RECT 0.000 3355.180 0.400 3355.580 ;
    END
  END m_axi_dma_wstrb[0]
  PIN m_axi_dma_wstrb[1]
    DIRECTION OUTPUT ;
    USE SIGNAL ;
    ANTENNADIFFAREA 0.708600 ;
    PORT
      LAYER Metal3 ;
        RECT 0.000 3363.580 0.400 3363.980 ;
    END
  END m_axi_dma_wstrb[1]
  PIN m_axi_dma_wstrb[2]
    DIRECTION OUTPUT ;
    USE SIGNAL ;
    ANTENNADIFFAREA 0.708600 ;
    PORT
      LAYER Metal3 ;
        RECT 0.000 3371.980 0.400 3372.380 ;
    END
  END m_axi_dma_wstrb[2]
  PIN m_axi_dma_wstrb[3]
    DIRECTION OUTPUT ;
    USE SIGNAL ;
    ANTENNADIFFAREA 0.708600 ;
    PORT
      LAYER Metal3 ;
        RECT 0.000 3380.380 0.400 3380.780 ;
    END
  END m_axi_dma_wstrb[3]
  PIN m_axi_dma_wvalid
    DIRECTION OUTPUT ;
    USE SIGNAL ;
    ANTENNADIFFAREA 0.708600 ;
    PORT
      LAYER Metal3 ;
        RECT 0.000 3338.380 0.400 3338.780 ;
    END
  END m_axi_dma_wvalid
  PIN pmod_io_i[0]
    DIRECTION INPUT ;
    USE SIGNAL ;
    ANTENNAGATEAREA 0.109200 ;
    ANTENNADIFFAREA 2.015400 ;
    PORT
      LAYER Metal2 ;
        RECT 517.720 4249.600 518.120 4250.000 ;
    END
  END pmod_io_i[0]
  PIN pmod_io_i[1]
    DIRECTION INPUT ;
    USE SIGNAL ;
    ANTENNAGATEAREA 0.109200 ;
    ANTENNADIFFAREA 2.015400 ;
    PORT
      LAYER Metal2 ;
        RECT 533.080 4249.600 533.480 4250.000 ;
    END
  END pmod_io_i[1]
  PIN pmod_io_i[2]
    DIRECTION INPUT ;
    USE SIGNAL ;
    ANTENNAGATEAREA 0.109200 ;
    ANTENNADIFFAREA 2.015400 ;
    PORT
      LAYER Metal2 ;
        RECT 548.440 4249.600 548.840 4250.000 ;
    END
  END pmod_io_i[2]
  PIN pmod_io_i[3]
    DIRECTION INPUT ;
    USE SIGNAL ;
    ANTENNAGATEAREA 0.109200 ;
    ANTENNADIFFAREA 2.015400 ;
    PORT
      LAYER Metal2 ;
        RECT 563.800 4249.600 564.200 4250.000 ;
    END
  END pmod_io_i[3]
  PIN pmod_io_i[4]
    DIRECTION INPUT ;
    USE SIGNAL ;
    ANTENNAGATEAREA 0.109200 ;
    ANTENNADIFFAREA 2.015400 ;
    PORT
      LAYER Metal2 ;
        RECT 579.160 4249.600 579.560 4250.000 ;
    END
  END pmod_io_i[4]
  PIN pmod_io_i[5]
    DIRECTION INPUT ;
    USE SIGNAL ;
    ANTENNAGATEAREA 0.109200 ;
    ANTENNADIFFAREA 2.015400 ;
    PORT
      LAYER Metal2 ;
        RECT 594.520 4249.600 594.920 4250.000 ;
    END
  END pmod_io_i[5]
  PIN pmod_io_i[6]
    DIRECTION INPUT ;
    USE SIGNAL ;
    ANTENNAGATEAREA 0.109200 ;
    ANTENNADIFFAREA 2.015400 ;
    PORT
      LAYER Metal2 ;
        RECT 609.880 4249.600 610.280 4250.000 ;
    END
  END pmod_io_i[6]
  PIN pmod_io_i[7]
    DIRECTION INPUT ;
    USE SIGNAL ;
    ANTENNAGATEAREA 0.109200 ;
    ANTENNADIFFAREA 2.015400 ;
    PORT
      LAYER Metal2 ;
        RECT 625.240 4249.600 625.640 4250.000 ;
    END
  END pmod_io_i[7]
  PIN pmod_io_o[0]
    DIRECTION OUTPUT ;
    USE SIGNAL ;
    ANTENNADIFFAREA 0.708600 ;
    PORT
      LAYER Metal2 ;
        RECT 640.600 4249.600 641.000 4250.000 ;
    END
  END pmod_io_o[0]
  PIN pmod_io_o[1]
    DIRECTION OUTPUT ;
    USE SIGNAL ;
    ANTENNADIFFAREA 0.708600 ;
    PORT
      LAYER Metal2 ;
        RECT 655.960 4249.600 656.360 4250.000 ;
    END
  END pmod_io_o[1]
  PIN pmod_io_o[2]
    DIRECTION OUTPUT ;
    USE SIGNAL ;
    ANTENNADIFFAREA 0.708600 ;
    PORT
      LAYER Metal2 ;
        RECT 671.320 4249.600 671.720 4250.000 ;
    END
  END pmod_io_o[2]
  PIN pmod_io_o[3]
    DIRECTION OUTPUT ;
    USE SIGNAL ;
    ANTENNADIFFAREA 0.708600 ;
    PORT
      LAYER Metal2 ;
        RECT 686.680 4249.600 687.080 4250.000 ;
    END
  END pmod_io_o[3]
  PIN pmod_io_o[4]
    DIRECTION OUTPUT ;
    USE SIGNAL ;
    ANTENNADIFFAREA 0.708600 ;
    PORT
      LAYER Metal2 ;
        RECT 702.040 4249.600 702.440 4250.000 ;
    END
  END pmod_io_o[4]
  PIN pmod_io_o[5]
    DIRECTION OUTPUT ;
    USE SIGNAL ;
    ANTENNADIFFAREA 0.708600 ;
    PORT
      LAYER Metal2 ;
        RECT 717.400 4249.600 717.800 4250.000 ;
    END
  END pmod_io_o[5]
  PIN pmod_io_o[6]
    DIRECTION OUTPUT ;
    USE SIGNAL ;
    ANTENNADIFFAREA 0.708600 ;
    PORT
      LAYER Metal2 ;
        RECT 732.760 4249.600 733.160 4250.000 ;
    END
  END pmod_io_o[6]
  PIN pmod_io_o[7]
    DIRECTION OUTPUT ;
    USE SIGNAL ;
    ANTENNADIFFAREA 0.708600 ;
    PORT
      LAYER Metal2 ;
        RECT 748.120 4249.600 748.520 4250.000 ;
    END
  END pmod_io_o[7]
  PIN pmod_io_oe_o[0]
    DIRECTION OUTPUT ;
    USE SIGNAL ;
    ANTENNADIFFAREA 0.708600 ;
    PORT
      LAYER Metal2 ;
        RECT 763.480 4249.600 763.880 4250.000 ;
    END
  END pmod_io_oe_o[0]
  PIN pmod_io_oe_o[1]
    DIRECTION OUTPUT ;
    USE SIGNAL ;
    ANTENNADIFFAREA 0.708600 ;
    PORT
      LAYER Metal2 ;
        RECT 778.840 4249.600 779.240 4250.000 ;
    END
  END pmod_io_oe_o[1]
  PIN pmod_io_oe_o[2]
    DIRECTION OUTPUT ;
    USE SIGNAL ;
    ANTENNADIFFAREA 0.708600 ;
    PORT
      LAYER Metal2 ;
        RECT 794.200 4249.600 794.600 4250.000 ;
    END
  END pmod_io_oe_o[2]
  PIN pmod_io_oe_o[3]
    DIRECTION OUTPUT ;
    USE SIGNAL ;
    ANTENNADIFFAREA 0.708600 ;
    PORT
      LAYER Metal2 ;
        RECT 809.560 4249.600 809.960 4250.000 ;
    END
  END pmod_io_oe_o[3]
  PIN pmod_io_oe_o[4]
    DIRECTION OUTPUT ;
    USE SIGNAL ;
    ANTENNADIFFAREA 0.708600 ;
    PORT
      LAYER Metal2 ;
        RECT 824.920 4249.600 825.320 4250.000 ;
    END
  END pmod_io_oe_o[4]
  PIN pmod_io_oe_o[5]
    DIRECTION OUTPUT ;
    USE SIGNAL ;
    ANTENNADIFFAREA 0.708600 ;
    PORT
      LAYER Metal2 ;
        RECT 840.280 4249.600 840.680 4250.000 ;
    END
  END pmod_io_oe_o[5]
  PIN pmod_io_oe_o[6]
    DIRECTION OUTPUT ;
    USE SIGNAL ;
    ANTENNADIFFAREA 0.708600 ;
    PORT
      LAYER Metal2 ;
        RECT 855.640 4249.600 856.040 4250.000 ;
    END
  END pmod_io_oe_o[6]
  PIN pmod_io_oe_o[7]
    DIRECTION OUTPUT ;
    USE SIGNAL ;
    ANTENNADIFFAREA 0.708600 ;
    PORT
      LAYER Metal2 ;
        RECT 871.000 4249.600 871.400 4250.000 ;
    END
  END pmod_io_oe_o[7]
  PIN rst_efpga_connector_i
    DIRECTION INPUT ;
    USE SIGNAL ;
    ANTENNAGATEAREA 0.180700 ;
    ANTENNADIFFAREA 2.015400 ;
    PORT
      LAYER Metal2 ;
        RECT 1012.120 0.000 1012.520 0.400 ;
    END
  END rst_efpga_connector_i
  PIN rst_efpga_connector_n_i
    DIRECTION INPUT ;
    USE SIGNAL ;
    ANTENNAGATEAREA 0.180700 ;
    ANTENNADIFFAREA 2.015400 ;
    PORT
      LAYER Metal2 ;
        RECT 919.000 0.000 919.400 0.400 ;
    END
  END rst_efpga_connector_n_i
  PIN rst_efpga_fabric_n_i
    DIRECTION INPUT ;
    USE SIGNAL ;
    ANTENNAGATEAREA 0.180700 ;
    ANTENNADIFFAREA 2.015400 ;
    PORT
      LAYER Metal2 ;
        RECT 1105.240 0.000 1105.640 0.400 ;
    END
  END rst_efpga_fabric_n_i
  PIN rst_efpga_npu_n_i
    DIRECTION INPUT ;
    USE SIGNAL ;
    ANTENNAGATEAREA 0.109200 ;
    ANTENNADIFFAREA 2.015400 ;
    PORT
      LAYER Metal2 ;
        RECT 1570.840 0.000 1571.240 0.400 ;
    END
  END rst_efpga_npu_n_i
  PIN rst_efpga_slot_n_i[0]
    DIRECTION INPUT ;
    USE SIGNAL ;
    ANTENNAGATEAREA 0.109200 ;
    ANTENNADIFFAREA 2.015400 ;
    PORT
      LAYER Metal2 ;
        RECT 1198.360 0.000 1198.760 0.400 ;
    END
  END rst_efpga_slot_n_i[0]
  PIN rst_efpga_slot_n_i[1]
    DIRECTION INPUT ;
    USE SIGNAL ;
    ANTENNAGATEAREA 0.109200 ;
    ANTENNADIFFAREA 2.015400 ;
    PORT
      LAYER Metal2 ;
        RECT 1291.480 0.000 1291.880 0.400 ;
    END
  END rst_efpga_slot_n_i[1]
  PIN rst_efpga_slot_n_i[2]
    DIRECTION INPUT ;
    USE SIGNAL ;
    ANTENNAGATEAREA 0.109200 ;
    ANTENNADIFFAREA 2.015400 ;
    PORT
      LAYER Metal2 ;
        RECT 1384.600 0.000 1385.000 0.400 ;
    END
  END rst_efpga_slot_n_i[2]
  PIN rst_efpga_slot_n_i[3]
    DIRECTION INPUT ;
    USE SIGNAL ;
    ANTENNAGATEAREA 0.109200 ;
    ANTENNADIFFAREA 2.015400 ;
    PORT
      LAYER Metal2 ;
        RECT 1477.720 0.000 1478.120 0.400 ;
    END
  END rst_efpga_slot_n_i[3]
  PIN s_axil_ctrl_araddr[0]
    DIRECTION INPUT ;
    USE SIGNAL ;
    ANTENNAGATEAREA 0.180700 ;
    ANTENNADIFFAREA 2.015400 ;
    PORT
      LAYER Metal3 ;
        RECT 0.000 1389.580 0.400 1389.980 ;
    END
  END s_axil_ctrl_araddr[0]
  PIN s_axil_ctrl_araddr[10]
    DIRECTION INPUT ;
    USE SIGNAL ;
    PORT
      LAYER Metal3 ;
        RECT 0.000 1473.580 0.400 1473.980 ;
    END
  END s_axil_ctrl_araddr[10]
  PIN s_axil_ctrl_araddr[11]
    DIRECTION INPUT ;
    USE SIGNAL ;
    PORT
      LAYER Metal3 ;
        RECT 0.000 1481.980 0.400 1482.380 ;
    END
  END s_axil_ctrl_araddr[11]
  PIN s_axil_ctrl_araddr[12]
    DIRECTION INPUT ;
    USE SIGNAL ;
    PORT
      LAYER Metal3 ;
        RECT 0.000 1490.380 0.400 1490.780 ;
    END
  END s_axil_ctrl_araddr[12]
  PIN s_axil_ctrl_araddr[13]
    DIRECTION INPUT ;
    USE SIGNAL ;
    PORT
      LAYER Metal3 ;
        RECT 0.000 1498.780 0.400 1499.180 ;
    END
  END s_axil_ctrl_araddr[13]
  PIN s_axil_ctrl_araddr[14]
    DIRECTION INPUT ;
    USE SIGNAL ;
    PORT
      LAYER Metal3 ;
        RECT 0.000 1507.180 0.400 1507.580 ;
    END
  END s_axil_ctrl_araddr[14]
  PIN s_axil_ctrl_araddr[15]
    DIRECTION INPUT ;
    USE SIGNAL ;
    PORT
      LAYER Metal3 ;
        RECT 0.000 1515.580 0.400 1515.980 ;
    END
  END s_axil_ctrl_araddr[15]
  PIN s_axil_ctrl_araddr[16]
    DIRECTION INPUT ;
    USE SIGNAL ;
    PORT
      LAYER Metal3 ;
        RECT 0.000 1523.980 0.400 1524.380 ;
    END
  END s_axil_ctrl_araddr[16]
  PIN s_axil_ctrl_araddr[17]
    DIRECTION INPUT ;
    USE SIGNAL ;
    PORT
      LAYER Metal3 ;
        RECT 0.000 1532.380 0.400 1532.780 ;
    END
  END s_axil_ctrl_araddr[17]
  PIN s_axil_ctrl_araddr[18]
    DIRECTION INPUT ;
    USE SIGNAL ;
    PORT
      LAYER Metal3 ;
        RECT 0.000 1540.780 0.400 1541.180 ;
    END
  END s_axil_ctrl_araddr[18]
  PIN s_axil_ctrl_araddr[19]
    DIRECTION INPUT ;
    USE SIGNAL ;
    PORT
      LAYER Metal3 ;
        RECT 0.000 1549.180 0.400 1549.580 ;
    END
  END s_axil_ctrl_araddr[19]
  PIN s_axil_ctrl_araddr[1]
    DIRECTION INPUT ;
    USE SIGNAL ;
    ANTENNAGATEAREA 0.180700 ;
    ANTENNADIFFAREA 2.015400 ;
    PORT
      LAYER Metal3 ;
        RECT 0.000 1397.980 0.400 1398.380 ;
    END
  END s_axil_ctrl_araddr[1]
  PIN s_axil_ctrl_araddr[20]
    DIRECTION INPUT ;
    USE SIGNAL ;
    PORT
      LAYER Metal3 ;
        RECT 0.000 1557.580 0.400 1557.980 ;
    END
  END s_axil_ctrl_araddr[20]
  PIN s_axil_ctrl_araddr[21]
    DIRECTION INPUT ;
    USE SIGNAL ;
    PORT
      LAYER Metal3 ;
        RECT 0.000 1565.980 0.400 1566.380 ;
    END
  END s_axil_ctrl_araddr[21]
  PIN s_axil_ctrl_araddr[22]
    DIRECTION INPUT ;
    USE SIGNAL ;
    PORT
      LAYER Metal3 ;
        RECT 0.000 1574.380 0.400 1574.780 ;
    END
  END s_axil_ctrl_araddr[22]
  PIN s_axil_ctrl_araddr[23]
    DIRECTION INPUT ;
    USE SIGNAL ;
    PORT
      LAYER Metal3 ;
        RECT 0.000 1582.780 0.400 1583.180 ;
    END
  END s_axil_ctrl_araddr[23]
  PIN s_axil_ctrl_araddr[24]
    DIRECTION INPUT ;
    USE SIGNAL ;
    PORT
      LAYER Metal3 ;
        RECT 0.000 1591.180 0.400 1591.580 ;
    END
  END s_axil_ctrl_araddr[24]
  PIN s_axil_ctrl_araddr[25]
    DIRECTION INPUT ;
    USE SIGNAL ;
    PORT
      LAYER Metal3 ;
        RECT 0.000 1599.580 0.400 1599.980 ;
    END
  END s_axil_ctrl_araddr[25]
  PIN s_axil_ctrl_araddr[26]
    DIRECTION INPUT ;
    USE SIGNAL ;
    PORT
      LAYER Metal3 ;
        RECT 0.000 1607.980 0.400 1608.380 ;
    END
  END s_axil_ctrl_araddr[26]
  PIN s_axil_ctrl_araddr[27]
    DIRECTION INPUT ;
    USE SIGNAL ;
    PORT
      LAYER Metal3 ;
        RECT 0.000 1616.380 0.400 1616.780 ;
    END
  END s_axil_ctrl_araddr[27]
  PIN s_axil_ctrl_araddr[28]
    DIRECTION INPUT ;
    USE SIGNAL ;
    PORT
      LAYER Metal3 ;
        RECT 0.000 1624.780 0.400 1625.180 ;
    END
  END s_axil_ctrl_araddr[28]
  PIN s_axil_ctrl_araddr[29]
    DIRECTION INPUT ;
    USE SIGNAL ;
    PORT
      LAYER Metal3 ;
        RECT 0.000 1633.180 0.400 1633.580 ;
    END
  END s_axil_ctrl_araddr[29]
  PIN s_axil_ctrl_araddr[2]
    DIRECTION INPUT ;
    USE SIGNAL ;
    ANTENNAGATEAREA 0.180700 ;
    ANTENNADIFFAREA 4.030800 ;
    PORT
      LAYER Metal3 ;
        RECT 0.000 1406.380 0.400 1406.780 ;
    END
  END s_axil_ctrl_araddr[2]
  PIN s_axil_ctrl_araddr[30]
    DIRECTION INPUT ;
    USE SIGNAL ;
    PORT
      LAYER Metal3 ;
        RECT 0.000 1641.580 0.400 1641.980 ;
    END
  END s_axil_ctrl_araddr[30]
  PIN s_axil_ctrl_araddr[31]
    DIRECTION INPUT ;
    USE SIGNAL ;
    PORT
      LAYER Metal3 ;
        RECT 0.000 1649.980 0.400 1650.380 ;
    END
  END s_axil_ctrl_araddr[31]
  PIN s_axil_ctrl_araddr[3]
    DIRECTION INPUT ;
    USE SIGNAL ;
    ANTENNAGATEAREA 0.180700 ;
    ANTENNADIFFAREA 2.015400 ;
    PORT
      LAYER Metal3 ;
        RECT 0.000 1414.780 0.400 1415.180 ;
    END
  END s_axil_ctrl_araddr[3]
  PIN s_axil_ctrl_araddr[4]
    DIRECTION INPUT ;
    USE SIGNAL ;
    ANTENNAGATEAREA 0.180700 ;
    ANTENNADIFFAREA 4.030800 ;
    PORT
      LAYER Metal3 ;
        RECT 0.000 1423.180 0.400 1423.580 ;
    END
  END s_axil_ctrl_araddr[4]
  PIN s_axil_ctrl_araddr[5]
    DIRECTION INPUT ;
    USE SIGNAL ;
    ANTENNAGATEAREA 0.180700 ;
    ANTENNADIFFAREA 2.015400 ;
    PORT
      LAYER Metal3 ;
        RECT 0.000 1431.580 0.400 1431.980 ;
    END
  END s_axil_ctrl_araddr[5]
  PIN s_axil_ctrl_araddr[6]
    DIRECTION INPUT ;
    USE SIGNAL ;
    ANTENNAGATEAREA 0.180700 ;
    ANTENNADIFFAREA 4.030800 ;
    PORT
      LAYER Metal3 ;
        RECT 0.000 1439.980 0.400 1440.380 ;
    END
  END s_axil_ctrl_araddr[6]
  PIN s_axil_ctrl_araddr[7]
    DIRECTION INPUT ;
    USE SIGNAL ;
    ANTENNAGATEAREA 0.180700 ;
    ANTENNADIFFAREA 4.030800 ;
    PORT
      LAYER Metal3 ;
        RECT 0.000 1448.380 0.400 1448.780 ;
    END
  END s_axil_ctrl_araddr[7]
  PIN s_axil_ctrl_araddr[8]
    DIRECTION INPUT ;
    USE SIGNAL ;
    ANTENNAGATEAREA 0.180700 ;
    ANTENNADIFFAREA 2.015400 ;
    PORT
      LAYER Metal3 ;
        RECT 0.000 1456.780 0.400 1457.180 ;
    END
  END s_axil_ctrl_araddr[8]
  PIN s_axil_ctrl_araddr[9]
    DIRECTION INPUT ;
    USE SIGNAL ;
    ANTENNAGATEAREA 0.180700 ;
    ANTENNADIFFAREA 4.030800 ;
    PORT
      LAYER Metal3 ;
        RECT 0.000 1465.180 0.400 1465.580 ;
    END
  END s_axil_ctrl_araddr[9]
  PIN s_axil_ctrl_arprot[0]
    DIRECTION INPUT ;
    USE SIGNAL ;
    ANTENNAGATEAREA 0.180700 ;
    ANTENNADIFFAREA 2.015400 ;
    PORT
      LAYER Metal3 ;
        RECT 0.000 1364.380 0.400 1364.780 ;
    END
  END s_axil_ctrl_arprot[0]
  PIN s_axil_ctrl_arprot[1]
    DIRECTION INPUT ;
    USE SIGNAL ;
    ANTENNAGATEAREA 0.180700 ;
    ANTENNADIFFAREA 4.030800 ;
    PORT
      LAYER Metal3 ;
        RECT 0.000 1372.780 0.400 1373.180 ;
    END
  END s_axil_ctrl_arprot[1]
  PIN s_axil_ctrl_arprot[2]
    DIRECTION INPUT ;
    USE SIGNAL ;
    ANTENNAGATEAREA 0.180700 ;
    ANTENNADIFFAREA 2.015400 ;
    PORT
      LAYER Metal3 ;
        RECT 0.000 1381.180 0.400 1381.580 ;
    END
  END s_axil_ctrl_arprot[2]
  PIN s_axil_ctrl_arready
    DIRECTION OUTPUT ;
    USE SIGNAL ;
    ANTENNADIFFAREA 0.708600 ;
    PORT
      LAYER Metal3 ;
        RECT 0.000 1347.580 0.400 1347.980 ;
    END
  END s_axil_ctrl_arready
  PIN s_axil_ctrl_arvalid
    DIRECTION INPUT ;
    USE SIGNAL ;
    ANTENNAGATEAREA 0.180700 ;
    ANTENNADIFFAREA 2.015400 ;
    PORT
      LAYER Metal3 ;
        RECT 0.000 1355.980 0.400 1356.380 ;
    END
  END s_axil_ctrl_arvalid
  PIN s_axil_ctrl_awaddr[0]
    DIRECTION INPUT ;
    USE SIGNAL ;
    ANTENNAGATEAREA 0.180700 ;
    ANTENNADIFFAREA 4.030800 ;
    PORT
      LAYER Metal3 ;
        RECT 0.000 2053.180 0.400 2053.580 ;
    END
  END s_axil_ctrl_awaddr[0]
  PIN s_axil_ctrl_awaddr[10]
    DIRECTION INPUT ;
    USE SIGNAL ;
    PORT
      LAYER Metal3 ;
        RECT 0.000 2137.180 0.400 2137.580 ;
    END
  END s_axil_ctrl_awaddr[10]
  PIN s_axil_ctrl_awaddr[11]
    DIRECTION INPUT ;
    USE SIGNAL ;
    PORT
      LAYER Metal3 ;
        RECT 0.000 2145.580 0.400 2145.980 ;
    END
  END s_axil_ctrl_awaddr[11]
  PIN s_axil_ctrl_awaddr[12]
    DIRECTION INPUT ;
    USE SIGNAL ;
    PORT
      LAYER Metal3 ;
        RECT 0.000 2153.980 0.400 2154.380 ;
    END
  END s_axil_ctrl_awaddr[12]
  PIN s_axil_ctrl_awaddr[13]
    DIRECTION INPUT ;
    USE SIGNAL ;
    PORT
      LAYER Metal3 ;
        RECT 0.000 2162.380 0.400 2162.780 ;
    END
  END s_axil_ctrl_awaddr[13]
  PIN s_axil_ctrl_awaddr[14]
    DIRECTION INPUT ;
    USE SIGNAL ;
    PORT
      LAYER Metal3 ;
        RECT 0.000 2170.780 0.400 2171.180 ;
    END
  END s_axil_ctrl_awaddr[14]
  PIN s_axil_ctrl_awaddr[15]
    DIRECTION INPUT ;
    USE SIGNAL ;
    PORT
      LAYER Metal3 ;
        RECT 0.000 2179.180 0.400 2179.580 ;
    END
  END s_axil_ctrl_awaddr[15]
  PIN s_axil_ctrl_awaddr[16]
    DIRECTION INPUT ;
    USE SIGNAL ;
    PORT
      LAYER Metal3 ;
        RECT 0.000 2187.580 0.400 2187.980 ;
    END
  END s_axil_ctrl_awaddr[16]
  PIN s_axil_ctrl_awaddr[17]
    DIRECTION INPUT ;
    USE SIGNAL ;
    PORT
      LAYER Metal3 ;
        RECT 0.000 2195.980 0.400 2196.380 ;
    END
  END s_axil_ctrl_awaddr[17]
  PIN s_axil_ctrl_awaddr[18]
    DIRECTION INPUT ;
    USE SIGNAL ;
    PORT
      LAYER Metal3 ;
        RECT 0.000 2204.380 0.400 2204.780 ;
    END
  END s_axil_ctrl_awaddr[18]
  PIN s_axil_ctrl_awaddr[19]
    DIRECTION INPUT ;
    USE SIGNAL ;
    PORT
      LAYER Metal3 ;
        RECT 0.000 2212.780 0.400 2213.180 ;
    END
  END s_axil_ctrl_awaddr[19]
  PIN s_axil_ctrl_awaddr[1]
    DIRECTION INPUT ;
    USE SIGNAL ;
    ANTENNAGATEAREA 0.180700 ;
    ANTENNADIFFAREA 2.015400 ;
    PORT
      LAYER Metal3 ;
        RECT 0.000 2061.580 0.400 2061.980 ;
    END
  END s_axil_ctrl_awaddr[1]
  PIN s_axil_ctrl_awaddr[20]
    DIRECTION INPUT ;
    USE SIGNAL ;
    PORT
      LAYER Metal3 ;
        RECT 0.000 2221.180 0.400 2221.580 ;
    END
  END s_axil_ctrl_awaddr[20]
  PIN s_axil_ctrl_awaddr[21]
    DIRECTION INPUT ;
    USE SIGNAL ;
    PORT
      LAYER Metal3 ;
        RECT 0.000 2229.580 0.400 2229.980 ;
    END
  END s_axil_ctrl_awaddr[21]
  PIN s_axil_ctrl_awaddr[22]
    DIRECTION INPUT ;
    USE SIGNAL ;
    PORT
      LAYER Metal3 ;
        RECT 0.000 2237.980 0.400 2238.380 ;
    END
  END s_axil_ctrl_awaddr[22]
  PIN s_axil_ctrl_awaddr[23]
    DIRECTION INPUT ;
    USE SIGNAL ;
    PORT
      LAYER Metal3 ;
        RECT 0.000 2246.380 0.400 2246.780 ;
    END
  END s_axil_ctrl_awaddr[23]
  PIN s_axil_ctrl_awaddr[24]
    DIRECTION INPUT ;
    USE SIGNAL ;
    PORT
      LAYER Metal3 ;
        RECT 0.000 2254.780 0.400 2255.180 ;
    END
  END s_axil_ctrl_awaddr[24]
  PIN s_axil_ctrl_awaddr[25]
    DIRECTION INPUT ;
    USE SIGNAL ;
    PORT
      LAYER Metal3 ;
        RECT 0.000 2263.180 0.400 2263.580 ;
    END
  END s_axil_ctrl_awaddr[25]
  PIN s_axil_ctrl_awaddr[26]
    DIRECTION INPUT ;
    USE SIGNAL ;
    PORT
      LAYER Metal3 ;
        RECT 0.000 2271.580 0.400 2271.980 ;
    END
  END s_axil_ctrl_awaddr[26]
  PIN s_axil_ctrl_awaddr[27]
    DIRECTION INPUT ;
    USE SIGNAL ;
    PORT
      LAYER Metal3 ;
        RECT 0.000 2279.980 0.400 2280.380 ;
    END
  END s_axil_ctrl_awaddr[27]
  PIN s_axil_ctrl_awaddr[28]
    DIRECTION INPUT ;
    USE SIGNAL ;
    PORT
      LAYER Metal3 ;
        RECT 0.000 2288.380 0.400 2288.780 ;
    END
  END s_axil_ctrl_awaddr[28]
  PIN s_axil_ctrl_awaddr[29]
    DIRECTION INPUT ;
    USE SIGNAL ;
    PORT
      LAYER Metal3 ;
        RECT 0.000 2296.780 0.400 2297.180 ;
    END
  END s_axil_ctrl_awaddr[29]
  PIN s_axil_ctrl_awaddr[2]
    DIRECTION INPUT ;
    USE SIGNAL ;
    ANTENNAGATEAREA 0.180700 ;
    ANTENNADIFFAREA 2.015400 ;
    PORT
      LAYER Metal3 ;
        RECT 0.000 2069.980 0.400 2070.380 ;
    END
  END s_axil_ctrl_awaddr[2]
  PIN s_axil_ctrl_awaddr[30]
    DIRECTION INPUT ;
    USE SIGNAL ;
    PORT
      LAYER Metal3 ;
        RECT 0.000 2305.180 0.400 2305.580 ;
    END
  END s_axil_ctrl_awaddr[30]
  PIN s_axil_ctrl_awaddr[31]
    DIRECTION INPUT ;
    USE SIGNAL ;
    PORT
      LAYER Metal3 ;
        RECT 0.000 2313.580 0.400 2313.980 ;
    END
  END s_axil_ctrl_awaddr[31]
  PIN s_axil_ctrl_awaddr[3]
    DIRECTION INPUT ;
    USE SIGNAL ;
    ANTENNAGATEAREA 0.180700 ;
    ANTENNADIFFAREA 2.015400 ;
    PORT
      LAYER Metal3 ;
        RECT 0.000 2078.380 0.400 2078.780 ;
    END
  END s_axil_ctrl_awaddr[3]
  PIN s_axil_ctrl_awaddr[4]
    DIRECTION INPUT ;
    USE SIGNAL ;
    ANTENNAGATEAREA 0.180700 ;
    ANTENNADIFFAREA 4.030800 ;
    PORT
      LAYER Metal3 ;
        RECT 0.000 2086.780 0.400 2087.180 ;
    END
  END s_axil_ctrl_awaddr[4]
  PIN s_axil_ctrl_awaddr[5]
    DIRECTION INPUT ;
    USE SIGNAL ;
    ANTENNAGATEAREA 0.180700 ;
    ANTENNADIFFAREA 4.030800 ;
    PORT
      LAYER Metal3 ;
        RECT 0.000 2095.180 0.400 2095.580 ;
    END
  END s_axil_ctrl_awaddr[5]
  PIN s_axil_ctrl_awaddr[6]
    DIRECTION INPUT ;
    USE SIGNAL ;
    ANTENNAGATEAREA 0.180700 ;
    ANTENNADIFFAREA 2.015400 ;
    PORT
      LAYER Metal3 ;
        RECT 0.000 2103.580 0.400 2103.980 ;
    END
  END s_axil_ctrl_awaddr[6]
  PIN s_axil_ctrl_awaddr[7]
    DIRECTION INPUT ;
    USE SIGNAL ;
    ANTENNAGATEAREA 0.180700 ;
    ANTENNADIFFAREA 2.015400 ;
    PORT
      LAYER Metal3 ;
        RECT 0.000 2111.980 0.400 2112.380 ;
    END
  END s_axil_ctrl_awaddr[7]
  PIN s_axil_ctrl_awaddr[8]
    DIRECTION INPUT ;
    USE SIGNAL ;
    ANTENNAGATEAREA 0.180700 ;
    ANTENNADIFFAREA 2.015400 ;
    PORT
      LAYER Metal3 ;
        RECT 0.000 2120.380 0.400 2120.780 ;
    END
  END s_axil_ctrl_awaddr[8]
  PIN s_axil_ctrl_awaddr[9]
    DIRECTION INPUT ;
    USE SIGNAL ;
    ANTENNAGATEAREA 0.180700 ;
    ANTENNADIFFAREA 2.015400 ;
    PORT
      LAYER Metal3 ;
        RECT 0.000 2128.780 0.400 2129.180 ;
    END
  END s_axil_ctrl_awaddr[9]
  PIN s_axil_ctrl_awprot[0]
    DIRECTION INPUT ;
    USE SIGNAL ;
    ANTENNAGATEAREA 0.180700 ;
    ANTENNADIFFAREA 2.015400 ;
    PORT
      LAYER Metal3 ;
        RECT 0.000 2027.980 0.400 2028.380 ;
    END
  END s_axil_ctrl_awprot[0]
  PIN s_axil_ctrl_awprot[1]
    DIRECTION INPUT ;
    USE SIGNAL ;
    ANTENNAGATEAREA 0.180700 ;
    ANTENNADIFFAREA 2.015400 ;
    PORT
      LAYER Metal3 ;
        RECT 0.000 2036.380 0.400 2036.780 ;
    END
  END s_axil_ctrl_awprot[1]
  PIN s_axil_ctrl_awprot[2]
    DIRECTION INPUT ;
    USE SIGNAL ;
    ANTENNAGATEAREA 0.180700 ;
    ANTENNADIFFAREA 2.015400 ;
    PORT
      LAYER Metal3 ;
        RECT 0.000 2044.780 0.400 2045.180 ;
    END
  END s_axil_ctrl_awprot[2]
  PIN s_axil_ctrl_awready
    DIRECTION OUTPUT ;
    USE SIGNAL ;
    ANTENNADIFFAREA 0.708600 ;
    PORT
      LAYER Metal3 ;
        RECT 0.000 2011.180 0.400 2011.580 ;
    END
  END s_axil_ctrl_awready
  PIN s_axil_ctrl_awvalid
    DIRECTION INPUT ;
    USE SIGNAL ;
    ANTENNAGATEAREA 0.180700 ;
    ANTENNADIFFAREA 2.015400 ;
    PORT
      LAYER Metal3 ;
        RECT 0.000 2019.580 0.400 2019.980 ;
    END
  END s_axil_ctrl_awvalid
  PIN s_axil_ctrl_bready
    DIRECTION INPUT ;
    USE SIGNAL ;
    ANTENNAGATEAREA 0.180700 ;
    ANTENNADIFFAREA 4.030800 ;
    PORT
      LAYER Metal3 ;
        RECT 0.000 1658.380 0.400 1658.780 ;
    END
  END s_axil_ctrl_bready
  PIN s_axil_ctrl_bresp[0]
    DIRECTION OUTPUT ;
    USE SIGNAL ;
    ANTENNADIFFAREA 0.708600 ;
    PORT
      LAYER Metal3 ;
        RECT 0.000 1675.180 0.400 1675.580 ;
    END
  END s_axil_ctrl_bresp[0]
  PIN s_axil_ctrl_bresp[1]
    DIRECTION OUTPUT ;
    USE SIGNAL ;
    ANTENNADIFFAREA 0.708600 ;
    PORT
      LAYER Metal3 ;
        RECT 0.000 1683.580 0.400 1683.980 ;
    END
  END s_axil_ctrl_bresp[1]
  PIN s_axil_ctrl_bvalid
    DIRECTION OUTPUT ;
    USE SIGNAL ;
    ANTENNADIFFAREA 0.708600 ;
    PORT
      LAYER Metal3 ;
        RECT 0.000 1666.780 0.400 1667.180 ;
    END
  END s_axil_ctrl_bvalid
  PIN s_axil_ctrl_rdata[0]
    DIRECTION OUTPUT ;
    USE SIGNAL ;
    ANTENNADIFFAREA 0.708600 ;
    PORT
      LAYER Metal3 ;
        RECT 0.000 1078.780 0.400 1079.180 ;
    END
  END s_axil_ctrl_rdata[0]
  PIN s_axil_ctrl_rdata[10]
    DIRECTION OUTPUT ;
    USE SIGNAL ;
    ANTENNADIFFAREA 0.708600 ;
    PORT
      LAYER Metal3 ;
        RECT 0.000 1162.780 0.400 1163.180 ;
    END
  END s_axil_ctrl_rdata[10]
  PIN s_axil_ctrl_rdata[11]
    DIRECTION OUTPUT ;
    USE SIGNAL ;
    ANTENNADIFFAREA 0.708600 ;
    PORT
      LAYER Metal3 ;
        RECT 0.000 1171.180 0.400 1171.580 ;
    END
  END s_axil_ctrl_rdata[11]
  PIN s_axil_ctrl_rdata[12]
    DIRECTION OUTPUT ;
    USE SIGNAL ;
    ANTENNADIFFAREA 0.708600 ;
    PORT
      LAYER Metal3 ;
        RECT 0.000 1179.580 0.400 1179.980 ;
    END
  END s_axil_ctrl_rdata[12]
  PIN s_axil_ctrl_rdata[13]
    DIRECTION OUTPUT ;
    USE SIGNAL ;
    ANTENNADIFFAREA 0.708600 ;
    PORT
      LAYER Metal3 ;
        RECT 0.000 1187.980 0.400 1188.380 ;
    END
  END s_axil_ctrl_rdata[13]
  PIN s_axil_ctrl_rdata[14]
    DIRECTION OUTPUT ;
    USE SIGNAL ;
    ANTENNADIFFAREA 0.708600 ;
    PORT
      LAYER Metal3 ;
        RECT 0.000 1196.380 0.400 1196.780 ;
    END
  END s_axil_ctrl_rdata[14]
  PIN s_axil_ctrl_rdata[15]
    DIRECTION OUTPUT ;
    USE SIGNAL ;
    ANTENNADIFFAREA 0.708600 ;
    PORT
      LAYER Metal3 ;
        RECT 0.000 1204.780 0.400 1205.180 ;
    END
  END s_axil_ctrl_rdata[15]
  PIN s_axil_ctrl_rdata[16]
    DIRECTION OUTPUT ;
    USE SIGNAL ;
    ANTENNADIFFAREA 0.708600 ;
    PORT
      LAYER Metal3 ;
        RECT 0.000 1213.180 0.400 1213.580 ;
    END
  END s_axil_ctrl_rdata[16]
  PIN s_axil_ctrl_rdata[17]
    DIRECTION OUTPUT ;
    USE SIGNAL ;
    ANTENNADIFFAREA 0.708600 ;
    PORT
      LAYER Metal3 ;
        RECT 0.000 1221.580 0.400 1221.980 ;
    END
  END s_axil_ctrl_rdata[17]
  PIN s_axil_ctrl_rdata[18]
    DIRECTION OUTPUT ;
    USE SIGNAL ;
    ANTENNADIFFAREA 0.708600 ;
    PORT
      LAYER Metal3 ;
        RECT 0.000 1229.980 0.400 1230.380 ;
    END
  END s_axil_ctrl_rdata[18]
  PIN s_axil_ctrl_rdata[19]
    DIRECTION OUTPUT ;
    USE SIGNAL ;
    ANTENNADIFFAREA 0.708600 ;
    PORT
      LAYER Metal3 ;
        RECT 0.000 1238.380 0.400 1238.780 ;
    END
  END s_axil_ctrl_rdata[19]
  PIN s_axil_ctrl_rdata[1]
    DIRECTION OUTPUT ;
    USE SIGNAL ;
    ANTENNADIFFAREA 0.708600 ;
    PORT
      LAYER Metal3 ;
        RECT 0.000 1087.180 0.400 1087.580 ;
    END
  END s_axil_ctrl_rdata[1]
  PIN s_axil_ctrl_rdata[20]
    DIRECTION OUTPUT ;
    USE SIGNAL ;
    ANTENNADIFFAREA 0.708600 ;
    PORT
      LAYER Metal3 ;
        RECT 0.000 1246.780 0.400 1247.180 ;
    END
  END s_axil_ctrl_rdata[20]
  PIN s_axil_ctrl_rdata[21]
    DIRECTION OUTPUT ;
    USE SIGNAL ;
    ANTENNADIFFAREA 0.708600 ;
    PORT
      LAYER Metal3 ;
        RECT 0.000 1255.180 0.400 1255.580 ;
    END
  END s_axil_ctrl_rdata[21]
  PIN s_axil_ctrl_rdata[22]
    DIRECTION OUTPUT ;
    USE SIGNAL ;
    ANTENNADIFFAREA 0.708600 ;
    PORT
      LAYER Metal3 ;
        RECT 0.000 1263.580 0.400 1263.980 ;
    END
  END s_axil_ctrl_rdata[22]
  PIN s_axil_ctrl_rdata[23]
    DIRECTION OUTPUT ;
    USE SIGNAL ;
    ANTENNADIFFAREA 0.708600 ;
    PORT
      LAYER Metal3 ;
        RECT 0.000 1271.980 0.400 1272.380 ;
    END
  END s_axil_ctrl_rdata[23]
  PIN s_axil_ctrl_rdata[24]
    DIRECTION OUTPUT ;
    USE SIGNAL ;
    ANTENNADIFFAREA 0.708600 ;
    PORT
      LAYER Metal3 ;
        RECT 0.000 1280.380 0.400 1280.780 ;
    END
  END s_axil_ctrl_rdata[24]
  PIN s_axil_ctrl_rdata[25]
    DIRECTION OUTPUT ;
    USE SIGNAL ;
    ANTENNADIFFAREA 0.708600 ;
    PORT
      LAYER Metal3 ;
        RECT 0.000 1288.780 0.400 1289.180 ;
    END
  END s_axil_ctrl_rdata[25]
  PIN s_axil_ctrl_rdata[26]
    DIRECTION OUTPUT ;
    USE SIGNAL ;
    ANTENNADIFFAREA 0.708600 ;
    PORT
      LAYER Metal3 ;
        RECT 0.000 1297.180 0.400 1297.580 ;
    END
  END s_axil_ctrl_rdata[26]
  PIN s_axil_ctrl_rdata[27]
    DIRECTION OUTPUT ;
    USE SIGNAL ;
    ANTENNADIFFAREA 0.708600 ;
    PORT
      LAYER Metal3 ;
        RECT 0.000 1305.580 0.400 1305.980 ;
    END
  END s_axil_ctrl_rdata[27]
  PIN s_axil_ctrl_rdata[28]
    DIRECTION OUTPUT ;
    USE SIGNAL ;
    ANTENNADIFFAREA 0.708600 ;
    PORT
      LAYER Metal3 ;
        RECT 0.000 1313.980 0.400 1314.380 ;
    END
  END s_axil_ctrl_rdata[28]
  PIN s_axil_ctrl_rdata[29]
    DIRECTION OUTPUT ;
    USE SIGNAL ;
    ANTENNADIFFAREA 0.708600 ;
    PORT
      LAYER Metal3 ;
        RECT 0.000 1322.380 0.400 1322.780 ;
    END
  END s_axil_ctrl_rdata[29]
  PIN s_axil_ctrl_rdata[2]
    DIRECTION OUTPUT ;
    USE SIGNAL ;
    ANTENNADIFFAREA 0.708600 ;
    PORT
      LAYER Metal3 ;
        RECT 0.000 1095.580 0.400 1095.980 ;
    END
  END s_axil_ctrl_rdata[2]
  PIN s_axil_ctrl_rdata[30]
    DIRECTION OUTPUT ;
    USE SIGNAL ;
    ANTENNADIFFAREA 0.708600 ;
    PORT
      LAYER Metal3 ;
        RECT 0.000 1330.780 0.400 1331.180 ;
    END
  END s_axil_ctrl_rdata[30]
  PIN s_axil_ctrl_rdata[31]
    DIRECTION OUTPUT ;
    USE SIGNAL ;
    ANTENNADIFFAREA 0.708600 ;
    PORT
      LAYER Metal3 ;
        RECT 0.000 1339.180 0.400 1339.580 ;
    END
  END s_axil_ctrl_rdata[31]
  PIN s_axil_ctrl_rdata[3]
    DIRECTION OUTPUT ;
    USE SIGNAL ;
    ANTENNADIFFAREA 0.708600 ;
    PORT
      LAYER Metal3 ;
        RECT 0.000 1103.980 0.400 1104.380 ;
    END
  END s_axil_ctrl_rdata[3]
  PIN s_axil_ctrl_rdata[4]
    DIRECTION OUTPUT ;
    USE SIGNAL ;
    ANTENNADIFFAREA 0.708600 ;
    PORT
      LAYER Metal3 ;
        RECT 0.000 1112.380 0.400 1112.780 ;
    END
  END s_axil_ctrl_rdata[4]
  PIN s_axil_ctrl_rdata[5]
    DIRECTION OUTPUT ;
    USE SIGNAL ;
    ANTENNADIFFAREA 0.708600 ;
    PORT
      LAYER Metal3 ;
        RECT 0.000 1120.780 0.400 1121.180 ;
    END
  END s_axil_ctrl_rdata[5]
  PIN s_axil_ctrl_rdata[6]
    DIRECTION OUTPUT ;
    USE SIGNAL ;
    ANTENNADIFFAREA 0.708600 ;
    PORT
      LAYER Metal3 ;
        RECT 0.000 1129.180 0.400 1129.580 ;
    END
  END s_axil_ctrl_rdata[6]
  PIN s_axil_ctrl_rdata[7]
    DIRECTION OUTPUT ;
    USE SIGNAL ;
    ANTENNADIFFAREA 0.708600 ;
    PORT
      LAYER Metal3 ;
        RECT 0.000 1137.580 0.400 1137.980 ;
    END
  END s_axil_ctrl_rdata[7]
  PIN s_axil_ctrl_rdata[8]
    DIRECTION OUTPUT ;
    USE SIGNAL ;
    ANTENNADIFFAREA 0.708600 ;
    PORT
      LAYER Metal3 ;
        RECT 0.000 1145.980 0.400 1146.380 ;
    END
  END s_axil_ctrl_rdata[8]
  PIN s_axil_ctrl_rdata[9]
    DIRECTION OUTPUT ;
    USE SIGNAL ;
    ANTENNADIFFAREA 0.708600 ;
    PORT
      LAYER Metal3 ;
        RECT 0.000 1154.380 0.400 1154.780 ;
    END
  END s_axil_ctrl_rdata[9]
  PIN s_axil_ctrl_rready
    DIRECTION INPUT ;
    USE SIGNAL ;
    ANTENNAGATEAREA 0.180700 ;
    ANTENNADIFFAREA 2.015400 ;
    PORT
      LAYER Metal3 ;
        RECT 0.000 1045.180 0.400 1045.580 ;
    END
  END s_axil_ctrl_rready
  PIN s_axil_ctrl_rresp[0]
    DIRECTION OUTPUT ;
    USE SIGNAL ;
    ANTENNADIFFAREA 0.708600 ;
    PORT
      LAYER Metal3 ;
        RECT 0.000 1061.980 0.400 1062.380 ;
    END
  END s_axil_ctrl_rresp[0]
  PIN s_axil_ctrl_rresp[1]
    DIRECTION OUTPUT ;
    USE SIGNAL ;
    ANTENNADIFFAREA 0.708600 ;
    PORT
      LAYER Metal3 ;
        RECT 0.000 1070.380 0.400 1070.780 ;
    END
  END s_axil_ctrl_rresp[1]
  PIN s_axil_ctrl_rvalid
    DIRECTION OUTPUT ;
    USE SIGNAL ;
    ANTENNADIFFAREA 0.708600 ;
    PORT
      LAYER Metal3 ;
        RECT 0.000 1053.580 0.400 1053.980 ;
    END
  END s_axil_ctrl_rvalid
  PIN s_axil_ctrl_wdata[0]
    DIRECTION INPUT ;
    USE SIGNAL ;
    ANTENNAGATEAREA 0.180700 ;
    ANTENNADIFFAREA 2.015400 ;
    PORT
      LAYER Metal3 ;
        RECT 0.000 1742.380 0.400 1742.780 ;
    END
  END s_axil_ctrl_wdata[0]
  PIN s_axil_ctrl_wdata[10]
    DIRECTION INPUT ;
    USE SIGNAL ;
    ANTENNAGATEAREA 0.180700 ;
    ANTENNADIFFAREA 2.015400 ;
    PORT
      LAYER Metal3 ;
        RECT 0.000 1826.380 0.400 1826.780 ;
    END
  END s_axil_ctrl_wdata[10]
  PIN s_axil_ctrl_wdata[11]
    DIRECTION INPUT ;
    USE SIGNAL ;
    ANTENNAGATEAREA 0.180700 ;
    ANTENNADIFFAREA 4.030800 ;
    PORT
      LAYER Metal3 ;
        RECT 0.000 1834.780 0.400 1835.180 ;
    END
  END s_axil_ctrl_wdata[11]
  PIN s_axil_ctrl_wdata[12]
    DIRECTION INPUT ;
    USE SIGNAL ;
    ANTENNAGATEAREA 0.180700 ;
    ANTENNADIFFAREA 2.015400 ;
    PORT
      LAYER Metal3 ;
        RECT 0.000 1843.180 0.400 1843.580 ;
    END
  END s_axil_ctrl_wdata[12]
  PIN s_axil_ctrl_wdata[13]
    DIRECTION INPUT ;
    USE SIGNAL ;
    ANTENNAGATEAREA 0.180700 ;
    ANTENNADIFFAREA 2.015400 ;
    PORT
      LAYER Metal3 ;
        RECT 0.000 1851.580 0.400 1851.980 ;
    END
  END s_axil_ctrl_wdata[13]
  PIN s_axil_ctrl_wdata[14]
    DIRECTION INPUT ;
    USE SIGNAL ;
    ANTENNAGATEAREA 0.180700 ;
    ANTENNADIFFAREA 4.030800 ;
    PORT
      LAYER Metal3 ;
        RECT 0.000 1859.980 0.400 1860.380 ;
    END
  END s_axil_ctrl_wdata[14]
  PIN s_axil_ctrl_wdata[15]
    DIRECTION INPUT ;
    USE SIGNAL ;
    ANTENNAGATEAREA 0.180700 ;
    ANTENNADIFFAREA 2.015400 ;
    PORT
      LAYER Metal3 ;
        RECT 0.000 1868.380 0.400 1868.780 ;
    END
  END s_axil_ctrl_wdata[15]
  PIN s_axil_ctrl_wdata[16]
    DIRECTION INPUT ;
    USE SIGNAL ;
    ANTENNAGATEAREA 0.180700 ;
    ANTENNADIFFAREA 2.015400 ;
    PORT
      LAYER Metal3 ;
        RECT 0.000 1876.780 0.400 1877.180 ;
    END
  END s_axil_ctrl_wdata[16]
  PIN s_axil_ctrl_wdata[17]
    DIRECTION INPUT ;
    USE SIGNAL ;
    ANTENNAGATEAREA 0.180700 ;
    ANTENNADIFFAREA 2.015400 ;
    PORT
      LAYER Metal3 ;
        RECT 0.000 1885.180 0.400 1885.580 ;
    END
  END s_axil_ctrl_wdata[17]
  PIN s_axil_ctrl_wdata[18]
    DIRECTION INPUT ;
    USE SIGNAL ;
    ANTENNAGATEAREA 0.180700 ;
    ANTENNADIFFAREA 2.015400 ;
    PORT
      LAYER Metal3 ;
        RECT 0.000 1893.580 0.400 1893.980 ;
    END
  END s_axil_ctrl_wdata[18]
  PIN s_axil_ctrl_wdata[19]
    DIRECTION INPUT ;
    USE SIGNAL ;
    ANTENNAGATEAREA 0.180700 ;
    ANTENNADIFFAREA 2.015400 ;
    PORT
      LAYER Metal3 ;
        RECT 0.000 1901.980 0.400 1902.380 ;
    END
  END s_axil_ctrl_wdata[19]
  PIN s_axil_ctrl_wdata[1]
    DIRECTION INPUT ;
    USE SIGNAL ;
    ANTENNAGATEAREA 0.180700 ;
    ANTENNADIFFAREA 2.015400 ;
    PORT
      LAYER Metal3 ;
        RECT 0.000 1750.780 0.400 1751.180 ;
    END
  END s_axil_ctrl_wdata[1]
  PIN s_axil_ctrl_wdata[20]
    DIRECTION INPUT ;
    USE SIGNAL ;
    ANTENNAGATEAREA 0.180700 ;
    ANTENNADIFFAREA 2.015400 ;
    PORT
      LAYER Metal3 ;
        RECT 0.000 1910.380 0.400 1910.780 ;
    END
  END s_axil_ctrl_wdata[20]
  PIN s_axil_ctrl_wdata[21]
    DIRECTION INPUT ;
    USE SIGNAL ;
    ANTENNAGATEAREA 0.180700 ;
    ANTENNADIFFAREA 4.030800 ;
    PORT
      LAYER Metal3 ;
        RECT 0.000 1918.780 0.400 1919.180 ;
    END
  END s_axil_ctrl_wdata[21]
  PIN s_axil_ctrl_wdata[22]
    DIRECTION INPUT ;
    USE SIGNAL ;
    ANTENNAGATEAREA 0.180700 ;
    ANTENNADIFFAREA 2.015400 ;
    PORT
      LAYER Metal3 ;
        RECT 0.000 1927.180 0.400 1927.580 ;
    END
  END s_axil_ctrl_wdata[22]
  PIN s_axil_ctrl_wdata[23]
    DIRECTION INPUT ;
    USE SIGNAL ;
    ANTENNAGATEAREA 0.180700 ;
    ANTENNADIFFAREA 2.015400 ;
    PORT
      LAYER Metal3 ;
        RECT 0.000 1935.580 0.400 1935.980 ;
    END
  END s_axil_ctrl_wdata[23]
  PIN s_axil_ctrl_wdata[24]
    DIRECTION INPUT ;
    USE SIGNAL ;
    ANTENNAGATEAREA 0.180700 ;
    ANTENNADIFFAREA 2.015400 ;
    PORT
      LAYER Metal3 ;
        RECT 0.000 1943.980 0.400 1944.380 ;
    END
  END s_axil_ctrl_wdata[24]
  PIN s_axil_ctrl_wdata[25]
    DIRECTION INPUT ;
    USE SIGNAL ;
    ANTENNAGATEAREA 0.180700 ;
    ANTENNADIFFAREA 2.015400 ;
    PORT
      LAYER Metal3 ;
        RECT 0.000 1952.380 0.400 1952.780 ;
    END
  END s_axil_ctrl_wdata[25]
  PIN s_axil_ctrl_wdata[26]
    DIRECTION INPUT ;
    USE SIGNAL ;
    ANTENNAGATEAREA 0.180700 ;
    ANTENNADIFFAREA 4.030800 ;
    PORT
      LAYER Metal3 ;
        RECT 0.000 1960.780 0.400 1961.180 ;
    END
  END s_axil_ctrl_wdata[26]
  PIN s_axil_ctrl_wdata[27]
    DIRECTION INPUT ;
    USE SIGNAL ;
    ANTENNAGATEAREA 0.180700 ;
    ANTENNADIFFAREA 2.015400 ;
    PORT
      LAYER Metal3 ;
        RECT 0.000 1969.180 0.400 1969.580 ;
    END
  END s_axil_ctrl_wdata[27]
  PIN s_axil_ctrl_wdata[28]
    DIRECTION INPUT ;
    USE SIGNAL ;
    ANTENNAGATEAREA 0.180700 ;
    ANTENNADIFFAREA 2.015400 ;
    PORT
      LAYER Metal3 ;
        RECT 0.000 1977.580 0.400 1977.980 ;
    END
  END s_axil_ctrl_wdata[28]
  PIN s_axil_ctrl_wdata[29]
    DIRECTION INPUT ;
    USE SIGNAL ;
    ANTENNAGATEAREA 0.180700 ;
    ANTENNADIFFAREA 4.030800 ;
    PORT
      LAYER Metal3 ;
        RECT 0.000 1985.980 0.400 1986.380 ;
    END
  END s_axil_ctrl_wdata[29]
  PIN s_axil_ctrl_wdata[2]
    DIRECTION INPUT ;
    USE SIGNAL ;
    ANTENNAGATEAREA 0.180700 ;
    ANTENNADIFFAREA 2.015400 ;
    PORT
      LAYER Metal3 ;
        RECT 0.000 1759.180 0.400 1759.580 ;
    END
  END s_axil_ctrl_wdata[2]
  PIN s_axil_ctrl_wdata[30]
    DIRECTION INPUT ;
    USE SIGNAL ;
    ANTENNAGATEAREA 0.180700 ;
    ANTENNADIFFAREA 2.015400 ;
    PORT
      LAYER Metal3 ;
        RECT 0.000 1994.380 0.400 1994.780 ;
    END
  END s_axil_ctrl_wdata[30]
  PIN s_axil_ctrl_wdata[31]
    DIRECTION INPUT ;
    USE SIGNAL ;
    ANTENNAGATEAREA 0.180700 ;
    ANTENNADIFFAREA 2.015400 ;
    PORT
      LAYER Metal3 ;
        RECT 0.000 2002.780 0.400 2003.180 ;
    END
  END s_axil_ctrl_wdata[31]
  PIN s_axil_ctrl_wdata[3]
    DIRECTION INPUT ;
    USE SIGNAL ;
    ANTENNAGATEAREA 0.180700 ;
    ANTENNADIFFAREA 2.015400 ;
    PORT
      LAYER Metal3 ;
        RECT 0.000 1767.580 0.400 1767.980 ;
    END
  END s_axil_ctrl_wdata[3]
  PIN s_axil_ctrl_wdata[4]
    DIRECTION INPUT ;
    USE SIGNAL ;
    ANTENNAGATEAREA 0.180700 ;
    ANTENNADIFFAREA 4.030800 ;
    PORT
      LAYER Metal3 ;
        RECT 0.000 1775.980 0.400 1776.380 ;
    END
  END s_axil_ctrl_wdata[4]
  PIN s_axil_ctrl_wdata[5]
    DIRECTION INPUT ;
    USE SIGNAL ;
    ANTENNAGATEAREA 0.180700 ;
    ANTENNADIFFAREA 2.015400 ;
    PORT
      LAYER Metal3 ;
        RECT 0.000 1784.380 0.400 1784.780 ;
    END
  END s_axil_ctrl_wdata[5]
  PIN s_axil_ctrl_wdata[6]
    DIRECTION INPUT ;
    USE SIGNAL ;
    ANTENNAGATEAREA 0.180700 ;
    ANTENNADIFFAREA 4.030800 ;
    PORT
      LAYER Metal3 ;
        RECT 0.000 1792.780 0.400 1793.180 ;
    END
  END s_axil_ctrl_wdata[6]
  PIN s_axil_ctrl_wdata[7]
    DIRECTION INPUT ;
    USE SIGNAL ;
    ANTENNAGATEAREA 0.180700 ;
    ANTENNADIFFAREA 2.015400 ;
    PORT
      LAYER Metal3 ;
        RECT 0.000 1801.180 0.400 1801.580 ;
    END
  END s_axil_ctrl_wdata[7]
  PIN s_axil_ctrl_wdata[8]
    DIRECTION INPUT ;
    USE SIGNAL ;
    ANTENNAGATEAREA 0.180700 ;
    ANTENNADIFFAREA 2.015400 ;
    PORT
      LAYER Metal3 ;
        RECT 0.000 1809.580 0.400 1809.980 ;
    END
  END s_axil_ctrl_wdata[8]
  PIN s_axil_ctrl_wdata[9]
    DIRECTION INPUT ;
    USE SIGNAL ;
    ANTENNAGATEAREA 0.180700 ;
    ANTENNADIFFAREA 2.015400 ;
    PORT
      LAYER Metal3 ;
        RECT 0.000 1817.980 0.400 1818.380 ;
    END
  END s_axil_ctrl_wdata[9]
  PIN s_axil_ctrl_wready
    DIRECTION OUTPUT ;
    USE SIGNAL ;
    ANTENNADIFFAREA 0.708600 ;
    PORT
      LAYER Metal3 ;
        RECT 0.000 1691.980 0.400 1692.380 ;
    END
  END s_axil_ctrl_wready
  PIN s_axil_ctrl_wstrb[0]
    DIRECTION INPUT ;
    USE SIGNAL ;
    ANTENNAGATEAREA 0.180700 ;
    ANTENNADIFFAREA 2.015400 ;
    PORT
      LAYER Metal3 ;
        RECT 0.000 1708.780 0.400 1709.180 ;
    END
  END s_axil_ctrl_wstrb[0]
  PIN s_axil_ctrl_wstrb[1]
    DIRECTION INPUT ;
    USE SIGNAL ;
    ANTENNAGATEAREA 0.180700 ;
    ANTENNADIFFAREA 4.030800 ;
    PORT
      LAYER Metal3 ;
        RECT 0.000 1717.180 0.400 1717.580 ;
    END
  END s_axil_ctrl_wstrb[1]
  PIN s_axil_ctrl_wstrb[2]
    DIRECTION INPUT ;
    USE SIGNAL ;
    ANTENNAGATEAREA 0.180700 ;
    ANTENNADIFFAREA 2.015400 ;
    PORT
      LAYER Metal3 ;
        RECT 0.000 1725.580 0.400 1725.980 ;
    END
  END s_axil_ctrl_wstrb[2]
  PIN s_axil_ctrl_wstrb[3]
    DIRECTION INPUT ;
    USE SIGNAL ;
    ANTENNAGATEAREA 0.180700 ;
    ANTENNADIFFAREA 2.015400 ;
    PORT
      LAYER Metal3 ;
        RECT 0.000 1733.980 0.400 1734.380 ;
    END
  END s_axil_ctrl_wstrb[3]
  PIN s_axil_ctrl_wvalid
    DIRECTION INPUT ;
    USE SIGNAL ;
    ANTENNAGATEAREA 0.180700 ;
    ANTENNADIFFAREA 2.015400 ;
    PORT
      LAYER Metal3 ;
        RECT 0.000 1700.380 0.400 1700.780 ;
    END
  END s_axil_ctrl_wvalid
  PIN s_axil_mgr_araddr[0]
    DIRECTION INPUT ;
    USE SIGNAL ;
    PORT
      LAYER Metal3 ;
        RECT 0.000 112.780 0.400 113.180 ;
    END
  END s_axil_mgr_araddr[0]
  PIN s_axil_mgr_araddr[10]
    DIRECTION INPUT ;
    USE SIGNAL ;
    ANTENNAGATEAREA 0.180700 ;
    ANTENNADIFFAREA 2.015400 ;
    PORT
      LAYER Metal3 ;
        RECT 0.000 196.780 0.400 197.180 ;
    END
  END s_axil_mgr_araddr[10]
  PIN s_axil_mgr_araddr[11]
    DIRECTION INPUT ;
    USE SIGNAL ;
    ANTENNAGATEAREA 0.180700 ;
    ANTENNADIFFAREA 2.015400 ;
    PORT
      LAYER Metal3 ;
        RECT 0.000 205.180 0.400 205.580 ;
    END
  END s_axil_mgr_araddr[11]
  PIN s_axil_mgr_araddr[12]
    DIRECTION INPUT ;
    USE SIGNAL ;
    ANTENNAGATEAREA 0.180700 ;
    ANTENNADIFFAREA 2.015400 ;
    PORT
      LAYER Metal3 ;
        RECT 0.000 213.580 0.400 213.980 ;
    END
  END s_axil_mgr_araddr[12]
  PIN s_axil_mgr_araddr[13]
    DIRECTION INPUT ;
    USE SIGNAL ;
    ANTENNAGATEAREA 0.180700 ;
    ANTENNADIFFAREA 2.015400 ;
    PORT
      LAYER Metal3 ;
        RECT 0.000 221.980 0.400 222.380 ;
    END
  END s_axil_mgr_araddr[13]
  PIN s_axil_mgr_araddr[14]
    DIRECTION INPUT ;
    USE SIGNAL ;
    ANTENNAGATEAREA 0.180700 ;
    ANTENNADIFFAREA 4.030800 ;
    PORT
      LAYER Metal3 ;
        RECT 0.000 230.380 0.400 230.780 ;
    END
  END s_axil_mgr_araddr[14]
  PIN s_axil_mgr_araddr[15]
    DIRECTION INPUT ;
    USE SIGNAL ;
    ANTENNAGATEAREA 0.180700 ;
    ANTENNADIFFAREA 2.015400 ;
    PORT
      LAYER Metal3 ;
        RECT 0.000 238.780 0.400 239.180 ;
    END
  END s_axil_mgr_araddr[15]
  PIN s_axil_mgr_araddr[16]
    DIRECTION INPUT ;
    USE SIGNAL ;
    PORT
      LAYER Metal3 ;
        RECT 0.000 247.180 0.400 247.580 ;
    END
  END s_axil_mgr_araddr[16]
  PIN s_axil_mgr_araddr[17]
    DIRECTION INPUT ;
    USE SIGNAL ;
    PORT
      LAYER Metal3 ;
        RECT 0.000 255.580 0.400 255.980 ;
    END
  END s_axil_mgr_araddr[17]
  PIN s_axil_mgr_araddr[18]
    DIRECTION INPUT ;
    USE SIGNAL ;
    PORT
      LAYER Metal3 ;
        RECT 0.000 263.980 0.400 264.380 ;
    END
  END s_axil_mgr_araddr[18]
  PIN s_axil_mgr_araddr[19]
    DIRECTION INPUT ;
    USE SIGNAL ;
    PORT
      LAYER Metal3 ;
        RECT 0.000 272.380 0.400 272.780 ;
    END
  END s_axil_mgr_araddr[19]
  PIN s_axil_mgr_araddr[1]
    DIRECTION INPUT ;
    USE SIGNAL ;
    PORT
      LAYER Metal3 ;
        RECT 0.000 121.180 0.400 121.580 ;
    END
  END s_axil_mgr_araddr[1]
  PIN s_axil_mgr_araddr[20]
    DIRECTION INPUT ;
    USE SIGNAL ;
    PORT
      LAYER Metal3 ;
        RECT 0.000 280.780 0.400 281.180 ;
    END
  END s_axil_mgr_araddr[20]
  PIN s_axil_mgr_araddr[21]
    DIRECTION INPUT ;
    USE SIGNAL ;
    PORT
      LAYER Metal3 ;
        RECT 0.000 289.180 0.400 289.580 ;
    END
  END s_axil_mgr_araddr[21]
  PIN s_axil_mgr_araddr[22]
    DIRECTION INPUT ;
    USE SIGNAL ;
    PORT
      LAYER Metal3 ;
        RECT 0.000 297.580 0.400 297.980 ;
    END
  END s_axil_mgr_araddr[22]
  PIN s_axil_mgr_araddr[23]
    DIRECTION INPUT ;
    USE SIGNAL ;
    PORT
      LAYER Metal3 ;
        RECT 0.000 305.980 0.400 306.380 ;
    END
  END s_axil_mgr_araddr[23]
  PIN s_axil_mgr_araddr[24]
    DIRECTION INPUT ;
    USE SIGNAL ;
    PORT
      LAYER Metal3 ;
        RECT 0.000 314.380 0.400 314.780 ;
    END
  END s_axil_mgr_araddr[24]
  PIN s_axil_mgr_araddr[25]
    DIRECTION INPUT ;
    USE SIGNAL ;
    PORT
      LAYER Metal3 ;
        RECT 0.000 322.780 0.400 323.180 ;
    END
  END s_axil_mgr_araddr[25]
  PIN s_axil_mgr_araddr[26]
    DIRECTION INPUT ;
    USE SIGNAL ;
    PORT
      LAYER Metal3 ;
        RECT 0.000 331.180 0.400 331.580 ;
    END
  END s_axil_mgr_araddr[26]
  PIN s_axil_mgr_araddr[27]
    DIRECTION INPUT ;
    USE SIGNAL ;
    PORT
      LAYER Metal3 ;
        RECT 0.000 339.580 0.400 339.980 ;
    END
  END s_axil_mgr_araddr[27]
  PIN s_axil_mgr_araddr[28]
    DIRECTION INPUT ;
    USE SIGNAL ;
    PORT
      LAYER Metal3 ;
        RECT 0.000 347.980 0.400 348.380 ;
    END
  END s_axil_mgr_araddr[28]
  PIN s_axil_mgr_araddr[29]
    DIRECTION INPUT ;
    USE SIGNAL ;
    PORT
      LAYER Metal3 ;
        RECT 0.000 356.380 0.400 356.780 ;
    END
  END s_axil_mgr_araddr[29]
  PIN s_axil_mgr_araddr[2]
    DIRECTION INPUT ;
    USE SIGNAL ;
    ANTENNAGATEAREA 0.180700 ;
    ANTENNADIFFAREA 2.015400 ;
    PORT
      LAYER Metal3 ;
        RECT 0.000 129.580 0.400 129.980 ;
    END
  END s_axil_mgr_araddr[2]
  PIN s_axil_mgr_araddr[30]
    DIRECTION INPUT ;
    USE SIGNAL ;
    PORT
      LAYER Metal3 ;
        RECT 0.000 364.780 0.400 365.180 ;
    END
  END s_axil_mgr_araddr[30]
  PIN s_axil_mgr_araddr[31]
    DIRECTION INPUT ;
    USE SIGNAL ;
    PORT
      LAYER Metal3 ;
        RECT 0.000 373.180 0.400 373.580 ;
    END
  END s_axil_mgr_araddr[31]
  PIN s_axil_mgr_araddr[3]
    DIRECTION INPUT ;
    USE SIGNAL ;
    ANTENNAGATEAREA 0.180700 ;
    ANTENNADIFFAREA 2.015400 ;
    PORT
      LAYER Metal3 ;
        RECT 0.000 137.980 0.400 138.380 ;
    END
  END s_axil_mgr_araddr[3]
  PIN s_axil_mgr_araddr[4]
    DIRECTION INPUT ;
    USE SIGNAL ;
    ANTENNAGATEAREA 0.180700 ;
    ANTENNADIFFAREA 2.015400 ;
    PORT
      LAYER Metal3 ;
        RECT 0.000 146.380 0.400 146.780 ;
    END
  END s_axil_mgr_araddr[4]
  PIN s_axil_mgr_araddr[5]
    DIRECTION INPUT ;
    USE SIGNAL ;
    ANTENNAGATEAREA 0.180700 ;
    ANTENNADIFFAREA 2.015400 ;
    PORT
      LAYER Metal3 ;
        RECT 0.000 154.780 0.400 155.180 ;
    END
  END s_axil_mgr_araddr[5]
  PIN s_axil_mgr_araddr[6]
    DIRECTION INPUT ;
    USE SIGNAL ;
    ANTENNAGATEAREA 0.180700 ;
    ANTENNADIFFAREA 2.015400 ;
    PORT
      LAYER Metal3 ;
        RECT 0.000 163.180 0.400 163.580 ;
    END
  END s_axil_mgr_araddr[6]
  PIN s_axil_mgr_araddr[7]
    DIRECTION INPUT ;
    USE SIGNAL ;
    ANTENNAGATEAREA 0.180700 ;
    ANTENNADIFFAREA 2.015400 ;
    PORT
      LAYER Metal3 ;
        RECT 0.000 171.580 0.400 171.980 ;
    END
  END s_axil_mgr_araddr[7]
  PIN s_axil_mgr_araddr[8]
    DIRECTION INPUT ;
    USE SIGNAL ;
    ANTENNAGATEAREA 0.180700 ;
    ANTENNADIFFAREA 2.015400 ;
    PORT
      LAYER Metal3 ;
        RECT 0.000 179.980 0.400 180.380 ;
    END
  END s_axil_mgr_araddr[8]
  PIN s_axil_mgr_araddr[9]
    DIRECTION INPUT ;
    USE SIGNAL ;
    ANTENNAGATEAREA 0.180700 ;
    ANTENNADIFFAREA 2.015400 ;
    PORT
      LAYER Metal3 ;
        RECT 0.000 188.380 0.400 188.780 ;
    END
  END s_axil_mgr_araddr[9]
  PIN s_axil_mgr_arprot[0]
    DIRECTION INPUT ;
    USE SIGNAL ;
    PORT
      LAYER Metal3 ;
        RECT 0.000 87.580 0.400 87.980 ;
    END
  END s_axil_mgr_arprot[0]
  PIN s_axil_mgr_arprot[1]
    DIRECTION INPUT ;
    USE SIGNAL ;
    PORT
      LAYER Metal3 ;
        RECT 0.000 95.980 0.400 96.380 ;
    END
  END s_axil_mgr_arprot[1]
  PIN s_axil_mgr_arprot[2]
    DIRECTION INPUT ;
    USE SIGNAL ;
    PORT
      LAYER Metal3 ;
        RECT 0.000 104.380 0.400 104.780 ;
    END
  END s_axil_mgr_arprot[2]
  PIN s_axil_mgr_arready
    DIRECTION OUTPUT ;
    USE SIGNAL ;
    ANTENNADIFFAREA 0.708600 ;
    PORT
      LAYER Metal3 ;
        RECT 0.000 70.780 0.400 71.180 ;
    END
  END s_axil_mgr_arready
  PIN s_axil_mgr_arvalid
    DIRECTION INPUT ;
    USE SIGNAL ;
    ANTENNAGATEAREA 0.180700 ;
    ANTENNADIFFAREA 2.015400 ;
    PORT
      LAYER Metal3 ;
        RECT 0.000 79.180 0.400 79.580 ;
    END
  END s_axil_mgr_arvalid
  PIN s_axil_mgr_awaddr[0]
    DIRECTION INPUT ;
    USE SIGNAL ;
    PORT
      LAYER Metal3 ;
        RECT 0.000 776.380 0.400 776.780 ;
    END
  END s_axil_mgr_awaddr[0]
  PIN s_axil_mgr_awaddr[10]
    DIRECTION INPUT ;
    USE SIGNAL ;
    ANTENNAGATEAREA 0.180700 ;
    ANTENNADIFFAREA 2.015400 ;
    PORT
      LAYER Metal3 ;
        RECT 0.000 860.380 0.400 860.780 ;
    END
  END s_axil_mgr_awaddr[10]
  PIN s_axil_mgr_awaddr[11]
    DIRECTION INPUT ;
    USE SIGNAL ;
    ANTENNAGATEAREA 0.180700 ;
    ANTENNADIFFAREA 2.015400 ;
    PORT
      LAYER Metal3 ;
        RECT 0.000 868.780 0.400 869.180 ;
    END
  END s_axil_mgr_awaddr[11]
  PIN s_axil_mgr_awaddr[12]
    DIRECTION INPUT ;
    USE SIGNAL ;
    ANTENNAGATEAREA 0.180700 ;
    ANTENNADIFFAREA 2.015400 ;
    PORT
      LAYER Metal3 ;
        RECT 0.000 877.180 0.400 877.580 ;
    END
  END s_axil_mgr_awaddr[12]
  PIN s_axil_mgr_awaddr[13]
    DIRECTION INPUT ;
    USE SIGNAL ;
    ANTENNAGATEAREA 0.180700 ;
    ANTENNADIFFAREA 4.030800 ;
    PORT
      LAYER Metal3 ;
        RECT 0.000 885.580 0.400 885.980 ;
    END
  END s_axil_mgr_awaddr[13]
  PIN s_axil_mgr_awaddr[14]
    DIRECTION INPUT ;
    USE SIGNAL ;
    ANTENNAGATEAREA 0.180700 ;
    ANTENNADIFFAREA 2.015400 ;
    PORT
      LAYER Metal3 ;
        RECT 0.000 893.980 0.400 894.380 ;
    END
  END s_axil_mgr_awaddr[14]
  PIN s_axil_mgr_awaddr[15]
    DIRECTION INPUT ;
    USE SIGNAL ;
    ANTENNAGATEAREA 0.180700 ;
    ANTENNADIFFAREA 2.015400 ;
    PORT
      LAYER Metal3 ;
        RECT 0.000 902.380 0.400 902.780 ;
    END
  END s_axil_mgr_awaddr[15]
  PIN s_axil_mgr_awaddr[16]
    DIRECTION INPUT ;
    USE SIGNAL ;
    PORT
      LAYER Metal3 ;
        RECT 0.000 910.780 0.400 911.180 ;
    END
  END s_axil_mgr_awaddr[16]
  PIN s_axil_mgr_awaddr[17]
    DIRECTION INPUT ;
    USE SIGNAL ;
    PORT
      LAYER Metal3 ;
        RECT 0.000 919.180 0.400 919.580 ;
    END
  END s_axil_mgr_awaddr[17]
  PIN s_axil_mgr_awaddr[18]
    DIRECTION INPUT ;
    USE SIGNAL ;
    PORT
      LAYER Metal3 ;
        RECT 0.000 927.580 0.400 927.980 ;
    END
  END s_axil_mgr_awaddr[18]
  PIN s_axil_mgr_awaddr[19]
    DIRECTION INPUT ;
    USE SIGNAL ;
    PORT
      LAYER Metal3 ;
        RECT 0.000 935.980 0.400 936.380 ;
    END
  END s_axil_mgr_awaddr[19]
  PIN s_axil_mgr_awaddr[1]
    DIRECTION INPUT ;
    USE SIGNAL ;
    PORT
      LAYER Metal3 ;
        RECT 0.000 784.780 0.400 785.180 ;
    END
  END s_axil_mgr_awaddr[1]
  PIN s_axil_mgr_awaddr[20]
    DIRECTION INPUT ;
    USE SIGNAL ;
    PORT
      LAYER Metal3 ;
        RECT 0.000 944.380 0.400 944.780 ;
    END
  END s_axil_mgr_awaddr[20]
  PIN s_axil_mgr_awaddr[21]
    DIRECTION INPUT ;
    USE SIGNAL ;
    PORT
      LAYER Metal3 ;
        RECT 0.000 952.780 0.400 953.180 ;
    END
  END s_axil_mgr_awaddr[21]
  PIN s_axil_mgr_awaddr[22]
    DIRECTION INPUT ;
    USE SIGNAL ;
    PORT
      LAYER Metal3 ;
        RECT 0.000 961.180 0.400 961.580 ;
    END
  END s_axil_mgr_awaddr[22]
  PIN s_axil_mgr_awaddr[23]
    DIRECTION INPUT ;
    USE SIGNAL ;
    PORT
      LAYER Metal3 ;
        RECT 0.000 969.580 0.400 969.980 ;
    END
  END s_axil_mgr_awaddr[23]
  PIN s_axil_mgr_awaddr[24]
    DIRECTION INPUT ;
    USE SIGNAL ;
    PORT
      LAYER Metal3 ;
        RECT 0.000 977.980 0.400 978.380 ;
    END
  END s_axil_mgr_awaddr[24]
  PIN s_axil_mgr_awaddr[25]
    DIRECTION INPUT ;
    USE SIGNAL ;
    PORT
      LAYER Metal3 ;
        RECT 0.000 986.380 0.400 986.780 ;
    END
  END s_axil_mgr_awaddr[25]
  PIN s_axil_mgr_awaddr[26]
    DIRECTION INPUT ;
    USE SIGNAL ;
    PORT
      LAYER Metal3 ;
        RECT 0.000 994.780 0.400 995.180 ;
    END
  END s_axil_mgr_awaddr[26]
  PIN s_axil_mgr_awaddr[27]
    DIRECTION INPUT ;
    USE SIGNAL ;
    PORT
      LAYER Metal3 ;
        RECT 0.000 1003.180 0.400 1003.580 ;
    END
  END s_axil_mgr_awaddr[27]
  PIN s_axil_mgr_awaddr[28]
    DIRECTION INPUT ;
    USE SIGNAL ;
    PORT
      LAYER Metal3 ;
        RECT 0.000 1011.580 0.400 1011.980 ;
    END
  END s_axil_mgr_awaddr[28]
  PIN s_axil_mgr_awaddr[29]
    DIRECTION INPUT ;
    USE SIGNAL ;
    PORT
      LAYER Metal3 ;
        RECT 0.000 1019.980 0.400 1020.380 ;
    END
  END s_axil_mgr_awaddr[29]
  PIN s_axil_mgr_awaddr[2]
    DIRECTION INPUT ;
    USE SIGNAL ;
    ANTENNAGATEAREA 0.180700 ;
    ANTENNADIFFAREA 2.015400 ;
    PORT
      LAYER Metal3 ;
        RECT 0.000 793.180 0.400 793.580 ;
    END
  END s_axil_mgr_awaddr[2]
  PIN s_axil_mgr_awaddr[30]
    DIRECTION INPUT ;
    USE SIGNAL ;
    PORT
      LAYER Metal3 ;
        RECT 0.000 1028.380 0.400 1028.780 ;
    END
  END s_axil_mgr_awaddr[30]
  PIN s_axil_mgr_awaddr[31]
    DIRECTION INPUT ;
    USE SIGNAL ;
    PORT
      LAYER Metal3 ;
        RECT 0.000 1036.780 0.400 1037.180 ;
    END
  END s_axil_mgr_awaddr[31]
  PIN s_axil_mgr_awaddr[3]
    DIRECTION INPUT ;
    USE SIGNAL ;
    ANTENNAGATEAREA 0.180700 ;
    ANTENNADIFFAREA 2.015400 ;
    PORT
      LAYER Metal3 ;
        RECT 0.000 801.580 0.400 801.980 ;
    END
  END s_axil_mgr_awaddr[3]
  PIN s_axil_mgr_awaddr[4]
    DIRECTION INPUT ;
    USE SIGNAL ;
    ANTENNAGATEAREA 0.180700 ;
    ANTENNADIFFAREA 2.015400 ;
    PORT
      LAYER Metal3 ;
        RECT 0.000 809.980 0.400 810.380 ;
    END
  END s_axil_mgr_awaddr[4]
  PIN s_axil_mgr_awaddr[5]
    DIRECTION INPUT ;
    USE SIGNAL ;
    ANTENNAGATEAREA 0.180700 ;
    ANTENNADIFFAREA 2.015400 ;
    PORT
      LAYER Metal3 ;
        RECT 0.000 818.380 0.400 818.780 ;
    END
  END s_axil_mgr_awaddr[5]
  PIN s_axil_mgr_awaddr[6]
    DIRECTION INPUT ;
    USE SIGNAL ;
    ANTENNAGATEAREA 0.180700 ;
    ANTENNADIFFAREA 2.015400 ;
    PORT
      LAYER Metal3 ;
        RECT 0.000 826.780 0.400 827.180 ;
    END
  END s_axil_mgr_awaddr[6]
  PIN s_axil_mgr_awaddr[7]
    DIRECTION INPUT ;
    USE SIGNAL ;
    ANTENNAGATEAREA 0.180700 ;
    ANTENNADIFFAREA 2.015400 ;
    PORT
      LAYER Metal3 ;
        RECT 0.000 835.180 0.400 835.580 ;
    END
  END s_axil_mgr_awaddr[7]
  PIN s_axil_mgr_awaddr[8]
    DIRECTION INPUT ;
    USE SIGNAL ;
    ANTENNAGATEAREA 0.180700 ;
    ANTENNADIFFAREA 4.030800 ;
    PORT
      LAYER Metal3 ;
        RECT 0.000 843.580 0.400 843.980 ;
    END
  END s_axil_mgr_awaddr[8]
  PIN s_axil_mgr_awaddr[9]
    DIRECTION INPUT ;
    USE SIGNAL ;
    ANTENNAGATEAREA 0.180700 ;
    ANTENNADIFFAREA 2.015400 ;
    PORT
      LAYER Metal3 ;
        RECT 0.000 851.980 0.400 852.380 ;
    END
  END s_axil_mgr_awaddr[9]
  PIN s_axil_mgr_awprot[0]
    DIRECTION INPUT ;
    USE SIGNAL ;
    PORT
      LAYER Metal3 ;
        RECT 0.000 751.180 0.400 751.580 ;
    END
  END s_axil_mgr_awprot[0]
  PIN s_axil_mgr_awprot[1]
    DIRECTION INPUT ;
    USE SIGNAL ;
    PORT
      LAYER Metal3 ;
        RECT 0.000 759.580 0.400 759.980 ;
    END
  END s_axil_mgr_awprot[1]
  PIN s_axil_mgr_awprot[2]
    DIRECTION INPUT ;
    USE SIGNAL ;
    PORT
      LAYER Metal3 ;
        RECT 0.000 767.980 0.400 768.380 ;
    END
  END s_axil_mgr_awprot[2]
  PIN s_axil_mgr_awready
    DIRECTION OUTPUT ;
    USE SIGNAL ;
    ANTENNADIFFAREA 0.708600 ;
    PORT
      LAYER Metal3 ;
        RECT 0.000 734.380 0.400 734.780 ;
    END
  END s_axil_mgr_awready
  PIN s_axil_mgr_awvalid
    DIRECTION INPUT ;
    USE SIGNAL ;
    ANTENNAGATEAREA 0.180700 ;
    ANTENNADIFFAREA 2.015400 ;
    PORT
      LAYER Metal3 ;
        RECT 0.000 742.780 0.400 743.180 ;
    END
  END s_axil_mgr_awvalid
  PIN s_axil_mgr_bready
    DIRECTION INPUT ;
    USE SIGNAL ;
    ANTENNAGATEAREA 0.180700 ;
    ANTENNADIFFAREA 2.015400 ;
    PORT
      LAYER Metal3 ;
        RECT 0.000 381.580 0.400 381.980 ;
    END
  END s_axil_mgr_bready
  PIN s_axil_mgr_bresp[0]
    DIRECTION OUTPUT ;
    USE SIGNAL ;
    ANTENNADIFFAREA 0.299200 ;
    PORT
      LAYER Metal3 ;
        RECT 0.000 398.380 0.400 398.780 ;
    END
  END s_axil_mgr_bresp[0]
  PIN s_axil_mgr_bresp[1]
    DIRECTION OUTPUT ;
    USE SIGNAL ;
    ANTENNADIFFAREA 0.299200 ;
    PORT
      LAYER Metal3 ;
        RECT 0.000 406.780 0.400 407.180 ;
    END
  END s_axil_mgr_bresp[1]
  PIN s_axil_mgr_bvalid
    DIRECTION OUTPUT ;
    USE SIGNAL ;
    ANTENNADIFFAREA 0.708600 ;
    PORT
      LAYER Metal3 ;
        RECT 0.000 389.980 0.400 390.380 ;
    END
  END s_axil_mgr_bvalid
  PIN s_axil_mgr_rdata[0]
    DIRECTION OUTPUT ;
    USE SIGNAL ;
    ANTENNADIFFAREA 0.708600 ;
    PORT
      LAYER Metal2 ;
        RECT 76.120 0.000 76.520 0.400 ;
    END
  END s_axil_mgr_rdata[0]
  PIN s_axil_mgr_rdata[10]
    DIRECTION OUTPUT ;
    USE SIGNAL ;
    ANTENNADIFFAREA 0.708600 ;
    PORT
      LAYER Metal2 ;
        RECT 124.120 0.000 124.520 0.400 ;
    END
  END s_axil_mgr_rdata[10]
  PIN s_axil_mgr_rdata[11]
    DIRECTION OUTPUT ;
    USE SIGNAL ;
    ANTENNADIFFAREA 0.708600 ;
    PORT
      LAYER Metal2 ;
        RECT 128.920 0.000 129.320 0.400 ;
    END
  END s_axil_mgr_rdata[11]
  PIN s_axil_mgr_rdata[12]
    DIRECTION OUTPUT ;
    USE SIGNAL ;
    ANTENNADIFFAREA 0.708600 ;
    PORT
      LAYER Metal2 ;
        RECT 133.720 0.000 134.120 0.400 ;
    END
  END s_axil_mgr_rdata[12]
  PIN s_axil_mgr_rdata[13]
    DIRECTION OUTPUT ;
    USE SIGNAL ;
    ANTENNADIFFAREA 0.708600 ;
    PORT
      LAYER Metal2 ;
        RECT 138.520 0.000 138.920 0.400 ;
    END
  END s_axil_mgr_rdata[13]
  PIN s_axil_mgr_rdata[14]
    DIRECTION OUTPUT ;
    USE SIGNAL ;
    ANTENNADIFFAREA 0.708600 ;
    PORT
      LAYER Metal2 ;
        RECT 143.320 0.000 143.720 0.400 ;
    END
  END s_axil_mgr_rdata[14]
  PIN s_axil_mgr_rdata[15]
    DIRECTION OUTPUT ;
    USE SIGNAL ;
    ANTENNADIFFAREA 0.708600 ;
    PORT
      LAYER Metal2 ;
        RECT 148.120 0.000 148.520 0.400 ;
    END
  END s_axil_mgr_rdata[15]
  PIN s_axil_mgr_rdata[16]
    DIRECTION OUTPUT ;
    USE SIGNAL ;
    ANTENNADIFFAREA 0.708600 ;
    PORT
      LAYER Metal2 ;
        RECT 152.920 0.000 153.320 0.400 ;
    END
  END s_axil_mgr_rdata[16]
  PIN s_axil_mgr_rdata[17]
    DIRECTION OUTPUT ;
    USE SIGNAL ;
    ANTENNADIFFAREA 0.708600 ;
    PORT
      LAYER Metal2 ;
        RECT 157.720 0.000 158.120 0.400 ;
    END
  END s_axil_mgr_rdata[17]
  PIN s_axil_mgr_rdata[18]
    DIRECTION OUTPUT ;
    USE SIGNAL ;
    ANTENNADIFFAREA 0.708600 ;
    PORT
      LAYER Metal2 ;
        RECT 162.520 0.000 162.920 0.400 ;
    END
  END s_axil_mgr_rdata[18]
  PIN s_axil_mgr_rdata[19]
    DIRECTION OUTPUT ;
    USE SIGNAL ;
    ANTENNADIFFAREA 0.708600 ;
    PORT
      LAYER Metal2 ;
        RECT 167.320 0.000 167.720 0.400 ;
    END
  END s_axil_mgr_rdata[19]
  PIN s_axil_mgr_rdata[1]
    DIRECTION OUTPUT ;
    USE SIGNAL ;
    ANTENNADIFFAREA 0.708600 ;
    PORT
      LAYER Metal2 ;
        RECT 80.920 0.000 81.320 0.400 ;
    END
  END s_axil_mgr_rdata[1]
  PIN s_axil_mgr_rdata[20]
    DIRECTION OUTPUT ;
    USE SIGNAL ;
    ANTENNADIFFAREA 0.708600 ;
    PORT
      LAYER Metal2 ;
        RECT 172.120 0.000 172.520 0.400 ;
    END
  END s_axil_mgr_rdata[20]
  PIN s_axil_mgr_rdata[21]
    DIRECTION OUTPUT ;
    USE SIGNAL ;
    ANTENNADIFFAREA 0.708600 ;
    PORT
      LAYER Metal2 ;
        RECT 176.920 0.000 177.320 0.400 ;
    END
  END s_axil_mgr_rdata[21]
  PIN s_axil_mgr_rdata[22]
    DIRECTION OUTPUT ;
    USE SIGNAL ;
    ANTENNADIFFAREA 0.708600 ;
    PORT
      LAYER Metal2 ;
        RECT 181.720 0.000 182.120 0.400 ;
    END
  END s_axil_mgr_rdata[22]
  PIN s_axil_mgr_rdata[23]
    DIRECTION OUTPUT ;
    USE SIGNAL ;
    ANTENNADIFFAREA 0.708600 ;
    PORT
      LAYER Metal2 ;
        RECT 186.520 0.000 186.920 0.400 ;
    END
  END s_axil_mgr_rdata[23]
  PIN s_axil_mgr_rdata[24]
    DIRECTION OUTPUT ;
    USE SIGNAL ;
    ANTENNADIFFAREA 0.708600 ;
    PORT
      LAYER Metal2 ;
        RECT 191.320 0.000 191.720 0.400 ;
    END
  END s_axil_mgr_rdata[24]
  PIN s_axil_mgr_rdata[25]
    DIRECTION OUTPUT ;
    USE SIGNAL ;
    ANTENNADIFFAREA 0.708600 ;
    PORT
      LAYER Metal2 ;
        RECT 196.120 0.000 196.520 0.400 ;
    END
  END s_axil_mgr_rdata[25]
  PIN s_axil_mgr_rdata[26]
    DIRECTION OUTPUT ;
    USE SIGNAL ;
    ANTENNADIFFAREA 0.708600 ;
    PORT
      LAYER Metal2 ;
        RECT 200.920 0.000 201.320 0.400 ;
    END
  END s_axil_mgr_rdata[26]
  PIN s_axil_mgr_rdata[27]
    DIRECTION OUTPUT ;
    USE SIGNAL ;
    ANTENNADIFFAREA 0.708600 ;
    PORT
      LAYER Metal2 ;
        RECT 205.720 0.000 206.120 0.400 ;
    END
  END s_axil_mgr_rdata[27]
  PIN s_axil_mgr_rdata[28]
    DIRECTION OUTPUT ;
    USE SIGNAL ;
    ANTENNADIFFAREA 0.708600 ;
    PORT
      LAYER Metal2 ;
        RECT 210.520 0.000 210.920 0.400 ;
    END
  END s_axil_mgr_rdata[28]
  PIN s_axil_mgr_rdata[29]
    DIRECTION OUTPUT ;
    USE SIGNAL ;
    ANTENNADIFFAREA 0.708600 ;
    PORT
      LAYER Metal2 ;
        RECT 215.320 0.000 215.720 0.400 ;
    END
  END s_axil_mgr_rdata[29]
  PIN s_axil_mgr_rdata[2]
    DIRECTION OUTPUT ;
    USE SIGNAL ;
    ANTENNADIFFAREA 0.708600 ;
    PORT
      LAYER Metal2 ;
        RECT 85.720 0.000 86.120 0.400 ;
    END
  END s_axil_mgr_rdata[2]
  PIN s_axil_mgr_rdata[30]
    DIRECTION OUTPUT ;
    USE SIGNAL ;
    ANTENNADIFFAREA 0.708600 ;
    PORT
      LAYER Metal2 ;
        RECT 220.120 0.000 220.520 0.400 ;
    END
  END s_axil_mgr_rdata[30]
  PIN s_axil_mgr_rdata[31]
    DIRECTION OUTPUT ;
    USE SIGNAL ;
    ANTENNADIFFAREA 0.708600 ;
    PORT
      LAYER Metal2 ;
        RECT 224.920 0.000 225.320 0.400 ;
    END
  END s_axil_mgr_rdata[31]
  PIN s_axil_mgr_rdata[3]
    DIRECTION OUTPUT ;
    USE SIGNAL ;
    ANTENNADIFFAREA 0.708600 ;
    PORT
      LAYER Metal2 ;
        RECT 90.520 0.000 90.920 0.400 ;
    END
  END s_axil_mgr_rdata[3]
  PIN s_axil_mgr_rdata[4]
    DIRECTION OUTPUT ;
    USE SIGNAL ;
    ANTENNADIFFAREA 0.708600 ;
    PORT
      LAYER Metal2 ;
        RECT 95.320 0.000 95.720 0.400 ;
    END
  END s_axil_mgr_rdata[4]
  PIN s_axil_mgr_rdata[5]
    DIRECTION OUTPUT ;
    USE SIGNAL ;
    ANTENNADIFFAREA 0.708600 ;
    PORT
      LAYER Metal2 ;
        RECT 100.120 0.000 100.520 0.400 ;
    END
  END s_axil_mgr_rdata[5]
  PIN s_axil_mgr_rdata[6]
    DIRECTION OUTPUT ;
    USE SIGNAL ;
    ANTENNADIFFAREA 0.708600 ;
    PORT
      LAYER Metal2 ;
        RECT 104.920 0.000 105.320 0.400 ;
    END
  END s_axil_mgr_rdata[6]
  PIN s_axil_mgr_rdata[7]
    DIRECTION OUTPUT ;
    USE SIGNAL ;
    ANTENNADIFFAREA 0.708600 ;
    PORT
      LAYER Metal2 ;
        RECT 109.720 0.000 110.120 0.400 ;
    END
  END s_axil_mgr_rdata[7]
  PIN s_axil_mgr_rdata[8]
    DIRECTION OUTPUT ;
    USE SIGNAL ;
    ANTENNADIFFAREA 0.708600 ;
    PORT
      LAYER Metal2 ;
        RECT 114.520 0.000 114.920 0.400 ;
    END
  END s_axil_mgr_rdata[8]
  PIN s_axil_mgr_rdata[9]
    DIRECTION OUTPUT ;
    USE SIGNAL ;
    ANTENNADIFFAREA 0.708600 ;
    PORT
      LAYER Metal2 ;
        RECT 119.320 0.000 119.720 0.400 ;
    END
  END s_axil_mgr_rdata[9]
  PIN s_axil_mgr_rready
    DIRECTION INPUT ;
    USE SIGNAL ;
    ANTENNAGATEAREA 0.180700 ;
    ANTENNADIFFAREA 2.015400 ;
    PORT
      LAYER Metal2 ;
        RECT 244.120 0.000 244.520 0.400 ;
    END
  END s_axil_mgr_rready
  PIN s_axil_mgr_rresp[0]
    DIRECTION OUTPUT ;
    USE SIGNAL ;
    ANTENNADIFFAREA 0.299200 ;
    PORT
      LAYER Metal2 ;
        RECT 229.720 0.000 230.120 0.400 ;
    END
  END s_axil_mgr_rresp[0]
  PIN s_axil_mgr_rresp[1]
    DIRECTION OUTPUT ;
    USE SIGNAL ;
    ANTENNADIFFAREA 0.299200 ;
    PORT
      LAYER Metal2 ;
        RECT 234.520 0.000 234.920 0.400 ;
    END
  END s_axil_mgr_rresp[1]
  PIN s_axil_mgr_rvalid
    DIRECTION OUTPUT ;
    USE SIGNAL ;
    ANTENNADIFFAREA 0.708600 ;
    PORT
      LAYER Metal2 ;
        RECT 239.320 0.000 239.720 0.400 ;
    END
  END s_axil_mgr_rvalid
  PIN s_axil_mgr_wdata[0]
    DIRECTION INPUT ;
    USE SIGNAL ;
    ANTENNAGATEAREA 0.180700 ;
    ANTENNADIFFAREA 2.015400 ;
    PORT
      LAYER Metal3 ;
        RECT 0.000 465.580 0.400 465.980 ;
    END
  END s_axil_mgr_wdata[0]
  PIN s_axil_mgr_wdata[10]
    DIRECTION INPUT ;
    USE SIGNAL ;
    ANTENNAGATEAREA 0.180700 ;
    ANTENNADIFFAREA 2.015400 ;
    PORT
      LAYER Metal3 ;
        RECT 0.000 549.580 0.400 549.980 ;
    END
  END s_axil_mgr_wdata[10]
  PIN s_axil_mgr_wdata[11]
    DIRECTION INPUT ;
    USE SIGNAL ;
    ANTENNAGATEAREA 0.180700 ;
    ANTENNADIFFAREA 2.015400 ;
    PORT
      LAYER Metal3 ;
        RECT 0.000 557.980 0.400 558.380 ;
    END
  END s_axil_mgr_wdata[11]
  PIN s_axil_mgr_wdata[12]
    DIRECTION INPUT ;
    USE SIGNAL ;
    ANTENNAGATEAREA 0.180700 ;
    ANTENNADIFFAREA 2.015400 ;
    PORT
      LAYER Metal3 ;
        RECT 0.000 566.380 0.400 566.780 ;
    END
  END s_axil_mgr_wdata[12]
  PIN s_axil_mgr_wdata[13]
    DIRECTION INPUT ;
    USE SIGNAL ;
    ANTENNAGATEAREA 0.180700 ;
    ANTENNADIFFAREA 2.015400 ;
    PORT
      LAYER Metal3 ;
        RECT 0.000 574.780 0.400 575.180 ;
    END
  END s_axil_mgr_wdata[13]
  PIN s_axil_mgr_wdata[14]
    DIRECTION INPUT ;
    USE SIGNAL ;
    ANTENNAGATEAREA 0.180700 ;
    ANTENNADIFFAREA 2.015400 ;
    PORT
      LAYER Metal3 ;
        RECT 0.000 583.180 0.400 583.580 ;
    END
  END s_axil_mgr_wdata[14]
  PIN s_axil_mgr_wdata[15]
    DIRECTION INPUT ;
    USE SIGNAL ;
    ANTENNAGATEAREA 0.180700 ;
    ANTENNADIFFAREA 2.015400 ;
    PORT
      LAYER Metal3 ;
        RECT 0.000 591.580 0.400 591.980 ;
    END
  END s_axil_mgr_wdata[15]
  PIN s_axil_mgr_wdata[16]
    DIRECTION INPUT ;
    USE SIGNAL ;
    ANTENNAGATEAREA 0.180700 ;
    ANTENNADIFFAREA 2.015400 ;
    PORT
      LAYER Metal3 ;
        RECT 0.000 599.980 0.400 600.380 ;
    END
  END s_axil_mgr_wdata[16]
  PIN s_axil_mgr_wdata[17]
    DIRECTION INPUT ;
    USE SIGNAL ;
    ANTENNAGATEAREA 0.180700 ;
    ANTENNADIFFAREA 2.015400 ;
    PORT
      LAYER Metal3 ;
        RECT 0.000 608.380 0.400 608.780 ;
    END
  END s_axil_mgr_wdata[17]
  PIN s_axil_mgr_wdata[18]
    DIRECTION INPUT ;
    USE SIGNAL ;
    ANTENNAGATEAREA 0.180700 ;
    ANTENNADIFFAREA 2.015400 ;
    PORT
      LAYER Metal3 ;
        RECT 0.000 616.780 0.400 617.180 ;
    END
  END s_axil_mgr_wdata[18]
  PIN s_axil_mgr_wdata[19]
    DIRECTION INPUT ;
    USE SIGNAL ;
    ANTENNAGATEAREA 0.180700 ;
    ANTENNADIFFAREA 2.015400 ;
    PORT
      LAYER Metal3 ;
        RECT 0.000 625.180 0.400 625.580 ;
    END
  END s_axil_mgr_wdata[19]
  PIN s_axil_mgr_wdata[1]
    DIRECTION INPUT ;
    USE SIGNAL ;
    ANTENNAGATEAREA 0.180700 ;
    ANTENNADIFFAREA 2.015400 ;
    PORT
      LAYER Metal3 ;
        RECT 0.000 473.980 0.400 474.380 ;
    END
  END s_axil_mgr_wdata[1]
  PIN s_axil_mgr_wdata[20]
    DIRECTION INPUT ;
    USE SIGNAL ;
    ANTENNAGATEAREA 0.180700 ;
    ANTENNADIFFAREA 4.030800 ;
    PORT
      LAYER Metal3 ;
        RECT 0.000 633.580 0.400 633.980 ;
    END
  END s_axil_mgr_wdata[20]
  PIN s_axil_mgr_wdata[21]
    DIRECTION INPUT ;
    USE SIGNAL ;
    ANTENNAGATEAREA 0.180700 ;
    ANTENNADIFFAREA 2.015400 ;
    PORT
      LAYER Metal3 ;
        RECT 0.000 641.980 0.400 642.380 ;
    END
  END s_axil_mgr_wdata[21]
  PIN s_axil_mgr_wdata[22]
    DIRECTION INPUT ;
    USE SIGNAL ;
    ANTENNAGATEAREA 0.180700 ;
    ANTENNADIFFAREA 2.015400 ;
    PORT
      LAYER Metal3 ;
        RECT 0.000 650.380 0.400 650.780 ;
    END
  END s_axil_mgr_wdata[22]
  PIN s_axil_mgr_wdata[23]
    DIRECTION INPUT ;
    USE SIGNAL ;
    ANTENNAGATEAREA 0.180700 ;
    ANTENNADIFFAREA 2.015400 ;
    PORT
      LAYER Metal3 ;
        RECT 0.000 658.780 0.400 659.180 ;
    END
  END s_axil_mgr_wdata[23]
  PIN s_axil_mgr_wdata[24]
    DIRECTION INPUT ;
    USE SIGNAL ;
    ANTENNAGATEAREA 0.180700 ;
    ANTENNADIFFAREA 2.015400 ;
    PORT
      LAYER Metal3 ;
        RECT 0.000 667.180 0.400 667.580 ;
    END
  END s_axil_mgr_wdata[24]
  PIN s_axil_mgr_wdata[25]
    DIRECTION INPUT ;
    USE SIGNAL ;
    ANTENNAGATEAREA 0.180700 ;
    ANTENNADIFFAREA 2.015400 ;
    PORT
      LAYER Metal3 ;
        RECT 0.000 675.580 0.400 675.980 ;
    END
  END s_axil_mgr_wdata[25]
  PIN s_axil_mgr_wdata[26]
    DIRECTION INPUT ;
    USE SIGNAL ;
    ANTENNAGATEAREA 0.180700 ;
    ANTENNADIFFAREA 2.015400 ;
    PORT
      LAYER Metal3 ;
        RECT 0.000 683.980 0.400 684.380 ;
    END
  END s_axil_mgr_wdata[26]
  PIN s_axil_mgr_wdata[27]
    DIRECTION INPUT ;
    USE SIGNAL ;
    ANTENNAGATEAREA 0.180700 ;
    ANTENNADIFFAREA 2.015400 ;
    PORT
      LAYER Metal3 ;
        RECT 0.000 692.380 0.400 692.780 ;
    END
  END s_axil_mgr_wdata[27]
  PIN s_axil_mgr_wdata[28]
    DIRECTION INPUT ;
    USE SIGNAL ;
    ANTENNAGATEAREA 0.180700 ;
    ANTENNADIFFAREA 2.015400 ;
    PORT
      LAYER Metal3 ;
        RECT 0.000 700.780 0.400 701.180 ;
    END
  END s_axil_mgr_wdata[28]
  PIN s_axil_mgr_wdata[29]
    DIRECTION INPUT ;
    USE SIGNAL ;
    ANTENNAGATEAREA 0.180700 ;
    ANTENNADIFFAREA 2.015400 ;
    PORT
      LAYER Metal3 ;
        RECT 0.000 709.180 0.400 709.580 ;
    END
  END s_axil_mgr_wdata[29]
  PIN s_axil_mgr_wdata[2]
    DIRECTION INPUT ;
    USE SIGNAL ;
    ANTENNAGATEAREA 0.180700 ;
    ANTENNADIFFAREA 2.015400 ;
    PORT
      LAYER Metal3 ;
        RECT 0.000 482.380 0.400 482.780 ;
    END
  END s_axil_mgr_wdata[2]
  PIN s_axil_mgr_wdata[30]
    DIRECTION INPUT ;
    USE SIGNAL ;
    ANTENNAGATEAREA 0.180700 ;
    ANTENNADIFFAREA 2.015400 ;
    PORT
      LAYER Metal3 ;
        RECT 0.000 717.580 0.400 717.980 ;
    END
  END s_axil_mgr_wdata[30]
  PIN s_axil_mgr_wdata[31]
    DIRECTION INPUT ;
    USE SIGNAL ;
    ANTENNAGATEAREA 0.180700 ;
    ANTENNADIFFAREA 4.030800 ;
    PORT
      LAYER Metal3 ;
        RECT 0.000 725.980 0.400 726.380 ;
    END
  END s_axil_mgr_wdata[31]
  PIN s_axil_mgr_wdata[3]
    DIRECTION INPUT ;
    USE SIGNAL ;
    ANTENNAGATEAREA 0.180700 ;
    ANTENNADIFFAREA 2.015400 ;
    PORT
      LAYER Metal3 ;
        RECT 0.000 490.780 0.400 491.180 ;
    END
  END s_axil_mgr_wdata[3]
  PIN s_axil_mgr_wdata[4]
    DIRECTION INPUT ;
    USE SIGNAL ;
    ANTENNAGATEAREA 0.180700 ;
    ANTENNADIFFAREA 2.015400 ;
    PORT
      LAYER Metal3 ;
        RECT 0.000 499.180 0.400 499.580 ;
    END
  END s_axil_mgr_wdata[4]
  PIN s_axil_mgr_wdata[5]
    DIRECTION INPUT ;
    USE SIGNAL ;
    ANTENNAGATEAREA 0.180700 ;
    ANTENNADIFFAREA 2.015400 ;
    PORT
      LAYER Metal3 ;
        RECT 0.000 507.580 0.400 507.980 ;
    END
  END s_axil_mgr_wdata[5]
  PIN s_axil_mgr_wdata[6]
    DIRECTION INPUT ;
    USE SIGNAL ;
    ANTENNAGATEAREA 0.180700 ;
    ANTENNADIFFAREA 2.015400 ;
    PORT
      LAYER Metal3 ;
        RECT 0.000 515.980 0.400 516.380 ;
    END
  END s_axil_mgr_wdata[6]
  PIN s_axil_mgr_wdata[7]
    DIRECTION INPUT ;
    USE SIGNAL ;
    ANTENNAGATEAREA 0.180700 ;
    ANTENNADIFFAREA 2.015400 ;
    PORT
      LAYER Metal3 ;
        RECT 0.000 524.380 0.400 524.780 ;
    END
  END s_axil_mgr_wdata[7]
  PIN s_axil_mgr_wdata[8]
    DIRECTION INPUT ;
    USE SIGNAL ;
    ANTENNAGATEAREA 0.180700 ;
    ANTENNADIFFAREA 2.015400 ;
    PORT
      LAYER Metal3 ;
        RECT 0.000 532.780 0.400 533.180 ;
    END
  END s_axil_mgr_wdata[8]
  PIN s_axil_mgr_wdata[9]
    DIRECTION INPUT ;
    USE SIGNAL ;
    ANTENNAGATEAREA 0.180700 ;
    ANTENNADIFFAREA 2.015400 ;
    PORT
      LAYER Metal3 ;
        RECT 0.000 541.180 0.400 541.580 ;
    END
  END s_axil_mgr_wdata[9]
  PIN s_axil_mgr_wready
    DIRECTION OUTPUT ;
    USE SIGNAL ;
    ANTENNADIFFAREA 0.708600 ;
    PORT
      LAYER Metal3 ;
        RECT 0.000 415.180 0.400 415.580 ;
    END
  END s_axil_mgr_wready
  PIN s_axil_mgr_wstrb[0]
    DIRECTION INPUT ;
    USE SIGNAL ;
    ANTENNAGATEAREA 0.180700 ;
    ANTENNADIFFAREA 2.015400 ;
    PORT
      LAYER Metal3 ;
        RECT 0.000 431.980 0.400 432.380 ;
    END
  END s_axil_mgr_wstrb[0]
  PIN s_axil_mgr_wstrb[1]
    DIRECTION INPUT ;
    USE SIGNAL ;
    ANTENNAGATEAREA 0.180700 ;
    ANTENNADIFFAREA 2.015400 ;
    PORT
      LAYER Metal3 ;
        RECT 0.000 440.380 0.400 440.780 ;
    END
  END s_axil_mgr_wstrb[1]
  PIN s_axil_mgr_wstrb[2]
    DIRECTION INPUT ;
    USE SIGNAL ;
    ANTENNAGATEAREA 0.180700 ;
    ANTENNADIFFAREA 2.015400 ;
    PORT
      LAYER Metal3 ;
        RECT 0.000 448.780 0.400 449.180 ;
    END
  END s_axil_mgr_wstrb[2]
  PIN s_axil_mgr_wstrb[3]
    DIRECTION INPUT ;
    USE SIGNAL ;
    ANTENNAGATEAREA 0.180700 ;
    ANTENNADIFFAREA 2.015400 ;
    PORT
      LAYER Metal3 ;
        RECT 0.000 457.180 0.400 457.580 ;
    END
  END s_axil_mgr_wstrb[3]
  PIN s_axil_mgr_wvalid
    DIRECTION INPUT ;
    USE SIGNAL ;
    ANTENNAGATEAREA 0.180700 ;
    ANTENNADIFFAREA 2.015400 ;
    PORT
      LAYER Metal3 ;
        RECT 0.000 423.580 0.400 423.980 ;
    END
  END s_axil_mgr_wvalid
  OBS
      LAYER GatPoly ;
        RECT 5.760 14.970 3994.080 4233.750 ;
      LAYER Metal1 ;
        RECT 5.760 14.900 3994.080 4233.820 ;
      LAYER Metal2 ;
        RECT 0.375 4249.390 49.990 4249.600 ;
        RECT 50.810 4249.390 149.830 4249.600 ;
        RECT 150.650 4249.390 517.510 4249.600 ;
        RECT 518.330 4249.390 532.870 4249.600 ;
        RECT 533.690 4249.390 548.230 4249.600 ;
        RECT 549.050 4249.390 563.590 4249.600 ;
        RECT 564.410 4249.390 578.950 4249.600 ;
        RECT 579.770 4249.390 594.310 4249.600 ;
        RECT 595.130 4249.390 609.670 4249.600 ;
        RECT 610.490 4249.390 625.030 4249.600 ;
        RECT 625.850 4249.390 640.390 4249.600 ;
        RECT 641.210 4249.390 655.750 4249.600 ;
        RECT 656.570 4249.390 671.110 4249.600 ;
        RECT 671.930 4249.390 686.470 4249.600 ;
        RECT 687.290 4249.390 701.830 4249.600 ;
        RECT 702.650 4249.390 717.190 4249.600 ;
        RECT 718.010 4249.390 732.550 4249.600 ;
        RECT 733.370 4249.390 747.910 4249.600 ;
        RECT 748.730 4249.390 763.270 4249.600 ;
        RECT 764.090 4249.390 778.630 4249.600 ;
        RECT 779.450 4249.390 793.990 4249.600 ;
        RECT 794.810 4249.390 809.350 4249.600 ;
        RECT 810.170 4249.390 824.710 4249.600 ;
        RECT 825.530 4249.390 840.070 4249.600 ;
        RECT 840.890 4249.390 855.430 4249.600 ;
        RECT 856.250 4249.390 870.790 4249.600 ;
        RECT 871.610 4249.390 3983.625 4249.600 ;
        RECT 0.375 0.610 3983.625 4249.390 ;
        RECT 0.375 0.100 65.350 0.610 ;
        RECT 66.170 0.100 75.910 0.610 ;
        RECT 76.730 0.100 80.710 0.610 ;
        RECT 81.530 0.100 85.510 0.610 ;
        RECT 86.330 0.100 90.310 0.610 ;
        RECT 91.130 0.100 95.110 0.610 ;
        RECT 95.930 0.100 99.910 0.610 ;
        RECT 100.730 0.100 104.710 0.610 ;
        RECT 105.530 0.100 109.510 0.610 ;
        RECT 110.330 0.100 114.310 0.610 ;
        RECT 115.130 0.100 119.110 0.610 ;
        RECT 119.930 0.100 123.910 0.610 ;
        RECT 124.730 0.100 128.710 0.610 ;
        RECT 129.530 0.100 133.510 0.610 ;
        RECT 134.330 0.100 138.310 0.610 ;
        RECT 139.130 0.100 143.110 0.610 ;
        RECT 143.930 0.100 147.910 0.610 ;
        RECT 148.730 0.100 152.710 0.610 ;
        RECT 153.530 0.100 157.510 0.610 ;
        RECT 158.330 0.100 162.310 0.610 ;
        RECT 163.130 0.100 167.110 0.610 ;
        RECT 167.930 0.100 171.910 0.610 ;
        RECT 172.730 0.100 176.710 0.610 ;
        RECT 177.530 0.100 181.510 0.610 ;
        RECT 182.330 0.100 186.310 0.610 ;
        RECT 187.130 0.100 191.110 0.610 ;
        RECT 191.930 0.100 195.910 0.610 ;
        RECT 196.730 0.100 200.710 0.610 ;
        RECT 201.530 0.100 205.510 0.610 ;
        RECT 206.330 0.100 210.310 0.610 ;
        RECT 211.130 0.100 215.110 0.610 ;
        RECT 215.930 0.100 219.910 0.610 ;
        RECT 220.730 0.100 224.710 0.610 ;
        RECT 225.530 0.100 229.510 0.610 ;
        RECT 230.330 0.100 234.310 0.610 ;
        RECT 235.130 0.100 239.110 0.610 ;
        RECT 239.930 0.100 243.910 0.610 ;
        RECT 244.730 0.100 360.070 0.610 ;
        RECT 360.890 0.100 453.190 0.610 ;
        RECT 454.010 0.100 546.310 0.610 ;
        RECT 547.130 0.100 639.430 0.610 ;
        RECT 640.250 0.100 732.550 0.610 ;
        RECT 733.370 0.100 918.790 0.610 ;
        RECT 919.610 0.100 1011.910 0.610 ;
        RECT 1012.730 0.100 1105.030 0.610 ;
        RECT 1105.850 0.100 1198.150 0.610 ;
        RECT 1198.970 0.100 1291.270 0.610 ;
        RECT 1292.090 0.100 1384.390 0.610 ;
        RECT 1385.210 0.100 1477.510 0.610 ;
        RECT 1478.330 0.100 1570.630 0.610 ;
        RECT 1571.450 0.100 3983.625 0.610 ;
      LAYER Metal3 ;
        RECT 0.100 4178.990 3983.665 4233.700 ;
        RECT 0.610 4178.170 3983.665 4178.990 ;
        RECT 0.100 4170.590 3983.665 4178.170 ;
        RECT 0.610 4169.770 3983.665 4170.590 ;
        RECT 0.100 4162.190 3983.665 4169.770 ;
        RECT 0.610 4161.370 3983.665 4162.190 ;
        RECT 0.100 4153.790 3983.665 4161.370 ;
        RECT 0.610 4152.970 3983.665 4153.790 ;
        RECT 0.100 4145.390 3983.665 4152.970 ;
        RECT 0.610 4144.570 3983.665 4145.390 ;
        RECT 0.100 4136.990 3983.665 4144.570 ;
        RECT 0.610 4136.170 3983.665 4136.990 ;
        RECT 0.100 4128.590 3983.665 4136.170 ;
        RECT 0.610 4127.770 3983.665 4128.590 ;
        RECT 0.100 4120.190 3983.665 4127.770 ;
        RECT 0.610 4119.370 3983.665 4120.190 ;
        RECT 0.100 4111.790 3983.665 4119.370 ;
        RECT 0.610 4110.970 3983.665 4111.790 ;
        RECT 0.100 4103.390 3983.665 4110.970 ;
        RECT 0.610 4102.570 3983.665 4103.390 ;
        RECT 0.100 4094.990 3983.665 4102.570 ;
        RECT 0.610 4094.170 3983.665 4094.990 ;
        RECT 0.100 4086.590 3983.665 4094.170 ;
        RECT 0.610 4085.770 3983.665 4086.590 ;
        RECT 0.100 4078.190 3983.665 4085.770 ;
        RECT 0.610 4077.370 3983.665 4078.190 ;
        RECT 0.100 4069.790 3983.665 4077.370 ;
        RECT 0.610 4068.970 3983.665 4069.790 ;
        RECT 0.100 4061.390 3983.665 4068.970 ;
        RECT 0.610 4060.570 3983.665 4061.390 ;
        RECT 0.100 4052.990 3983.665 4060.570 ;
        RECT 0.610 4052.170 3983.665 4052.990 ;
        RECT 0.100 4044.590 3983.665 4052.170 ;
        RECT 0.610 4043.770 3983.665 4044.590 ;
        RECT 0.100 4036.190 3983.665 4043.770 ;
        RECT 0.610 4035.370 3983.665 4036.190 ;
        RECT 0.100 4027.790 3983.665 4035.370 ;
        RECT 0.610 4026.970 3983.665 4027.790 ;
        RECT 0.100 4019.390 3983.665 4026.970 ;
        RECT 0.610 4018.570 3983.665 4019.390 ;
        RECT 0.100 4010.990 3983.665 4018.570 ;
        RECT 0.610 4010.170 3983.665 4010.990 ;
        RECT 0.100 4002.590 3983.665 4010.170 ;
        RECT 0.610 4001.770 3983.665 4002.590 ;
        RECT 0.100 3994.190 3983.665 4001.770 ;
        RECT 0.610 3993.370 3983.665 3994.190 ;
        RECT 0.100 3985.790 3983.665 3993.370 ;
        RECT 0.610 3984.970 3983.665 3985.790 ;
        RECT 0.100 3977.390 3983.665 3984.970 ;
        RECT 0.610 3976.570 3983.665 3977.390 ;
        RECT 0.100 3968.990 3983.665 3976.570 ;
        RECT 0.610 3968.170 3983.665 3968.990 ;
        RECT 0.100 3960.590 3983.665 3968.170 ;
        RECT 0.610 3959.770 3983.665 3960.590 ;
        RECT 0.100 3952.190 3983.665 3959.770 ;
        RECT 0.610 3951.370 3983.665 3952.190 ;
        RECT 0.100 3943.790 3983.665 3951.370 ;
        RECT 0.610 3942.970 3983.665 3943.790 ;
        RECT 0.100 3935.390 3983.665 3942.970 ;
        RECT 0.610 3934.570 3983.665 3935.390 ;
        RECT 0.100 3926.990 3983.665 3934.570 ;
        RECT 0.610 3926.170 3983.665 3926.990 ;
        RECT 0.100 3918.590 3983.665 3926.170 ;
        RECT 0.610 3917.770 3983.665 3918.590 ;
        RECT 0.100 3910.190 3983.665 3917.770 ;
        RECT 0.610 3909.370 3983.665 3910.190 ;
        RECT 0.100 3901.790 3983.665 3909.370 ;
        RECT 0.610 3900.970 3983.665 3901.790 ;
        RECT 0.100 3893.390 3983.665 3900.970 ;
        RECT 0.610 3892.570 3983.665 3893.390 ;
        RECT 0.100 3884.990 3983.665 3892.570 ;
        RECT 0.610 3884.170 3983.665 3884.990 ;
        RECT 0.100 3876.590 3983.665 3884.170 ;
        RECT 0.610 3875.770 3983.665 3876.590 ;
        RECT 0.100 3868.190 3983.665 3875.770 ;
        RECT 0.610 3867.370 3983.665 3868.190 ;
        RECT 0.100 3859.790 3983.665 3867.370 ;
        RECT 0.610 3858.970 3983.665 3859.790 ;
        RECT 0.100 3851.390 3983.665 3858.970 ;
        RECT 0.610 3850.570 3983.665 3851.390 ;
        RECT 0.100 3842.990 3983.665 3850.570 ;
        RECT 0.610 3842.170 3983.665 3842.990 ;
        RECT 0.100 3834.590 3983.665 3842.170 ;
        RECT 0.610 3833.770 3983.665 3834.590 ;
        RECT 0.100 3826.190 3983.665 3833.770 ;
        RECT 0.610 3825.370 3983.665 3826.190 ;
        RECT 0.100 3817.790 3983.665 3825.370 ;
        RECT 0.610 3816.970 3983.665 3817.790 ;
        RECT 0.100 3809.390 3983.665 3816.970 ;
        RECT 0.610 3808.570 3983.665 3809.390 ;
        RECT 0.100 3800.990 3983.665 3808.570 ;
        RECT 0.610 3800.170 3983.665 3800.990 ;
        RECT 0.100 3792.590 3983.665 3800.170 ;
        RECT 0.610 3791.770 3983.665 3792.590 ;
        RECT 0.100 3784.190 3983.665 3791.770 ;
        RECT 0.610 3783.370 3983.665 3784.190 ;
        RECT 0.100 3775.790 3983.665 3783.370 ;
        RECT 0.610 3774.970 3983.665 3775.790 ;
        RECT 0.100 3767.390 3983.665 3774.970 ;
        RECT 0.610 3766.570 3983.665 3767.390 ;
        RECT 0.100 3758.990 3983.665 3766.570 ;
        RECT 0.610 3758.170 3983.665 3758.990 ;
        RECT 0.100 3750.590 3983.665 3758.170 ;
        RECT 0.610 3749.770 3983.665 3750.590 ;
        RECT 0.100 3742.190 3983.665 3749.770 ;
        RECT 0.610 3741.370 3983.665 3742.190 ;
        RECT 0.100 3733.790 3983.665 3741.370 ;
        RECT 0.610 3732.970 3983.665 3733.790 ;
        RECT 0.100 3725.390 3983.665 3732.970 ;
        RECT 0.610 3724.570 3983.665 3725.390 ;
        RECT 0.100 3716.990 3983.665 3724.570 ;
        RECT 0.610 3716.170 3983.665 3716.990 ;
        RECT 0.100 3708.590 3983.665 3716.170 ;
        RECT 0.610 3707.770 3983.665 3708.590 ;
        RECT 0.100 3700.190 3983.665 3707.770 ;
        RECT 0.610 3699.370 3983.665 3700.190 ;
        RECT 0.100 3691.790 3983.665 3699.370 ;
        RECT 0.610 3690.970 3983.665 3691.790 ;
        RECT 0.100 3683.390 3983.665 3690.970 ;
        RECT 0.610 3682.570 3983.665 3683.390 ;
        RECT 0.100 3674.990 3983.665 3682.570 ;
        RECT 0.610 3674.170 3983.665 3674.990 ;
        RECT 0.100 3666.590 3983.665 3674.170 ;
        RECT 0.610 3665.770 3983.665 3666.590 ;
        RECT 0.100 3658.190 3983.665 3665.770 ;
        RECT 0.610 3657.370 3983.665 3658.190 ;
        RECT 0.100 3649.790 3983.665 3657.370 ;
        RECT 0.610 3648.970 3983.665 3649.790 ;
        RECT 0.100 3641.390 3983.665 3648.970 ;
        RECT 0.610 3640.570 3983.665 3641.390 ;
        RECT 0.100 3632.990 3983.665 3640.570 ;
        RECT 0.610 3632.170 3983.665 3632.990 ;
        RECT 0.100 3624.590 3983.665 3632.170 ;
        RECT 0.610 3623.770 3983.665 3624.590 ;
        RECT 0.100 3616.190 3983.665 3623.770 ;
        RECT 0.610 3615.370 3983.665 3616.190 ;
        RECT 0.100 3607.790 3983.665 3615.370 ;
        RECT 0.610 3606.970 3983.665 3607.790 ;
        RECT 0.100 3599.390 3983.665 3606.970 ;
        RECT 0.610 3598.570 3983.665 3599.390 ;
        RECT 0.100 3590.990 3983.665 3598.570 ;
        RECT 0.610 3590.170 3983.665 3590.990 ;
        RECT 0.100 3582.590 3983.665 3590.170 ;
        RECT 0.610 3581.770 3983.665 3582.590 ;
        RECT 0.100 3574.190 3983.665 3581.770 ;
        RECT 0.610 3573.370 3983.665 3574.190 ;
        RECT 0.100 3565.790 3983.665 3573.370 ;
        RECT 0.610 3564.970 3983.665 3565.790 ;
        RECT 0.100 3557.390 3983.665 3564.970 ;
        RECT 0.610 3556.570 3983.665 3557.390 ;
        RECT 0.100 3548.990 3983.665 3556.570 ;
        RECT 0.610 3548.170 3983.665 3548.990 ;
        RECT 0.100 3540.590 3983.665 3548.170 ;
        RECT 0.610 3539.770 3983.665 3540.590 ;
        RECT 0.100 3532.190 3983.665 3539.770 ;
        RECT 0.610 3531.370 3983.665 3532.190 ;
        RECT 0.100 3523.790 3983.665 3531.370 ;
        RECT 0.610 3522.970 3983.665 3523.790 ;
        RECT 0.100 3515.390 3983.665 3522.970 ;
        RECT 0.610 3514.570 3983.665 3515.390 ;
        RECT 0.100 3506.990 3983.665 3514.570 ;
        RECT 0.610 3506.170 3983.665 3506.990 ;
        RECT 0.100 3498.590 3983.665 3506.170 ;
        RECT 0.610 3497.770 3983.665 3498.590 ;
        RECT 0.100 3490.190 3983.665 3497.770 ;
        RECT 0.610 3489.370 3983.665 3490.190 ;
        RECT 0.100 3481.790 3983.665 3489.370 ;
        RECT 0.610 3480.970 3983.665 3481.790 ;
        RECT 0.100 3473.390 3983.665 3480.970 ;
        RECT 0.610 3472.570 3983.665 3473.390 ;
        RECT 0.100 3464.990 3983.665 3472.570 ;
        RECT 0.610 3464.170 3983.665 3464.990 ;
        RECT 0.100 3456.590 3983.665 3464.170 ;
        RECT 0.610 3455.770 3983.665 3456.590 ;
        RECT 0.100 3448.190 3983.665 3455.770 ;
        RECT 0.610 3447.370 3983.665 3448.190 ;
        RECT 0.100 3439.790 3983.665 3447.370 ;
        RECT 0.610 3438.970 3983.665 3439.790 ;
        RECT 0.100 3431.390 3983.665 3438.970 ;
        RECT 0.610 3430.570 3983.665 3431.390 ;
        RECT 0.100 3422.990 3983.665 3430.570 ;
        RECT 0.610 3422.170 3983.665 3422.990 ;
        RECT 0.100 3414.590 3983.665 3422.170 ;
        RECT 0.610 3413.770 3983.665 3414.590 ;
        RECT 0.100 3406.190 3983.665 3413.770 ;
        RECT 0.610 3405.370 3983.665 3406.190 ;
        RECT 0.100 3397.790 3983.665 3405.370 ;
        RECT 0.610 3396.970 3983.665 3397.790 ;
        RECT 0.100 3389.390 3983.665 3396.970 ;
        RECT 0.610 3388.570 3983.665 3389.390 ;
        RECT 0.100 3380.990 3983.665 3388.570 ;
        RECT 0.610 3380.170 3983.665 3380.990 ;
        RECT 0.100 3372.590 3983.665 3380.170 ;
        RECT 0.610 3371.770 3983.665 3372.590 ;
        RECT 0.100 3364.190 3983.665 3371.770 ;
        RECT 0.610 3363.370 3983.665 3364.190 ;
        RECT 0.100 3355.790 3983.665 3363.370 ;
        RECT 0.610 3354.970 3983.665 3355.790 ;
        RECT 0.100 3347.390 3983.665 3354.970 ;
        RECT 0.610 3346.570 3983.665 3347.390 ;
        RECT 0.100 3338.990 3983.665 3346.570 ;
        RECT 0.610 3338.170 3983.665 3338.990 ;
        RECT 0.100 3330.590 3983.665 3338.170 ;
        RECT 0.610 3329.770 3983.665 3330.590 ;
        RECT 0.100 3322.190 3983.665 3329.770 ;
        RECT 0.610 3321.370 3983.665 3322.190 ;
        RECT 0.100 3313.790 3983.665 3321.370 ;
        RECT 0.610 3312.970 3983.665 3313.790 ;
        RECT 0.100 3305.390 3983.665 3312.970 ;
        RECT 0.610 3304.570 3983.665 3305.390 ;
        RECT 0.100 3296.990 3983.665 3304.570 ;
        RECT 0.610 3296.170 3983.665 3296.990 ;
        RECT 0.100 3288.590 3983.665 3296.170 ;
        RECT 0.610 3287.770 3983.665 3288.590 ;
        RECT 0.100 3280.190 3983.665 3287.770 ;
        RECT 0.610 3279.370 3983.665 3280.190 ;
        RECT 0.100 3271.790 3983.665 3279.370 ;
        RECT 0.610 3270.970 3983.665 3271.790 ;
        RECT 0.100 3263.390 3983.665 3270.970 ;
        RECT 0.610 3262.570 3983.665 3263.390 ;
        RECT 0.100 3254.990 3983.665 3262.570 ;
        RECT 0.610 3254.170 3983.665 3254.990 ;
        RECT 0.100 3246.590 3983.665 3254.170 ;
        RECT 0.610 3245.770 3983.665 3246.590 ;
        RECT 0.100 3238.190 3983.665 3245.770 ;
        RECT 0.610 3237.370 3983.665 3238.190 ;
        RECT 0.100 3229.790 3983.665 3237.370 ;
        RECT 0.610 3228.970 3983.665 3229.790 ;
        RECT 0.100 3221.390 3983.665 3228.970 ;
        RECT 0.610 3220.570 3983.665 3221.390 ;
        RECT 0.100 3212.990 3983.665 3220.570 ;
        RECT 0.610 3212.170 3983.665 3212.990 ;
        RECT 0.100 3204.590 3983.665 3212.170 ;
        RECT 0.610 3203.770 3983.665 3204.590 ;
        RECT 0.100 3196.190 3983.665 3203.770 ;
        RECT 0.610 3195.370 3983.665 3196.190 ;
        RECT 0.100 3187.790 3983.665 3195.370 ;
        RECT 0.610 3186.970 3983.665 3187.790 ;
        RECT 0.100 3179.390 3983.665 3186.970 ;
        RECT 0.610 3178.570 3983.665 3179.390 ;
        RECT 0.100 3170.990 3983.665 3178.570 ;
        RECT 0.610 3170.170 3983.665 3170.990 ;
        RECT 0.100 3162.590 3983.665 3170.170 ;
        RECT 0.610 3161.770 3983.665 3162.590 ;
        RECT 0.100 3154.190 3983.665 3161.770 ;
        RECT 0.610 3153.370 3983.665 3154.190 ;
        RECT 0.100 3145.790 3983.665 3153.370 ;
        RECT 0.610 3144.970 3983.665 3145.790 ;
        RECT 0.100 3137.390 3983.665 3144.970 ;
        RECT 0.610 3136.570 3983.665 3137.390 ;
        RECT 0.100 3128.990 3983.665 3136.570 ;
        RECT 0.610 3128.170 3983.665 3128.990 ;
        RECT 0.100 3120.590 3983.665 3128.170 ;
        RECT 0.610 3119.770 3983.665 3120.590 ;
        RECT 0.100 3112.190 3983.665 3119.770 ;
        RECT 0.610 3111.370 3983.665 3112.190 ;
        RECT 0.100 3103.790 3983.665 3111.370 ;
        RECT 0.610 3102.970 3983.665 3103.790 ;
        RECT 0.100 3095.390 3983.665 3102.970 ;
        RECT 0.610 3094.570 3983.665 3095.390 ;
        RECT 0.100 3086.990 3983.665 3094.570 ;
        RECT 0.610 3086.170 3983.665 3086.990 ;
        RECT 0.100 3078.590 3983.665 3086.170 ;
        RECT 0.610 3077.770 3983.665 3078.590 ;
        RECT 0.100 3070.190 3983.665 3077.770 ;
        RECT 0.610 3069.370 3983.665 3070.190 ;
        RECT 0.100 3061.790 3983.665 3069.370 ;
        RECT 0.610 3060.970 3983.665 3061.790 ;
        RECT 0.100 3053.390 3983.665 3060.970 ;
        RECT 0.610 3052.570 3983.665 3053.390 ;
        RECT 0.100 3044.990 3983.665 3052.570 ;
        RECT 0.610 3044.170 3983.665 3044.990 ;
        RECT 0.100 3036.590 3983.665 3044.170 ;
        RECT 0.610 3035.770 3983.665 3036.590 ;
        RECT 0.100 3028.190 3983.665 3035.770 ;
        RECT 0.610 3027.370 3983.665 3028.190 ;
        RECT 0.100 3019.790 3983.665 3027.370 ;
        RECT 0.610 3018.970 3983.665 3019.790 ;
        RECT 0.100 3011.390 3983.665 3018.970 ;
        RECT 0.610 3010.570 3983.665 3011.390 ;
        RECT 0.100 3002.990 3983.665 3010.570 ;
        RECT 0.610 3002.170 3983.665 3002.990 ;
        RECT 0.100 2994.590 3983.665 3002.170 ;
        RECT 0.610 2993.770 3983.665 2994.590 ;
        RECT 0.100 2986.190 3983.665 2993.770 ;
        RECT 0.610 2985.370 3983.665 2986.190 ;
        RECT 0.100 2977.790 3983.665 2985.370 ;
        RECT 0.610 2976.970 3983.665 2977.790 ;
        RECT 0.100 2969.390 3983.665 2976.970 ;
        RECT 0.610 2968.570 3983.665 2969.390 ;
        RECT 0.100 2960.990 3983.665 2968.570 ;
        RECT 0.610 2960.170 3983.665 2960.990 ;
        RECT 0.100 2952.590 3983.665 2960.170 ;
        RECT 0.610 2951.770 3983.665 2952.590 ;
        RECT 0.100 2944.190 3983.665 2951.770 ;
        RECT 0.610 2943.370 3983.665 2944.190 ;
        RECT 0.100 2935.790 3983.665 2943.370 ;
        RECT 0.610 2934.970 3983.665 2935.790 ;
        RECT 0.100 2927.390 3983.665 2934.970 ;
        RECT 0.610 2926.570 3983.665 2927.390 ;
        RECT 0.100 2918.990 3983.665 2926.570 ;
        RECT 0.610 2918.170 3983.665 2918.990 ;
        RECT 0.100 2910.590 3983.665 2918.170 ;
        RECT 0.610 2909.770 3983.665 2910.590 ;
        RECT 0.100 2902.190 3983.665 2909.770 ;
        RECT 0.610 2901.370 3983.665 2902.190 ;
        RECT 0.100 2893.790 3983.665 2901.370 ;
        RECT 0.610 2892.970 3983.665 2893.790 ;
        RECT 0.100 2885.390 3983.665 2892.970 ;
        RECT 0.610 2884.570 3983.665 2885.390 ;
        RECT 0.100 2876.990 3983.665 2884.570 ;
        RECT 0.610 2876.170 3983.665 2876.990 ;
        RECT 0.100 2868.590 3983.665 2876.170 ;
        RECT 0.610 2867.770 3983.665 2868.590 ;
        RECT 0.100 2860.190 3983.665 2867.770 ;
        RECT 0.610 2859.370 3983.665 2860.190 ;
        RECT 0.100 2851.790 3983.665 2859.370 ;
        RECT 0.610 2850.970 3983.665 2851.790 ;
        RECT 0.100 2843.390 3983.665 2850.970 ;
        RECT 0.610 2842.570 3983.665 2843.390 ;
        RECT 0.100 2834.990 3983.665 2842.570 ;
        RECT 0.610 2834.170 3983.665 2834.990 ;
        RECT 0.100 2826.590 3983.665 2834.170 ;
        RECT 0.610 2825.770 3983.665 2826.590 ;
        RECT 0.100 2818.190 3983.665 2825.770 ;
        RECT 0.610 2817.370 3983.665 2818.190 ;
        RECT 0.100 2809.790 3983.665 2817.370 ;
        RECT 0.610 2808.970 3983.665 2809.790 ;
        RECT 0.100 2801.390 3983.665 2808.970 ;
        RECT 0.610 2800.570 3983.665 2801.390 ;
        RECT 0.100 2792.990 3983.665 2800.570 ;
        RECT 0.610 2792.170 3983.665 2792.990 ;
        RECT 0.100 2784.590 3983.665 2792.170 ;
        RECT 0.610 2783.770 3983.665 2784.590 ;
        RECT 0.100 2776.190 3983.665 2783.770 ;
        RECT 0.610 2775.370 3983.665 2776.190 ;
        RECT 0.100 2767.790 3983.665 2775.370 ;
        RECT 0.610 2766.970 3983.665 2767.790 ;
        RECT 0.100 2759.390 3983.665 2766.970 ;
        RECT 0.610 2758.570 3983.665 2759.390 ;
        RECT 0.100 2750.990 3983.665 2758.570 ;
        RECT 0.610 2750.170 3983.665 2750.990 ;
        RECT 0.100 2742.590 3983.665 2750.170 ;
        RECT 0.610 2741.770 3983.665 2742.590 ;
        RECT 0.100 2734.190 3983.665 2741.770 ;
        RECT 0.610 2733.370 3983.665 2734.190 ;
        RECT 0.100 2725.790 3983.665 2733.370 ;
        RECT 0.610 2724.970 3983.665 2725.790 ;
        RECT 0.100 2717.390 3983.665 2724.970 ;
        RECT 0.610 2716.570 3983.665 2717.390 ;
        RECT 0.100 2708.990 3983.665 2716.570 ;
        RECT 0.610 2708.170 3983.665 2708.990 ;
        RECT 0.100 2700.590 3983.665 2708.170 ;
        RECT 0.610 2699.770 3983.665 2700.590 ;
        RECT 0.100 2692.190 3983.665 2699.770 ;
        RECT 0.610 2691.370 3983.665 2692.190 ;
        RECT 0.100 2683.790 3983.665 2691.370 ;
        RECT 0.610 2682.970 3983.665 2683.790 ;
        RECT 0.100 2675.390 3983.665 2682.970 ;
        RECT 0.610 2674.570 3983.665 2675.390 ;
        RECT 0.100 2666.990 3983.665 2674.570 ;
        RECT 0.610 2666.170 3983.665 2666.990 ;
        RECT 0.100 2658.590 3983.665 2666.170 ;
        RECT 0.610 2657.770 3983.665 2658.590 ;
        RECT 0.100 2650.190 3983.665 2657.770 ;
        RECT 0.610 2649.370 3983.665 2650.190 ;
        RECT 0.100 2641.790 3983.665 2649.370 ;
        RECT 0.610 2640.970 3983.665 2641.790 ;
        RECT 0.100 2633.390 3983.665 2640.970 ;
        RECT 0.610 2632.570 3983.665 2633.390 ;
        RECT 0.100 2624.990 3983.665 2632.570 ;
        RECT 0.610 2624.170 3983.665 2624.990 ;
        RECT 0.100 2616.590 3983.665 2624.170 ;
        RECT 0.610 2615.770 3983.665 2616.590 ;
        RECT 0.100 2608.190 3983.665 2615.770 ;
        RECT 0.610 2607.370 3983.665 2608.190 ;
        RECT 0.100 2599.790 3983.665 2607.370 ;
        RECT 0.610 2598.970 3983.665 2599.790 ;
        RECT 0.100 2591.390 3983.665 2598.970 ;
        RECT 0.610 2590.570 3983.665 2591.390 ;
        RECT 0.100 2582.990 3983.665 2590.570 ;
        RECT 0.610 2582.170 3983.665 2582.990 ;
        RECT 0.100 2574.590 3983.665 2582.170 ;
        RECT 0.610 2573.770 3983.665 2574.590 ;
        RECT 0.100 2566.190 3983.665 2573.770 ;
        RECT 0.610 2565.370 3983.665 2566.190 ;
        RECT 0.100 2557.790 3983.665 2565.370 ;
        RECT 0.610 2556.970 3983.665 2557.790 ;
        RECT 0.100 2549.390 3983.665 2556.970 ;
        RECT 0.610 2548.570 3983.665 2549.390 ;
        RECT 0.100 2540.990 3983.665 2548.570 ;
        RECT 0.610 2540.170 3983.665 2540.990 ;
        RECT 0.100 2532.590 3983.665 2540.170 ;
        RECT 0.610 2531.770 3983.665 2532.590 ;
        RECT 0.100 2524.190 3983.665 2531.770 ;
        RECT 0.610 2523.370 3983.665 2524.190 ;
        RECT 0.100 2515.790 3983.665 2523.370 ;
        RECT 0.610 2514.970 3983.665 2515.790 ;
        RECT 0.100 2507.390 3983.665 2514.970 ;
        RECT 0.610 2506.570 3983.665 2507.390 ;
        RECT 0.100 2498.990 3983.665 2506.570 ;
        RECT 0.610 2498.170 3983.665 2498.990 ;
        RECT 0.100 2490.590 3983.665 2498.170 ;
        RECT 0.610 2489.770 3983.665 2490.590 ;
        RECT 0.100 2482.190 3983.665 2489.770 ;
        RECT 0.610 2481.370 3983.665 2482.190 ;
        RECT 0.100 2473.790 3983.665 2481.370 ;
        RECT 0.610 2472.970 3983.665 2473.790 ;
        RECT 0.100 2465.390 3983.665 2472.970 ;
        RECT 0.610 2464.570 3983.665 2465.390 ;
        RECT 0.100 2456.990 3983.665 2464.570 ;
        RECT 0.610 2456.170 3983.665 2456.990 ;
        RECT 0.100 2448.590 3983.665 2456.170 ;
        RECT 0.610 2447.770 3983.665 2448.590 ;
        RECT 0.100 2440.190 3983.665 2447.770 ;
        RECT 0.610 2439.370 3983.665 2440.190 ;
        RECT 0.100 2431.790 3983.665 2439.370 ;
        RECT 0.610 2430.970 3983.665 2431.790 ;
        RECT 0.100 2423.390 3983.665 2430.970 ;
        RECT 0.610 2422.570 3983.665 2423.390 ;
        RECT 0.100 2414.990 3983.665 2422.570 ;
        RECT 0.610 2414.170 3983.665 2414.990 ;
        RECT 0.100 2406.590 3983.665 2414.170 ;
        RECT 0.610 2405.770 3983.665 2406.590 ;
        RECT 0.100 2398.190 3983.665 2405.770 ;
        RECT 0.610 2397.370 3983.665 2398.190 ;
        RECT 0.100 2389.790 3983.665 2397.370 ;
        RECT 0.610 2388.970 3983.665 2389.790 ;
        RECT 0.100 2381.390 3983.665 2388.970 ;
        RECT 0.610 2380.570 3983.665 2381.390 ;
        RECT 0.100 2372.990 3983.665 2380.570 ;
        RECT 0.610 2372.170 3983.665 2372.990 ;
        RECT 0.100 2364.590 3983.665 2372.170 ;
        RECT 0.610 2363.770 3983.665 2364.590 ;
        RECT 0.100 2356.190 3983.665 2363.770 ;
        RECT 0.610 2355.370 3983.665 2356.190 ;
        RECT 0.100 2347.790 3983.665 2355.370 ;
        RECT 0.610 2346.970 3983.665 2347.790 ;
        RECT 0.100 2339.390 3983.665 2346.970 ;
        RECT 0.610 2338.570 3983.665 2339.390 ;
        RECT 0.100 2330.990 3983.665 2338.570 ;
        RECT 0.610 2330.170 3983.665 2330.990 ;
        RECT 0.100 2322.590 3983.665 2330.170 ;
        RECT 0.610 2321.770 3983.665 2322.590 ;
        RECT 0.100 2314.190 3983.665 2321.770 ;
        RECT 0.610 2313.370 3983.665 2314.190 ;
        RECT 0.100 2305.790 3983.665 2313.370 ;
        RECT 0.610 2304.970 3983.665 2305.790 ;
        RECT 0.100 2297.390 3983.665 2304.970 ;
        RECT 0.610 2296.570 3983.665 2297.390 ;
        RECT 0.100 2288.990 3983.665 2296.570 ;
        RECT 0.610 2288.170 3983.665 2288.990 ;
        RECT 0.100 2280.590 3983.665 2288.170 ;
        RECT 0.610 2279.770 3983.665 2280.590 ;
        RECT 0.100 2272.190 3983.665 2279.770 ;
        RECT 0.610 2271.370 3983.665 2272.190 ;
        RECT 0.100 2263.790 3983.665 2271.370 ;
        RECT 0.610 2262.970 3983.665 2263.790 ;
        RECT 0.100 2255.390 3983.665 2262.970 ;
        RECT 0.610 2254.570 3983.665 2255.390 ;
        RECT 0.100 2246.990 3983.665 2254.570 ;
        RECT 0.610 2246.170 3983.665 2246.990 ;
        RECT 0.100 2238.590 3983.665 2246.170 ;
        RECT 0.610 2237.770 3983.665 2238.590 ;
        RECT 0.100 2230.190 3983.665 2237.770 ;
        RECT 0.610 2229.370 3983.665 2230.190 ;
        RECT 0.100 2221.790 3983.665 2229.370 ;
        RECT 0.610 2220.970 3983.665 2221.790 ;
        RECT 0.100 2213.390 3983.665 2220.970 ;
        RECT 0.610 2212.570 3983.665 2213.390 ;
        RECT 0.100 2204.990 3983.665 2212.570 ;
        RECT 0.610 2204.170 3983.665 2204.990 ;
        RECT 0.100 2196.590 3983.665 2204.170 ;
        RECT 0.610 2195.770 3983.665 2196.590 ;
        RECT 0.100 2188.190 3983.665 2195.770 ;
        RECT 0.610 2187.370 3983.665 2188.190 ;
        RECT 0.100 2179.790 3983.665 2187.370 ;
        RECT 0.610 2178.970 3983.665 2179.790 ;
        RECT 0.100 2171.390 3983.665 2178.970 ;
        RECT 0.610 2170.570 3983.665 2171.390 ;
        RECT 0.100 2162.990 3983.665 2170.570 ;
        RECT 0.610 2162.170 3983.665 2162.990 ;
        RECT 0.100 2154.590 3983.665 2162.170 ;
        RECT 0.610 2153.770 3983.665 2154.590 ;
        RECT 0.100 2146.190 3983.665 2153.770 ;
        RECT 0.610 2145.370 3983.665 2146.190 ;
        RECT 0.100 2137.790 3983.665 2145.370 ;
        RECT 0.610 2136.970 3983.665 2137.790 ;
        RECT 0.100 2129.390 3983.665 2136.970 ;
        RECT 0.610 2128.570 3983.665 2129.390 ;
        RECT 0.100 2120.990 3983.665 2128.570 ;
        RECT 0.610 2120.170 3983.665 2120.990 ;
        RECT 0.100 2112.590 3983.665 2120.170 ;
        RECT 0.610 2111.770 3983.665 2112.590 ;
        RECT 0.100 2104.190 3983.665 2111.770 ;
        RECT 0.610 2103.370 3983.665 2104.190 ;
        RECT 0.100 2095.790 3983.665 2103.370 ;
        RECT 0.610 2094.970 3983.665 2095.790 ;
        RECT 0.100 2087.390 3983.665 2094.970 ;
        RECT 0.610 2086.570 3983.665 2087.390 ;
        RECT 0.100 2078.990 3983.665 2086.570 ;
        RECT 0.610 2078.170 3983.665 2078.990 ;
        RECT 0.100 2070.590 3983.665 2078.170 ;
        RECT 0.610 2069.770 3983.665 2070.590 ;
        RECT 0.100 2062.190 3983.665 2069.770 ;
        RECT 0.610 2061.370 3983.665 2062.190 ;
        RECT 0.100 2053.790 3983.665 2061.370 ;
        RECT 0.610 2052.970 3983.665 2053.790 ;
        RECT 0.100 2045.390 3983.665 2052.970 ;
        RECT 0.610 2044.570 3983.665 2045.390 ;
        RECT 0.100 2036.990 3983.665 2044.570 ;
        RECT 0.610 2036.170 3983.665 2036.990 ;
        RECT 0.100 2028.590 3983.665 2036.170 ;
        RECT 0.610 2027.770 3983.665 2028.590 ;
        RECT 0.100 2020.190 3983.665 2027.770 ;
        RECT 0.610 2019.370 3983.665 2020.190 ;
        RECT 0.100 2011.790 3983.665 2019.370 ;
        RECT 0.610 2010.970 3983.665 2011.790 ;
        RECT 0.100 2003.390 3983.665 2010.970 ;
        RECT 0.610 2002.570 3983.665 2003.390 ;
        RECT 0.100 1994.990 3983.665 2002.570 ;
        RECT 0.610 1994.170 3983.665 1994.990 ;
        RECT 0.100 1986.590 3983.665 1994.170 ;
        RECT 0.610 1985.770 3983.665 1986.590 ;
        RECT 0.100 1978.190 3983.665 1985.770 ;
        RECT 0.610 1977.370 3983.665 1978.190 ;
        RECT 0.100 1969.790 3983.665 1977.370 ;
        RECT 0.610 1968.970 3983.665 1969.790 ;
        RECT 0.100 1961.390 3983.665 1968.970 ;
        RECT 0.610 1960.570 3983.665 1961.390 ;
        RECT 0.100 1952.990 3983.665 1960.570 ;
        RECT 0.610 1952.170 3983.665 1952.990 ;
        RECT 0.100 1944.590 3983.665 1952.170 ;
        RECT 0.610 1943.770 3983.665 1944.590 ;
        RECT 0.100 1936.190 3983.665 1943.770 ;
        RECT 0.610 1935.370 3983.665 1936.190 ;
        RECT 0.100 1927.790 3983.665 1935.370 ;
        RECT 0.610 1926.970 3983.665 1927.790 ;
        RECT 0.100 1919.390 3983.665 1926.970 ;
        RECT 0.610 1918.570 3983.665 1919.390 ;
        RECT 0.100 1910.990 3983.665 1918.570 ;
        RECT 0.610 1910.170 3983.665 1910.990 ;
        RECT 0.100 1902.590 3983.665 1910.170 ;
        RECT 0.610 1901.770 3983.665 1902.590 ;
        RECT 0.100 1894.190 3983.665 1901.770 ;
        RECT 0.610 1893.370 3983.665 1894.190 ;
        RECT 0.100 1885.790 3983.665 1893.370 ;
        RECT 0.610 1884.970 3983.665 1885.790 ;
        RECT 0.100 1877.390 3983.665 1884.970 ;
        RECT 0.610 1876.570 3983.665 1877.390 ;
        RECT 0.100 1868.990 3983.665 1876.570 ;
        RECT 0.610 1868.170 3983.665 1868.990 ;
        RECT 0.100 1860.590 3983.665 1868.170 ;
        RECT 0.610 1859.770 3983.665 1860.590 ;
        RECT 0.100 1852.190 3983.665 1859.770 ;
        RECT 0.610 1851.370 3983.665 1852.190 ;
        RECT 0.100 1843.790 3983.665 1851.370 ;
        RECT 0.610 1842.970 3983.665 1843.790 ;
        RECT 0.100 1835.390 3983.665 1842.970 ;
        RECT 0.610 1834.570 3983.665 1835.390 ;
        RECT 0.100 1826.990 3983.665 1834.570 ;
        RECT 0.610 1826.170 3983.665 1826.990 ;
        RECT 0.100 1818.590 3983.665 1826.170 ;
        RECT 0.610 1817.770 3983.665 1818.590 ;
        RECT 0.100 1810.190 3983.665 1817.770 ;
        RECT 0.610 1809.370 3983.665 1810.190 ;
        RECT 0.100 1801.790 3983.665 1809.370 ;
        RECT 0.610 1800.970 3983.665 1801.790 ;
        RECT 0.100 1793.390 3983.665 1800.970 ;
        RECT 0.610 1792.570 3983.665 1793.390 ;
        RECT 0.100 1784.990 3983.665 1792.570 ;
        RECT 0.610 1784.170 3983.665 1784.990 ;
        RECT 0.100 1776.590 3983.665 1784.170 ;
        RECT 0.610 1775.770 3983.665 1776.590 ;
        RECT 0.100 1768.190 3983.665 1775.770 ;
        RECT 0.610 1767.370 3983.665 1768.190 ;
        RECT 0.100 1759.790 3983.665 1767.370 ;
        RECT 0.610 1758.970 3983.665 1759.790 ;
        RECT 0.100 1751.390 3983.665 1758.970 ;
        RECT 0.610 1750.570 3983.665 1751.390 ;
        RECT 0.100 1742.990 3983.665 1750.570 ;
        RECT 0.610 1742.170 3983.665 1742.990 ;
        RECT 0.100 1734.590 3983.665 1742.170 ;
        RECT 0.610 1733.770 3983.665 1734.590 ;
        RECT 0.100 1726.190 3983.665 1733.770 ;
        RECT 0.610 1725.370 3983.665 1726.190 ;
        RECT 0.100 1717.790 3983.665 1725.370 ;
        RECT 0.610 1716.970 3983.665 1717.790 ;
        RECT 0.100 1709.390 3983.665 1716.970 ;
        RECT 0.610 1708.570 3983.665 1709.390 ;
        RECT 0.100 1700.990 3983.665 1708.570 ;
        RECT 0.610 1700.170 3983.665 1700.990 ;
        RECT 0.100 1692.590 3983.665 1700.170 ;
        RECT 0.610 1691.770 3983.665 1692.590 ;
        RECT 0.100 1684.190 3983.665 1691.770 ;
        RECT 0.610 1683.370 3983.665 1684.190 ;
        RECT 0.100 1675.790 3983.665 1683.370 ;
        RECT 0.610 1674.970 3983.665 1675.790 ;
        RECT 0.100 1667.390 3983.665 1674.970 ;
        RECT 0.610 1666.570 3983.665 1667.390 ;
        RECT 0.100 1658.990 3983.665 1666.570 ;
        RECT 0.610 1658.170 3983.665 1658.990 ;
        RECT 0.100 1650.590 3983.665 1658.170 ;
        RECT 0.610 1649.770 3983.665 1650.590 ;
        RECT 0.100 1642.190 3983.665 1649.770 ;
        RECT 0.610 1641.370 3983.665 1642.190 ;
        RECT 0.100 1633.790 3983.665 1641.370 ;
        RECT 0.610 1632.970 3983.665 1633.790 ;
        RECT 0.100 1625.390 3983.665 1632.970 ;
        RECT 0.610 1624.570 3983.665 1625.390 ;
        RECT 0.100 1616.990 3983.665 1624.570 ;
        RECT 0.610 1616.170 3983.665 1616.990 ;
        RECT 0.100 1608.590 3983.665 1616.170 ;
        RECT 0.610 1607.770 3983.665 1608.590 ;
        RECT 0.100 1600.190 3983.665 1607.770 ;
        RECT 0.610 1599.370 3983.665 1600.190 ;
        RECT 0.100 1591.790 3983.665 1599.370 ;
        RECT 0.610 1590.970 3983.665 1591.790 ;
        RECT 0.100 1583.390 3983.665 1590.970 ;
        RECT 0.610 1582.570 3983.665 1583.390 ;
        RECT 0.100 1574.990 3983.665 1582.570 ;
        RECT 0.610 1574.170 3983.665 1574.990 ;
        RECT 0.100 1566.590 3983.665 1574.170 ;
        RECT 0.610 1565.770 3983.665 1566.590 ;
        RECT 0.100 1558.190 3983.665 1565.770 ;
        RECT 0.610 1557.370 3983.665 1558.190 ;
        RECT 0.100 1549.790 3983.665 1557.370 ;
        RECT 0.610 1548.970 3983.665 1549.790 ;
        RECT 0.100 1541.390 3983.665 1548.970 ;
        RECT 0.610 1540.570 3983.665 1541.390 ;
        RECT 0.100 1532.990 3983.665 1540.570 ;
        RECT 0.610 1532.170 3983.665 1532.990 ;
        RECT 0.100 1524.590 3983.665 1532.170 ;
        RECT 0.610 1523.770 3983.665 1524.590 ;
        RECT 0.100 1516.190 3983.665 1523.770 ;
        RECT 0.610 1515.370 3983.665 1516.190 ;
        RECT 0.100 1507.790 3983.665 1515.370 ;
        RECT 0.610 1506.970 3983.665 1507.790 ;
        RECT 0.100 1499.390 3983.665 1506.970 ;
        RECT 0.610 1498.570 3983.665 1499.390 ;
        RECT 0.100 1490.990 3983.665 1498.570 ;
        RECT 0.610 1490.170 3983.665 1490.990 ;
        RECT 0.100 1482.590 3983.665 1490.170 ;
        RECT 0.610 1481.770 3983.665 1482.590 ;
        RECT 0.100 1474.190 3983.665 1481.770 ;
        RECT 0.610 1473.370 3983.665 1474.190 ;
        RECT 0.100 1465.790 3983.665 1473.370 ;
        RECT 0.610 1464.970 3983.665 1465.790 ;
        RECT 0.100 1457.390 3983.665 1464.970 ;
        RECT 0.610 1456.570 3983.665 1457.390 ;
        RECT 0.100 1448.990 3983.665 1456.570 ;
        RECT 0.610 1448.170 3983.665 1448.990 ;
        RECT 0.100 1440.590 3983.665 1448.170 ;
        RECT 0.610 1439.770 3983.665 1440.590 ;
        RECT 0.100 1432.190 3983.665 1439.770 ;
        RECT 0.610 1431.370 3983.665 1432.190 ;
        RECT 0.100 1423.790 3983.665 1431.370 ;
        RECT 0.610 1422.970 3983.665 1423.790 ;
        RECT 0.100 1415.390 3983.665 1422.970 ;
        RECT 0.610 1414.570 3983.665 1415.390 ;
        RECT 0.100 1406.990 3983.665 1414.570 ;
        RECT 0.610 1406.170 3983.665 1406.990 ;
        RECT 0.100 1398.590 3983.665 1406.170 ;
        RECT 0.610 1397.770 3983.665 1398.590 ;
        RECT 0.100 1390.190 3983.665 1397.770 ;
        RECT 0.610 1389.370 3983.665 1390.190 ;
        RECT 0.100 1381.790 3983.665 1389.370 ;
        RECT 0.610 1380.970 3983.665 1381.790 ;
        RECT 0.100 1373.390 3983.665 1380.970 ;
        RECT 0.610 1372.570 3983.665 1373.390 ;
        RECT 0.100 1364.990 3983.665 1372.570 ;
        RECT 0.610 1364.170 3983.665 1364.990 ;
        RECT 0.100 1356.590 3983.665 1364.170 ;
        RECT 0.610 1355.770 3983.665 1356.590 ;
        RECT 0.100 1348.190 3983.665 1355.770 ;
        RECT 0.610 1347.370 3983.665 1348.190 ;
        RECT 0.100 1339.790 3983.665 1347.370 ;
        RECT 0.610 1338.970 3983.665 1339.790 ;
        RECT 0.100 1331.390 3983.665 1338.970 ;
        RECT 0.610 1330.570 3983.665 1331.390 ;
        RECT 0.100 1322.990 3983.665 1330.570 ;
        RECT 0.610 1322.170 3983.665 1322.990 ;
        RECT 0.100 1314.590 3983.665 1322.170 ;
        RECT 0.610 1313.770 3983.665 1314.590 ;
        RECT 0.100 1306.190 3983.665 1313.770 ;
        RECT 0.610 1305.370 3983.665 1306.190 ;
        RECT 0.100 1297.790 3983.665 1305.370 ;
        RECT 0.610 1296.970 3983.665 1297.790 ;
        RECT 0.100 1289.390 3983.665 1296.970 ;
        RECT 0.610 1288.570 3983.665 1289.390 ;
        RECT 0.100 1280.990 3983.665 1288.570 ;
        RECT 0.610 1280.170 3983.665 1280.990 ;
        RECT 0.100 1272.590 3983.665 1280.170 ;
        RECT 0.610 1271.770 3983.665 1272.590 ;
        RECT 0.100 1264.190 3983.665 1271.770 ;
        RECT 0.610 1263.370 3983.665 1264.190 ;
        RECT 0.100 1255.790 3983.665 1263.370 ;
        RECT 0.610 1254.970 3983.665 1255.790 ;
        RECT 0.100 1247.390 3983.665 1254.970 ;
        RECT 0.610 1246.570 3983.665 1247.390 ;
        RECT 0.100 1238.990 3983.665 1246.570 ;
        RECT 0.610 1238.170 3983.665 1238.990 ;
        RECT 0.100 1230.590 3983.665 1238.170 ;
        RECT 0.610 1229.770 3983.665 1230.590 ;
        RECT 0.100 1222.190 3983.665 1229.770 ;
        RECT 0.610 1221.370 3983.665 1222.190 ;
        RECT 0.100 1213.790 3983.665 1221.370 ;
        RECT 0.610 1212.970 3983.665 1213.790 ;
        RECT 0.100 1205.390 3983.665 1212.970 ;
        RECT 0.610 1204.570 3983.665 1205.390 ;
        RECT 0.100 1196.990 3983.665 1204.570 ;
        RECT 0.610 1196.170 3983.665 1196.990 ;
        RECT 0.100 1188.590 3983.665 1196.170 ;
        RECT 0.610 1187.770 3983.665 1188.590 ;
        RECT 0.100 1180.190 3983.665 1187.770 ;
        RECT 0.610 1179.370 3983.665 1180.190 ;
        RECT 0.100 1171.790 3983.665 1179.370 ;
        RECT 0.610 1170.970 3983.665 1171.790 ;
        RECT 0.100 1163.390 3983.665 1170.970 ;
        RECT 0.610 1162.570 3983.665 1163.390 ;
        RECT 0.100 1154.990 3983.665 1162.570 ;
        RECT 0.610 1154.170 3983.665 1154.990 ;
        RECT 0.100 1146.590 3983.665 1154.170 ;
        RECT 0.610 1145.770 3983.665 1146.590 ;
        RECT 0.100 1138.190 3983.665 1145.770 ;
        RECT 0.610 1137.370 3983.665 1138.190 ;
        RECT 0.100 1129.790 3983.665 1137.370 ;
        RECT 0.610 1128.970 3983.665 1129.790 ;
        RECT 0.100 1121.390 3983.665 1128.970 ;
        RECT 0.610 1120.570 3983.665 1121.390 ;
        RECT 0.100 1112.990 3983.665 1120.570 ;
        RECT 0.610 1112.170 3983.665 1112.990 ;
        RECT 0.100 1104.590 3983.665 1112.170 ;
        RECT 0.610 1103.770 3983.665 1104.590 ;
        RECT 0.100 1096.190 3983.665 1103.770 ;
        RECT 0.610 1095.370 3983.665 1096.190 ;
        RECT 0.100 1087.790 3983.665 1095.370 ;
        RECT 0.610 1086.970 3983.665 1087.790 ;
        RECT 0.100 1079.390 3983.665 1086.970 ;
        RECT 0.610 1078.570 3983.665 1079.390 ;
        RECT 0.100 1070.990 3983.665 1078.570 ;
        RECT 0.610 1070.170 3983.665 1070.990 ;
        RECT 0.100 1062.590 3983.665 1070.170 ;
        RECT 0.610 1061.770 3983.665 1062.590 ;
        RECT 0.100 1054.190 3983.665 1061.770 ;
        RECT 0.610 1053.370 3983.665 1054.190 ;
        RECT 0.100 1045.790 3983.665 1053.370 ;
        RECT 0.610 1044.970 3983.665 1045.790 ;
        RECT 0.100 1037.390 3983.665 1044.970 ;
        RECT 0.610 1036.570 3983.665 1037.390 ;
        RECT 0.100 1028.990 3983.665 1036.570 ;
        RECT 0.610 1028.170 3983.665 1028.990 ;
        RECT 0.100 1020.590 3983.665 1028.170 ;
        RECT 0.610 1019.770 3983.665 1020.590 ;
        RECT 0.100 1012.190 3983.665 1019.770 ;
        RECT 0.610 1011.370 3983.665 1012.190 ;
        RECT 0.100 1003.790 3983.665 1011.370 ;
        RECT 0.610 1002.970 3983.665 1003.790 ;
        RECT 0.100 995.390 3983.665 1002.970 ;
        RECT 0.610 994.570 3983.665 995.390 ;
        RECT 0.100 986.990 3983.665 994.570 ;
        RECT 0.610 986.170 3983.665 986.990 ;
        RECT 0.100 978.590 3983.665 986.170 ;
        RECT 0.610 977.770 3983.665 978.590 ;
        RECT 0.100 970.190 3983.665 977.770 ;
        RECT 0.610 969.370 3983.665 970.190 ;
        RECT 0.100 961.790 3983.665 969.370 ;
        RECT 0.610 960.970 3983.665 961.790 ;
        RECT 0.100 953.390 3983.665 960.970 ;
        RECT 0.610 952.570 3983.665 953.390 ;
        RECT 0.100 944.990 3983.665 952.570 ;
        RECT 0.610 944.170 3983.665 944.990 ;
        RECT 0.100 936.590 3983.665 944.170 ;
        RECT 0.610 935.770 3983.665 936.590 ;
        RECT 0.100 928.190 3983.665 935.770 ;
        RECT 0.610 927.370 3983.665 928.190 ;
        RECT 0.100 919.790 3983.665 927.370 ;
        RECT 0.610 918.970 3983.665 919.790 ;
        RECT 0.100 911.390 3983.665 918.970 ;
        RECT 0.610 910.570 3983.665 911.390 ;
        RECT 0.100 902.990 3983.665 910.570 ;
        RECT 0.610 902.170 3983.665 902.990 ;
        RECT 0.100 894.590 3983.665 902.170 ;
        RECT 0.610 893.770 3983.665 894.590 ;
        RECT 0.100 886.190 3983.665 893.770 ;
        RECT 0.610 885.370 3983.665 886.190 ;
        RECT 0.100 877.790 3983.665 885.370 ;
        RECT 0.610 876.970 3983.665 877.790 ;
        RECT 0.100 869.390 3983.665 876.970 ;
        RECT 0.610 868.570 3983.665 869.390 ;
        RECT 0.100 860.990 3983.665 868.570 ;
        RECT 0.610 860.170 3983.665 860.990 ;
        RECT 0.100 852.590 3983.665 860.170 ;
        RECT 0.610 851.770 3983.665 852.590 ;
        RECT 0.100 844.190 3983.665 851.770 ;
        RECT 0.610 843.370 3983.665 844.190 ;
        RECT 0.100 835.790 3983.665 843.370 ;
        RECT 0.610 834.970 3983.665 835.790 ;
        RECT 0.100 827.390 3983.665 834.970 ;
        RECT 0.610 826.570 3983.665 827.390 ;
        RECT 0.100 818.990 3983.665 826.570 ;
        RECT 0.610 818.170 3983.665 818.990 ;
        RECT 0.100 810.590 3983.665 818.170 ;
        RECT 0.610 809.770 3983.665 810.590 ;
        RECT 0.100 802.190 3983.665 809.770 ;
        RECT 0.610 801.370 3983.665 802.190 ;
        RECT 0.100 793.790 3983.665 801.370 ;
        RECT 0.610 792.970 3983.665 793.790 ;
        RECT 0.100 785.390 3983.665 792.970 ;
        RECT 0.610 784.570 3983.665 785.390 ;
        RECT 0.100 776.990 3983.665 784.570 ;
        RECT 0.610 776.170 3983.665 776.990 ;
        RECT 0.100 768.590 3983.665 776.170 ;
        RECT 0.610 767.770 3983.665 768.590 ;
        RECT 0.100 760.190 3983.665 767.770 ;
        RECT 0.610 759.370 3983.665 760.190 ;
        RECT 0.100 751.790 3983.665 759.370 ;
        RECT 0.610 750.970 3983.665 751.790 ;
        RECT 0.100 743.390 3983.665 750.970 ;
        RECT 0.610 742.570 3983.665 743.390 ;
        RECT 0.100 734.990 3983.665 742.570 ;
        RECT 0.610 734.170 3983.665 734.990 ;
        RECT 0.100 726.590 3983.665 734.170 ;
        RECT 0.610 725.770 3983.665 726.590 ;
        RECT 0.100 718.190 3983.665 725.770 ;
        RECT 0.610 717.370 3983.665 718.190 ;
        RECT 0.100 709.790 3983.665 717.370 ;
        RECT 0.610 708.970 3983.665 709.790 ;
        RECT 0.100 701.390 3983.665 708.970 ;
        RECT 0.610 700.570 3983.665 701.390 ;
        RECT 0.100 692.990 3983.665 700.570 ;
        RECT 0.610 692.170 3983.665 692.990 ;
        RECT 0.100 684.590 3983.665 692.170 ;
        RECT 0.610 683.770 3983.665 684.590 ;
        RECT 0.100 676.190 3983.665 683.770 ;
        RECT 0.610 675.370 3983.665 676.190 ;
        RECT 0.100 667.790 3983.665 675.370 ;
        RECT 0.610 666.970 3983.665 667.790 ;
        RECT 0.100 659.390 3983.665 666.970 ;
        RECT 0.610 658.570 3983.665 659.390 ;
        RECT 0.100 650.990 3983.665 658.570 ;
        RECT 0.610 650.170 3983.665 650.990 ;
        RECT 0.100 642.590 3983.665 650.170 ;
        RECT 0.610 641.770 3983.665 642.590 ;
        RECT 0.100 634.190 3983.665 641.770 ;
        RECT 0.610 633.370 3983.665 634.190 ;
        RECT 0.100 625.790 3983.665 633.370 ;
        RECT 0.610 624.970 3983.665 625.790 ;
        RECT 0.100 617.390 3983.665 624.970 ;
        RECT 0.610 616.570 3983.665 617.390 ;
        RECT 0.100 608.990 3983.665 616.570 ;
        RECT 0.610 608.170 3983.665 608.990 ;
        RECT 0.100 600.590 3983.665 608.170 ;
        RECT 0.610 599.770 3983.665 600.590 ;
        RECT 0.100 592.190 3983.665 599.770 ;
        RECT 0.610 591.370 3983.665 592.190 ;
        RECT 0.100 583.790 3983.665 591.370 ;
        RECT 0.610 582.970 3983.665 583.790 ;
        RECT 0.100 575.390 3983.665 582.970 ;
        RECT 0.610 574.570 3983.665 575.390 ;
        RECT 0.100 566.990 3983.665 574.570 ;
        RECT 0.610 566.170 3983.665 566.990 ;
        RECT 0.100 558.590 3983.665 566.170 ;
        RECT 0.610 557.770 3983.665 558.590 ;
        RECT 0.100 550.190 3983.665 557.770 ;
        RECT 0.610 549.370 3983.665 550.190 ;
        RECT 0.100 541.790 3983.665 549.370 ;
        RECT 0.610 540.970 3983.665 541.790 ;
        RECT 0.100 533.390 3983.665 540.970 ;
        RECT 0.610 532.570 3983.665 533.390 ;
        RECT 0.100 524.990 3983.665 532.570 ;
        RECT 0.610 524.170 3983.665 524.990 ;
        RECT 0.100 516.590 3983.665 524.170 ;
        RECT 0.610 515.770 3983.665 516.590 ;
        RECT 0.100 508.190 3983.665 515.770 ;
        RECT 0.610 507.370 3983.665 508.190 ;
        RECT 0.100 499.790 3983.665 507.370 ;
        RECT 0.610 498.970 3983.665 499.790 ;
        RECT 0.100 491.390 3983.665 498.970 ;
        RECT 0.610 490.570 3983.665 491.390 ;
        RECT 0.100 482.990 3983.665 490.570 ;
        RECT 0.610 482.170 3983.665 482.990 ;
        RECT 0.100 474.590 3983.665 482.170 ;
        RECT 0.610 473.770 3983.665 474.590 ;
        RECT 0.100 466.190 3983.665 473.770 ;
        RECT 0.610 465.370 3983.665 466.190 ;
        RECT 0.100 457.790 3983.665 465.370 ;
        RECT 0.610 456.970 3983.665 457.790 ;
        RECT 0.100 449.390 3983.665 456.970 ;
        RECT 0.610 448.570 3983.665 449.390 ;
        RECT 0.100 440.990 3983.665 448.570 ;
        RECT 0.610 440.170 3983.665 440.990 ;
        RECT 0.100 432.590 3983.665 440.170 ;
        RECT 0.610 431.770 3983.665 432.590 ;
        RECT 0.100 424.190 3983.665 431.770 ;
        RECT 0.610 423.370 3983.665 424.190 ;
        RECT 0.100 415.790 3983.665 423.370 ;
        RECT 0.610 414.970 3983.665 415.790 ;
        RECT 0.100 407.390 3983.665 414.970 ;
        RECT 0.610 406.570 3983.665 407.390 ;
        RECT 0.100 398.990 3983.665 406.570 ;
        RECT 0.610 398.170 3983.665 398.990 ;
        RECT 0.100 390.590 3983.665 398.170 ;
        RECT 0.610 389.770 3983.665 390.590 ;
        RECT 0.100 382.190 3983.665 389.770 ;
        RECT 0.610 381.370 3983.665 382.190 ;
        RECT 0.100 373.790 3983.665 381.370 ;
        RECT 0.610 372.970 3983.665 373.790 ;
        RECT 0.100 365.390 3983.665 372.970 ;
        RECT 0.610 364.570 3983.665 365.390 ;
        RECT 0.100 356.990 3983.665 364.570 ;
        RECT 0.610 356.170 3983.665 356.990 ;
        RECT 0.100 348.590 3983.665 356.170 ;
        RECT 0.610 347.770 3983.665 348.590 ;
        RECT 0.100 340.190 3983.665 347.770 ;
        RECT 0.610 339.370 3983.665 340.190 ;
        RECT 0.100 331.790 3983.665 339.370 ;
        RECT 0.610 330.970 3983.665 331.790 ;
        RECT 0.100 323.390 3983.665 330.970 ;
        RECT 0.610 322.570 3983.665 323.390 ;
        RECT 0.100 314.990 3983.665 322.570 ;
        RECT 0.610 314.170 3983.665 314.990 ;
        RECT 0.100 306.590 3983.665 314.170 ;
        RECT 0.610 305.770 3983.665 306.590 ;
        RECT 0.100 298.190 3983.665 305.770 ;
        RECT 0.610 297.370 3983.665 298.190 ;
        RECT 0.100 289.790 3983.665 297.370 ;
        RECT 0.610 288.970 3983.665 289.790 ;
        RECT 0.100 281.390 3983.665 288.970 ;
        RECT 0.610 280.570 3983.665 281.390 ;
        RECT 0.100 272.990 3983.665 280.570 ;
        RECT 0.610 272.170 3983.665 272.990 ;
        RECT 0.100 264.590 3983.665 272.170 ;
        RECT 0.610 263.770 3983.665 264.590 ;
        RECT 0.100 256.190 3983.665 263.770 ;
        RECT 0.610 255.370 3983.665 256.190 ;
        RECT 0.100 247.790 3983.665 255.370 ;
        RECT 0.610 246.970 3983.665 247.790 ;
        RECT 0.100 239.390 3983.665 246.970 ;
        RECT 0.610 238.570 3983.665 239.390 ;
        RECT 0.100 230.990 3983.665 238.570 ;
        RECT 0.610 230.170 3983.665 230.990 ;
        RECT 0.100 222.590 3983.665 230.170 ;
        RECT 0.610 221.770 3983.665 222.590 ;
        RECT 0.100 214.190 3983.665 221.770 ;
        RECT 0.610 213.370 3983.665 214.190 ;
        RECT 0.100 205.790 3983.665 213.370 ;
        RECT 0.610 204.970 3983.665 205.790 ;
        RECT 0.100 197.390 3983.665 204.970 ;
        RECT 0.610 196.570 3983.665 197.390 ;
        RECT 0.100 188.990 3983.665 196.570 ;
        RECT 0.610 188.170 3983.665 188.990 ;
        RECT 0.100 180.590 3983.665 188.170 ;
        RECT 0.610 179.770 3983.665 180.590 ;
        RECT 0.100 172.190 3983.665 179.770 ;
        RECT 0.610 171.370 3983.665 172.190 ;
        RECT 0.100 163.790 3983.665 171.370 ;
        RECT 0.610 162.970 3983.665 163.790 ;
        RECT 0.100 155.390 3983.665 162.970 ;
        RECT 0.610 154.570 3983.665 155.390 ;
        RECT 0.100 146.990 3983.665 154.570 ;
        RECT 0.610 146.170 3983.665 146.990 ;
        RECT 0.100 138.590 3983.665 146.170 ;
        RECT 0.610 137.770 3983.665 138.590 ;
        RECT 0.100 130.190 3983.665 137.770 ;
        RECT 0.610 129.370 3983.665 130.190 ;
        RECT 0.100 121.790 3983.665 129.370 ;
        RECT 0.610 120.970 3983.665 121.790 ;
        RECT 0.100 113.390 3983.665 120.970 ;
        RECT 0.610 112.570 3983.665 113.390 ;
        RECT 0.100 104.990 3983.665 112.570 ;
        RECT 0.610 104.170 3983.665 104.990 ;
        RECT 0.100 96.590 3983.665 104.170 ;
        RECT 0.610 95.770 3983.665 96.590 ;
        RECT 0.100 88.190 3983.665 95.770 ;
        RECT 0.610 87.370 3983.665 88.190 ;
        RECT 0.100 79.790 3983.665 87.370 ;
        RECT 0.610 78.970 3983.665 79.790 ;
        RECT 0.100 71.390 3983.665 78.970 ;
        RECT 0.610 70.570 3983.665 71.390 ;
        RECT 0.100 6.620 3983.665 70.570 ;
      LAYER Metal4 ;
        RECT 0.380 35.530 15.050 4212.325 ;
        RECT 16.470 35.530 18.050 4212.325 ;
        RECT 19.470 35.530 65.050 4212.325 ;
        RECT 66.470 35.530 68.050 4212.325 ;
        RECT 69.470 35.530 115.050 4212.325 ;
        RECT 116.470 35.530 118.050 4212.325 ;
        RECT 119.470 35.530 165.050 4212.325 ;
        RECT 166.470 35.530 168.050 4212.325 ;
        RECT 169.470 35.530 215.050 4212.325 ;
        RECT 216.470 35.530 218.050 4212.325 ;
        RECT 219.470 4048.785 265.050 4212.325 ;
        RECT 266.470 4048.785 268.050 4212.325 ;
        RECT 269.470 4048.785 315.050 4212.325 ;
        RECT 316.470 4048.785 318.050 4212.325 ;
        RECT 319.470 4048.785 365.050 4212.325 ;
        RECT 366.470 4048.785 368.050 4212.325 ;
        RECT 369.470 4048.785 415.050 4212.325 ;
        RECT 416.470 4048.785 418.050 4212.325 ;
        RECT 419.470 4048.785 465.050 4212.325 ;
        RECT 466.470 4048.785 468.050 4212.325 ;
        RECT 469.470 4048.785 515.050 4212.325 ;
        RECT 516.470 4048.785 518.050 4212.325 ;
        RECT 519.470 4048.785 565.050 4212.325 ;
        RECT 566.470 4048.785 568.050 4212.325 ;
        RECT 569.470 4048.785 615.050 4212.325 ;
        RECT 616.470 4048.785 618.050 4212.325 ;
        RECT 619.470 4048.785 665.050 4212.325 ;
        RECT 666.470 4048.785 668.050 4212.325 ;
        RECT 669.470 4048.785 715.050 4212.325 ;
        RECT 716.470 4048.785 718.050 4212.325 ;
        RECT 719.470 4048.785 765.050 4212.325 ;
        RECT 766.470 4048.785 768.050 4212.325 ;
        RECT 769.470 4048.785 815.050 4212.325 ;
        RECT 816.470 4048.785 818.050 4212.325 ;
        RECT 819.470 4048.785 865.050 4212.325 ;
        RECT 866.470 4048.785 868.050 4212.325 ;
        RECT 869.470 4048.785 915.050 4212.325 ;
        RECT 916.470 4048.785 918.050 4212.325 ;
        RECT 919.470 4048.785 965.050 4212.325 ;
        RECT 966.470 4048.785 968.050 4212.325 ;
        RECT 969.470 4048.785 1015.050 4212.325 ;
        RECT 1016.470 4048.785 1018.050 4212.325 ;
        RECT 1019.470 4048.785 1065.050 4212.325 ;
        RECT 1066.470 4048.785 1068.050 4212.325 ;
        RECT 1069.470 4048.785 1115.050 4212.325 ;
        RECT 1116.470 4048.785 1118.050 4212.325 ;
        RECT 1119.470 4048.785 1165.050 4212.325 ;
        RECT 1166.470 4048.785 1168.050 4212.325 ;
        RECT 1169.470 4048.785 1215.050 4212.325 ;
        RECT 1216.470 4048.785 1218.050 4212.325 ;
        RECT 1219.470 4048.785 1265.050 4212.325 ;
        RECT 1266.470 4048.785 1268.050 4212.325 ;
        RECT 1269.470 4048.785 1315.050 4212.325 ;
        RECT 1316.470 4048.785 1318.050 4212.325 ;
        RECT 1319.470 4048.785 1365.050 4212.325 ;
        RECT 1366.470 4048.785 1368.050 4212.325 ;
        RECT 1369.470 4048.785 1415.050 4212.325 ;
        RECT 1416.470 4048.785 1418.050 4212.325 ;
        RECT 1419.470 4048.785 1465.050 4212.325 ;
        RECT 1466.470 4048.785 1468.050 4212.325 ;
        RECT 1469.470 4048.785 1515.050 4212.325 ;
        RECT 1516.470 4048.785 1518.050 4212.325 ;
        RECT 1519.470 4048.785 1565.050 4212.325 ;
        RECT 1566.470 4048.785 1568.050 4212.325 ;
        RECT 1569.470 4048.785 1615.050 4212.325 ;
        RECT 1616.470 4048.785 1618.050 4212.325 ;
        RECT 1619.470 4048.785 1665.050 4212.325 ;
        RECT 1666.470 4048.785 1668.050 4212.325 ;
        RECT 1669.470 4049.300 1715.050 4212.325 ;
        RECT 1716.470 4049.300 1718.050 4212.325 ;
        RECT 1669.470 4048.785 1718.050 4049.300 ;
        RECT 1719.470 4049.300 1765.050 4212.325 ;
        RECT 1766.470 4049.300 1768.050 4212.325 ;
        RECT 1719.470 4048.785 1768.050 4049.300 ;
        RECT 1769.470 4049.300 1815.050 4212.325 ;
        RECT 1816.470 4049.300 1818.050 4212.325 ;
        RECT 1769.470 4048.785 1818.050 4049.300 ;
        RECT 1819.470 4049.300 1865.050 4212.325 ;
        RECT 1866.470 4049.300 1868.050 4212.325 ;
        RECT 1819.470 4048.785 1868.050 4049.300 ;
        RECT 1869.470 4049.300 1915.050 4212.325 ;
        RECT 1916.470 4049.300 1918.050 4212.325 ;
        RECT 1869.470 4048.785 1918.050 4049.300 ;
        RECT 1919.470 4049.300 1965.050 4212.325 ;
        RECT 1966.470 4049.300 1968.050 4212.325 ;
        RECT 1919.470 4048.785 1968.050 4049.300 ;
        RECT 1969.470 4048.785 2015.050 4212.325 ;
        RECT 2016.470 4048.785 2018.050 4212.325 ;
        RECT 2019.470 4048.785 2065.050 4212.325 ;
        RECT 2066.470 4048.785 2068.050 4212.325 ;
        RECT 2069.470 4048.785 2115.050 4212.325 ;
        RECT 2116.470 4048.785 2118.050 4212.325 ;
        RECT 2119.470 4048.785 2165.050 4212.325 ;
        RECT 2166.470 4048.785 2168.050 4212.325 ;
        RECT 2169.470 4048.785 2215.050 4212.325 ;
        RECT 2216.470 4048.785 2218.050 4212.325 ;
        RECT 2219.470 4048.785 2265.050 4212.325 ;
        RECT 2266.470 4048.785 2268.050 4212.325 ;
        RECT 2269.470 4048.785 2315.050 4212.325 ;
        RECT 2316.470 4048.785 2318.050 4212.325 ;
        RECT 2319.470 4048.785 2365.050 4212.325 ;
        RECT 2366.470 4048.785 2368.050 4212.325 ;
        RECT 2369.470 4048.785 2415.050 4212.325 ;
        RECT 2416.470 4048.785 2418.050 4212.325 ;
        RECT 2419.470 4048.785 2465.050 4212.325 ;
        RECT 2466.470 4048.785 2468.050 4212.325 ;
        RECT 2469.470 4048.785 2515.050 4212.325 ;
        RECT 2516.470 4048.785 2518.050 4212.325 ;
        RECT 2519.470 4048.785 2565.050 4212.325 ;
        RECT 2566.470 4048.785 2568.050 4212.325 ;
        RECT 2569.470 4048.785 2615.050 4212.325 ;
        RECT 2616.470 4048.785 2618.050 4212.325 ;
        RECT 2619.470 4048.785 2665.050 4212.325 ;
        RECT 2666.470 4048.785 2668.050 4212.325 ;
        RECT 2669.470 4048.785 2715.050 4212.325 ;
        RECT 2716.470 4048.785 2718.050 4212.325 ;
        RECT 2719.470 4048.785 2765.050 4212.325 ;
        RECT 2766.470 4048.785 2768.050 4212.325 ;
        RECT 2769.470 4048.785 2815.050 4212.325 ;
        RECT 2816.470 4048.785 2818.050 4212.325 ;
        RECT 2819.470 4048.785 2865.050 4212.325 ;
        RECT 2866.470 4048.785 2868.050 4212.325 ;
        RECT 2869.470 4048.785 2915.050 4212.325 ;
        RECT 219.470 3799.240 2915.050 4048.785 ;
        RECT 2916.470 3799.240 2918.050 4212.325 ;
        RECT 2919.470 3799.240 2965.050 4212.325 ;
        RECT 2966.470 3799.240 2968.050 4212.325 ;
        RECT 2969.470 3799.240 3015.050 4212.325 ;
        RECT 3016.470 3799.240 3018.050 4212.325 ;
        RECT 3019.470 3799.240 3065.050 4212.325 ;
        RECT 219.470 3524.180 3065.050 3799.240 ;
        RECT 219.470 3338.920 2915.050 3524.180 ;
        RECT 2916.470 3338.920 2918.050 3524.180 ;
        RECT 2919.470 3338.920 2965.050 3524.180 ;
        RECT 2966.470 3338.920 2968.050 3524.180 ;
        RECT 2969.470 3338.920 3015.050 3524.180 ;
        RECT 3016.470 3338.920 3018.050 3524.180 ;
        RECT 3019.470 3338.920 3065.050 3524.180 ;
        RECT 219.470 3063.860 3065.050 3338.920 ;
        RECT 219.470 2878.600 2915.050 3063.860 ;
        RECT 2916.470 2878.600 2918.050 3063.860 ;
        RECT 2919.470 2878.600 2965.050 3063.860 ;
        RECT 2966.470 2878.600 2968.050 3063.860 ;
        RECT 2969.470 2878.600 3015.050 3063.860 ;
        RECT 3016.470 2878.600 3018.050 3063.860 ;
        RECT 3019.470 2878.600 3065.050 3063.860 ;
        RECT 219.470 2603.540 3065.050 2878.600 ;
        RECT 219.470 2418.280 2915.050 2603.540 ;
        RECT 2916.470 2418.280 2918.050 2603.540 ;
        RECT 2919.470 2418.280 2965.050 2603.540 ;
        RECT 2966.470 2418.280 2968.050 2603.540 ;
        RECT 2969.470 2418.280 3015.050 2603.540 ;
        RECT 3016.470 2418.280 3018.050 2603.540 ;
        RECT 3019.470 2418.280 3065.050 2603.540 ;
        RECT 219.470 2143.220 3065.050 2418.280 ;
        RECT 219.470 1957.960 2915.050 2143.220 ;
        RECT 2916.470 1957.960 2918.050 2143.220 ;
        RECT 2919.470 1957.960 2965.050 2143.220 ;
        RECT 2966.470 1957.960 2968.050 2143.220 ;
        RECT 2969.470 1957.960 3015.050 2143.220 ;
        RECT 3016.470 1957.960 3018.050 2143.220 ;
        RECT 3019.470 1957.960 3065.050 2143.220 ;
        RECT 219.470 1682.900 3065.050 1957.960 ;
        RECT 219.470 1497.640 2915.050 1682.900 ;
        RECT 2916.470 1497.640 2918.050 1682.900 ;
        RECT 2919.470 1497.640 2965.050 1682.900 ;
        RECT 2966.470 1497.640 2968.050 1682.900 ;
        RECT 2969.470 1497.640 3015.050 1682.900 ;
        RECT 3016.470 1497.640 3018.050 1682.900 ;
        RECT 3019.470 1497.640 3065.050 1682.900 ;
        RECT 219.470 1222.580 3065.050 1497.640 ;
        RECT 219.470 1037.320 2915.050 1222.580 ;
        RECT 2916.470 1037.320 2918.050 1222.580 ;
        RECT 2919.470 1037.320 2965.050 1222.580 ;
        RECT 2966.470 1037.320 2968.050 1222.580 ;
        RECT 2969.470 1037.320 3015.050 1222.580 ;
        RECT 3016.470 1037.320 3018.050 1222.580 ;
        RECT 3019.470 1037.320 3065.050 1222.580 ;
        RECT 219.470 762.260 3065.050 1037.320 ;
        RECT 219.470 577.000 2915.050 762.260 ;
        RECT 2916.470 577.000 2918.050 762.260 ;
        RECT 2919.470 577.000 2965.050 762.260 ;
        RECT 2966.470 577.000 2968.050 762.260 ;
        RECT 2969.470 577.000 3015.050 762.260 ;
        RECT 3016.470 577.000 3018.050 762.260 ;
        RECT 3019.470 577.000 3065.050 762.260 ;
        RECT 219.470 301.940 3065.050 577.000 ;
        RECT 219.470 196.355 2915.050 301.940 ;
        RECT 219.470 35.530 265.050 196.355 ;
        RECT 266.470 35.530 268.050 196.355 ;
        RECT 269.470 35.530 315.050 196.355 ;
        RECT 316.470 35.530 318.050 196.355 ;
        RECT 319.470 35.530 365.050 196.355 ;
        RECT 366.470 35.530 368.050 196.355 ;
        RECT 369.470 35.530 415.050 196.355 ;
        RECT 416.470 35.530 418.050 196.355 ;
        RECT 419.470 35.530 465.050 196.355 ;
        RECT 466.470 35.530 468.050 196.355 ;
        RECT 469.470 35.530 515.050 196.355 ;
        RECT 516.470 35.530 518.050 196.355 ;
        RECT 519.470 35.530 565.050 196.355 ;
        RECT 566.470 35.530 568.050 196.355 ;
        RECT 569.470 35.530 615.050 196.355 ;
        RECT 616.470 35.530 618.050 196.355 ;
        RECT 619.470 35.530 665.050 196.355 ;
        RECT 666.470 35.530 668.050 196.355 ;
        RECT 669.470 35.530 715.050 196.355 ;
        RECT 716.470 35.530 718.050 196.355 ;
        RECT 719.470 35.530 765.050 196.355 ;
        RECT 766.470 35.530 768.050 196.355 ;
        RECT 769.470 35.530 815.050 196.355 ;
        RECT 816.470 35.530 818.050 196.355 ;
        RECT 819.470 35.530 865.050 196.355 ;
        RECT 866.470 35.530 868.050 196.355 ;
        RECT 869.470 35.530 915.050 196.355 ;
        RECT 916.470 35.530 918.050 196.355 ;
        RECT 919.470 35.530 965.050 196.355 ;
        RECT 966.470 35.530 968.050 196.355 ;
        RECT 969.470 35.530 1015.050 196.355 ;
        RECT 1016.470 35.530 1018.050 196.355 ;
        RECT 1019.470 35.530 1065.050 196.355 ;
        RECT 1066.470 35.530 1068.050 196.355 ;
        RECT 1069.470 35.530 1115.050 196.355 ;
        RECT 1116.470 35.530 1118.050 196.355 ;
        RECT 1119.470 35.530 1165.050 196.355 ;
        RECT 1166.470 35.530 1168.050 196.355 ;
        RECT 1169.470 35.530 1215.050 196.355 ;
        RECT 1216.470 35.530 1218.050 196.355 ;
        RECT 1219.470 35.530 1265.050 196.355 ;
        RECT 1266.470 35.530 1268.050 196.355 ;
        RECT 1269.470 35.530 1315.050 196.355 ;
        RECT 1316.470 35.530 1318.050 196.355 ;
        RECT 1319.470 35.530 1365.050 196.355 ;
        RECT 1366.470 35.530 1368.050 196.355 ;
        RECT 1369.470 35.530 1415.050 196.355 ;
        RECT 1416.470 35.530 1418.050 196.355 ;
        RECT 1419.470 35.530 1465.050 196.355 ;
        RECT 1466.470 35.530 1468.050 196.355 ;
        RECT 1469.470 35.530 1515.050 196.355 ;
        RECT 1516.470 35.530 1518.050 196.355 ;
        RECT 1519.470 35.530 1565.050 196.355 ;
        RECT 1566.470 35.530 1568.050 196.355 ;
        RECT 1569.470 35.530 1615.050 196.355 ;
        RECT 1616.470 35.530 1618.050 196.355 ;
        RECT 1619.470 35.530 1665.050 196.355 ;
        RECT 1666.470 35.530 1668.050 196.355 ;
        RECT 1669.470 195.840 1718.050 196.355 ;
        RECT 1669.470 35.530 1715.050 195.840 ;
        RECT 1716.470 35.530 1718.050 195.840 ;
        RECT 1719.470 195.840 1768.050 196.355 ;
        RECT 1719.470 35.530 1765.050 195.840 ;
        RECT 1766.470 35.530 1768.050 195.840 ;
        RECT 1769.470 195.840 1818.050 196.355 ;
        RECT 1769.470 35.530 1815.050 195.840 ;
        RECT 1816.470 35.530 1818.050 195.840 ;
        RECT 1819.470 195.840 1868.050 196.355 ;
        RECT 1819.470 35.530 1865.050 195.840 ;
        RECT 1866.470 35.530 1868.050 195.840 ;
        RECT 1869.470 195.840 1918.050 196.355 ;
        RECT 1869.470 35.530 1915.050 195.840 ;
        RECT 1916.470 35.530 1918.050 195.840 ;
        RECT 1919.470 195.840 1968.050 196.355 ;
        RECT 1919.470 35.530 1965.050 195.840 ;
        RECT 1966.470 35.530 1968.050 195.840 ;
        RECT 1969.470 35.530 2015.050 196.355 ;
        RECT 2016.470 35.530 2018.050 196.355 ;
        RECT 2019.470 35.530 2065.050 196.355 ;
        RECT 2066.470 35.530 2068.050 196.355 ;
        RECT 2069.470 35.530 2115.050 196.355 ;
        RECT 2116.470 35.530 2118.050 196.355 ;
        RECT 2119.470 35.530 2165.050 196.355 ;
        RECT 2166.470 35.530 2168.050 196.355 ;
        RECT 2169.470 35.530 2215.050 196.355 ;
        RECT 2216.470 35.530 2218.050 196.355 ;
        RECT 2219.470 35.530 2265.050 196.355 ;
        RECT 2266.470 35.530 2268.050 196.355 ;
        RECT 2269.470 35.530 2315.050 196.355 ;
        RECT 2316.470 35.530 2318.050 196.355 ;
        RECT 2319.470 35.530 2365.050 196.355 ;
        RECT 2366.470 35.530 2368.050 196.355 ;
        RECT 2369.470 35.530 2415.050 196.355 ;
        RECT 2416.470 35.530 2418.050 196.355 ;
        RECT 2419.470 35.530 2465.050 196.355 ;
        RECT 2466.470 35.530 2468.050 196.355 ;
        RECT 2469.470 35.530 2515.050 196.355 ;
        RECT 2516.470 35.530 2518.050 196.355 ;
        RECT 2519.470 35.530 2565.050 196.355 ;
        RECT 2566.470 35.530 2568.050 196.355 ;
        RECT 2569.470 35.530 2615.050 196.355 ;
        RECT 2616.470 35.530 2618.050 196.355 ;
        RECT 2619.470 35.530 2665.050 196.355 ;
        RECT 2666.470 35.530 2668.050 196.355 ;
        RECT 2669.470 35.530 2715.050 196.355 ;
        RECT 2716.470 35.530 2718.050 196.355 ;
        RECT 2719.470 35.530 2765.050 196.355 ;
        RECT 2766.470 35.530 2768.050 196.355 ;
        RECT 2769.470 35.530 2815.050 196.355 ;
        RECT 2816.470 35.530 2818.050 196.355 ;
        RECT 2819.470 35.530 2865.050 196.355 ;
        RECT 2866.470 35.530 2868.050 196.355 ;
        RECT 2869.470 35.530 2915.050 196.355 ;
        RECT 2916.470 35.530 2918.050 301.940 ;
        RECT 2919.470 35.530 2965.050 301.940 ;
        RECT 2966.470 35.530 2968.050 301.940 ;
        RECT 2969.470 35.530 3015.050 301.940 ;
        RECT 3016.470 35.530 3018.050 301.940 ;
        RECT 3019.470 35.530 3065.050 301.940 ;
        RECT 3066.470 35.530 3068.050 4212.325 ;
        RECT 3069.470 35.530 3115.050 4212.325 ;
        RECT 3116.470 35.530 3118.050 4212.325 ;
        RECT 3119.470 35.530 3165.050 4212.325 ;
        RECT 3166.470 35.530 3168.050 4212.325 ;
        RECT 3169.470 35.530 3215.050 4212.325 ;
        RECT 3216.470 35.530 3218.050 4212.325 ;
        RECT 3219.470 35.530 3265.050 4212.325 ;
        RECT 3266.470 35.530 3268.050 4212.325 ;
        RECT 3269.470 35.530 3315.050 4212.325 ;
        RECT 3316.470 35.530 3318.050 4212.325 ;
        RECT 3319.470 35.530 3365.050 4212.325 ;
        RECT 3366.470 35.530 3368.050 4212.325 ;
        RECT 3369.470 35.530 3415.050 4212.325 ;
        RECT 3416.470 35.530 3418.050 4212.325 ;
        RECT 3419.470 35.530 3465.050 4212.325 ;
        RECT 3466.470 35.530 3468.050 4212.325 ;
        RECT 3469.470 35.530 3515.050 4212.325 ;
        RECT 3516.470 35.530 3518.050 4212.325 ;
        RECT 3519.470 4170.300 3565.050 4212.325 ;
        RECT 3566.470 4170.300 3568.050 4212.325 ;
        RECT 3569.470 4170.300 3615.050 4212.325 ;
        RECT 3616.470 4170.300 3618.050 4212.325 ;
        RECT 3619.470 4170.300 3665.050 4212.325 ;
        RECT 3666.470 4170.300 3668.050 4212.325 ;
        RECT 3669.470 4170.300 3715.050 4212.325 ;
        RECT 3716.470 4170.300 3718.050 4212.325 ;
        RECT 3719.470 4170.300 3765.050 4212.325 ;
        RECT 3766.470 4170.300 3768.050 4212.325 ;
        RECT 3769.470 4170.300 3815.050 4212.325 ;
        RECT 3816.470 4170.300 3818.050 4212.325 ;
        RECT 3819.470 4170.300 3865.050 4212.325 ;
        RECT 3866.470 4170.300 3868.050 4212.325 ;
        RECT 3869.470 4170.300 3915.050 4212.325 ;
        RECT 3916.470 4170.300 3918.050 4212.325 ;
        RECT 3919.470 4170.300 3965.050 4212.325 ;
        RECT 3966.470 4170.300 3968.050 4212.325 ;
        RECT 3969.470 4170.300 3976.630 4212.325 ;
        RECT 3519.470 3705.175 3976.630 4170.300 ;
        RECT 3519.470 3663.970 3568.050 3705.175 ;
        RECT 3569.470 3663.970 3618.050 3705.175 ;
        RECT 3619.470 3663.970 3668.050 3705.175 ;
        RECT 3669.470 3663.970 3718.050 3705.175 ;
        RECT 3719.470 3663.970 3768.050 3705.175 ;
        RECT 3769.470 3663.970 3818.050 3705.175 ;
        RECT 3819.470 3663.970 3868.050 3705.175 ;
        RECT 3869.470 3663.970 3918.050 3705.175 ;
        RECT 3919.470 3663.970 3968.050 3705.175 ;
        RECT 3969.470 3663.970 3976.630 3705.175 ;
        RECT 3519.470 3198.845 3976.630 3663.970 ;
        RECT 3519.470 3157.640 3568.050 3198.845 ;
        RECT 3569.470 3157.640 3618.050 3198.845 ;
        RECT 3619.470 3157.640 3668.050 3198.845 ;
        RECT 3669.470 3157.640 3718.050 3198.845 ;
        RECT 3719.470 3157.640 3768.050 3198.845 ;
        RECT 3769.470 3157.640 3818.050 3198.845 ;
        RECT 3819.470 3157.640 3868.050 3198.845 ;
        RECT 3869.470 3157.640 3918.050 3198.845 ;
        RECT 3919.470 3157.640 3968.050 3198.845 ;
        RECT 3969.470 3157.640 3976.630 3198.845 ;
        RECT 3519.470 2692.515 3976.630 3157.640 ;
        RECT 3519.470 2651.310 3568.050 2692.515 ;
        RECT 3569.470 2651.310 3618.050 2692.515 ;
        RECT 3619.470 2651.310 3668.050 2692.515 ;
        RECT 3669.470 2651.310 3718.050 2692.515 ;
        RECT 3719.470 2651.310 3768.050 2692.515 ;
        RECT 3769.470 2651.310 3818.050 2692.515 ;
        RECT 3819.470 2651.310 3868.050 2692.515 ;
        RECT 3869.470 2651.310 3918.050 2692.515 ;
        RECT 3919.470 2651.310 3968.050 2692.515 ;
        RECT 3969.470 2651.310 3976.630 2692.515 ;
        RECT 3519.470 2186.185 3976.630 2651.310 ;
        RECT 3519.470 2144.980 3568.050 2186.185 ;
        RECT 3569.470 2144.980 3618.050 2186.185 ;
        RECT 3619.470 2144.980 3668.050 2186.185 ;
        RECT 3669.470 2144.980 3718.050 2186.185 ;
        RECT 3719.470 2144.980 3768.050 2186.185 ;
        RECT 3769.470 2144.980 3818.050 2186.185 ;
        RECT 3819.470 2144.980 3868.050 2186.185 ;
        RECT 3869.470 2144.980 3918.050 2186.185 ;
        RECT 3919.470 2144.980 3968.050 2186.185 ;
        RECT 3969.470 2144.980 3976.630 2186.185 ;
        RECT 3519.470 1679.855 3976.630 2144.980 ;
        RECT 3519.470 1638.650 3568.050 1679.855 ;
        RECT 3569.470 1638.650 3618.050 1679.855 ;
        RECT 3619.470 1638.650 3668.050 1679.855 ;
        RECT 3669.470 1638.650 3718.050 1679.855 ;
        RECT 3719.470 1638.650 3768.050 1679.855 ;
        RECT 3769.470 1638.650 3818.050 1679.855 ;
        RECT 3819.470 1638.650 3868.050 1679.855 ;
        RECT 3869.470 1638.650 3918.050 1679.855 ;
        RECT 3919.470 1638.650 3968.050 1679.855 ;
        RECT 3969.470 1638.650 3976.630 1679.855 ;
        RECT 3519.470 1173.525 3976.630 1638.650 ;
        RECT 3519.470 1132.320 3568.050 1173.525 ;
        RECT 3569.470 1132.320 3618.050 1173.525 ;
        RECT 3619.470 1132.320 3668.050 1173.525 ;
        RECT 3669.470 1132.320 3718.050 1173.525 ;
        RECT 3719.470 1132.320 3768.050 1173.525 ;
        RECT 3769.470 1132.320 3818.050 1173.525 ;
        RECT 3819.470 1132.320 3868.050 1173.525 ;
        RECT 3869.470 1132.320 3918.050 1173.525 ;
        RECT 3919.470 1132.320 3968.050 1173.525 ;
        RECT 3969.470 1132.320 3976.630 1173.525 ;
        RECT 3519.470 667.195 3976.630 1132.320 ;
        RECT 3519.470 625.990 3568.050 667.195 ;
        RECT 3569.470 625.990 3618.050 667.195 ;
        RECT 3619.470 625.990 3668.050 667.195 ;
        RECT 3669.470 625.990 3718.050 667.195 ;
        RECT 3719.470 625.990 3768.050 667.195 ;
        RECT 3769.470 625.990 3818.050 667.195 ;
        RECT 3819.470 625.990 3868.050 667.195 ;
        RECT 3869.470 625.990 3918.050 667.195 ;
        RECT 3919.470 625.990 3968.050 667.195 ;
        RECT 3969.470 625.990 3976.630 667.195 ;
        RECT 3519.470 160.865 3976.630 625.990 ;
        RECT 3519.470 35.530 3565.050 160.865 ;
        RECT 3566.470 35.530 3568.050 160.865 ;
        RECT 3569.470 35.530 3615.050 160.865 ;
        RECT 3616.470 35.530 3618.050 160.865 ;
        RECT 3619.470 35.530 3665.050 160.865 ;
        RECT 3666.470 35.530 3668.050 160.865 ;
        RECT 3669.470 35.530 3715.050 160.865 ;
        RECT 3716.470 35.530 3718.050 160.865 ;
        RECT 3719.470 35.530 3765.050 160.865 ;
        RECT 3766.470 35.530 3768.050 160.865 ;
        RECT 3769.470 35.530 3815.050 160.865 ;
        RECT 3816.470 35.530 3818.050 160.865 ;
        RECT 3819.470 35.530 3865.050 160.865 ;
        RECT 3866.470 35.530 3868.050 160.865 ;
        RECT 3869.470 35.530 3915.050 160.865 ;
        RECT 3916.470 35.530 3918.050 160.865 ;
        RECT 3919.470 35.530 3965.050 160.865 ;
        RECT 3966.470 35.530 3968.050 160.865 ;
        RECT 3969.470 35.530 3976.630 160.865 ;
      LAYER TopMetal1 ;
        RECT 6.380 4038.370 3977.140 4069.980 ;
        RECT 6.380 4032.370 3977.140 4033.090 ;
        RECT 6.380 3992.340 3977.140 4027.090 ;
        RECT 6.380 3986.340 3977.140 3987.060 ;
        RECT 6.380 3946.310 3977.140 3981.060 ;
        RECT 6.380 3940.310 3977.140 3941.030 ;
        RECT 6.380 3900.280 3977.140 3935.030 ;
        RECT 6.380 3894.280 3977.140 3895.000 ;
        RECT 6.380 3854.250 3977.140 3889.000 ;
        RECT 6.380 3848.250 3977.140 3848.970 ;
        RECT 6.380 3808.220 3977.140 3842.970 ;
        RECT 6.380 3802.220 3977.140 3802.940 ;
        RECT 2881.480 3796.940 3012.760 3802.220 ;
        RECT 6.380 3762.190 3977.140 3796.940 ;
        RECT 2881.480 3756.910 3012.760 3762.190 ;
        RECT 6.380 3756.190 3977.140 3756.910 ;
        RECT 2881.480 3750.910 3012.760 3756.190 ;
        RECT 6.380 3716.160 3977.140 3750.910 ;
        RECT 2881.480 3710.880 3012.760 3716.160 ;
        RECT 6.380 3710.160 3977.140 3710.880 ;
        RECT 2881.480 3704.880 3012.760 3710.160 ;
        RECT 6.380 3670.130 3977.140 3704.880 ;
        RECT 2881.480 3664.850 3012.760 3670.130 ;
        RECT 6.380 3664.130 3977.140 3664.850 ;
        RECT 2881.480 3658.850 3012.760 3664.130 ;
        RECT 6.380 3624.100 3977.140 3658.850 ;
        RECT 2881.480 3618.820 3012.760 3624.100 ;
        RECT 6.380 3618.100 3977.140 3618.820 ;
        RECT 2881.480 3612.820 3012.760 3618.100 ;
        RECT 6.380 3578.070 3977.140 3612.820 ;
        RECT 2881.480 3572.790 3012.760 3578.070 ;
        RECT 6.380 3572.070 3977.140 3572.790 ;
        RECT 2881.480 3566.790 3012.760 3572.070 ;
        RECT 6.380 3532.040 3977.140 3566.790 ;
        RECT 2881.480 3526.760 3012.760 3532.040 ;
        RECT 6.380 3526.040 3977.140 3526.760 ;
        RECT 2881.480 3520.760 2952.760 3526.040 ;
        RECT 2971.480 3520.760 3012.760 3526.040 ;
        RECT 6.380 3486.010 3977.140 3520.760 ;
        RECT 6.380 3480.010 3977.140 3480.730 ;
        RECT 6.380 3439.980 3977.140 3474.730 ;
        RECT 6.380 3433.980 3977.140 3434.700 ;
        RECT 6.380 3393.950 3977.140 3428.700 ;
        RECT 6.380 3387.950 3977.140 3388.670 ;
        RECT 6.380 3347.920 3977.140 3382.670 ;
        RECT 6.380 3341.920 3977.140 3342.640 ;
        RECT 2881.480 3336.640 3012.760 3341.920 ;
        RECT 6.380 3301.890 3977.140 3336.640 ;
        RECT 2881.480 3296.610 3012.760 3301.890 ;
        RECT 6.380 3295.890 3977.140 3296.610 ;
        RECT 2881.480 3290.610 3012.760 3295.890 ;
        RECT 6.380 3255.860 3977.140 3290.610 ;
        RECT 2881.480 3250.580 3012.760 3255.860 ;
        RECT 6.380 3249.860 3977.140 3250.580 ;
        RECT 2881.480 3244.580 3012.760 3249.860 ;
        RECT 6.380 3209.830 3977.140 3244.580 ;
        RECT 2881.480 3204.550 3012.760 3209.830 ;
        RECT 6.380 3203.830 3977.140 3204.550 ;
        RECT 2881.480 3198.550 3012.760 3203.830 ;
        RECT 6.380 3163.800 3977.140 3198.550 ;
        RECT 2881.480 3158.520 3012.760 3163.800 ;
        RECT 6.380 3157.800 3977.140 3158.520 ;
        RECT 2881.480 3152.520 3012.760 3157.800 ;
        RECT 6.380 3117.770 3977.140 3152.520 ;
        RECT 2881.480 3112.490 3012.760 3117.770 ;
        RECT 6.380 3111.770 3977.140 3112.490 ;
        RECT 2881.480 3106.490 3012.760 3111.770 ;
        RECT 6.380 3071.740 3977.140 3106.490 ;
        RECT 2881.480 3066.460 3012.760 3071.740 ;
        RECT 6.380 3065.740 3977.140 3066.460 ;
        RECT 2881.480 3060.460 2952.760 3065.740 ;
        RECT 2971.480 3060.460 3012.760 3065.740 ;
        RECT 6.380 3025.710 3977.140 3060.460 ;
        RECT 6.380 3019.710 3977.140 3020.430 ;
        RECT 6.380 2979.680 3977.140 3014.430 ;
        RECT 6.380 2973.680 3977.140 2974.400 ;
        RECT 6.380 2933.650 3977.140 2968.400 ;
        RECT 6.380 2927.650 3977.140 2928.370 ;
        RECT 6.380 2887.620 3977.140 2922.370 ;
        RECT 6.380 2881.620 3977.140 2882.340 ;
        RECT 2881.480 2876.340 3012.760 2881.620 ;
        RECT 6.380 2841.590 3977.140 2876.340 ;
        RECT 2881.480 2836.310 3012.760 2841.590 ;
        RECT 6.380 2835.590 3977.140 2836.310 ;
        RECT 2881.480 2830.310 3012.760 2835.590 ;
        RECT 6.380 2795.560 3977.140 2830.310 ;
        RECT 2881.480 2790.280 3012.760 2795.560 ;
        RECT 6.380 2789.560 3977.140 2790.280 ;
        RECT 2881.480 2784.280 3012.760 2789.560 ;
        RECT 6.380 2749.530 3977.140 2784.280 ;
        RECT 2881.480 2744.250 3012.760 2749.530 ;
        RECT 6.380 2743.530 3977.140 2744.250 ;
        RECT 2881.480 2738.250 3012.760 2743.530 ;
        RECT 6.380 2703.500 3977.140 2738.250 ;
        RECT 2881.480 2698.220 3012.760 2703.500 ;
        RECT 6.380 2697.500 3977.140 2698.220 ;
        RECT 2881.480 2692.220 3012.760 2697.500 ;
        RECT 6.380 2657.470 3977.140 2692.220 ;
        RECT 2881.480 2652.190 3012.760 2657.470 ;
        RECT 6.380 2651.470 3977.140 2652.190 ;
        RECT 2881.480 2646.190 3012.760 2651.470 ;
        RECT 6.380 2611.440 3977.140 2646.190 ;
        RECT 2881.480 2606.160 3012.760 2611.440 ;
        RECT 6.380 2605.440 3977.140 2606.160 ;
        RECT 2881.480 2600.160 2952.760 2605.440 ;
        RECT 2971.480 2600.160 3012.760 2605.440 ;
        RECT 6.380 2565.410 3977.140 2600.160 ;
        RECT 6.380 2559.410 3977.140 2560.130 ;
        RECT 6.380 2519.380 3977.140 2554.130 ;
        RECT 6.380 2513.380 3977.140 2514.100 ;
        RECT 6.380 2473.350 3977.140 2508.100 ;
        RECT 6.380 2467.350 3977.140 2468.070 ;
        RECT 6.380 2427.320 3977.140 2462.070 ;
        RECT 6.380 2421.320 3977.140 2422.040 ;
        RECT 2881.480 2416.040 3012.760 2421.320 ;
        RECT 6.380 2381.290 3977.140 2416.040 ;
        RECT 2881.480 2376.010 3012.760 2381.290 ;
        RECT 6.380 2375.290 3977.140 2376.010 ;
        RECT 2881.480 2370.010 3012.760 2375.290 ;
        RECT 6.380 2335.260 3977.140 2370.010 ;
        RECT 2881.480 2329.980 3012.760 2335.260 ;
        RECT 6.380 2329.260 3977.140 2329.980 ;
        RECT 2881.480 2323.980 3012.760 2329.260 ;
        RECT 6.380 2289.230 3977.140 2323.980 ;
        RECT 2881.480 2283.950 3012.760 2289.230 ;
        RECT 6.380 2283.230 3977.140 2283.950 ;
        RECT 2881.480 2277.950 3012.760 2283.230 ;
        RECT 6.380 2243.200 3977.140 2277.950 ;
        RECT 2881.480 2237.920 3012.760 2243.200 ;
        RECT 6.380 2237.200 3977.140 2237.920 ;
        RECT 2881.480 2231.920 3012.760 2237.200 ;
        RECT 6.380 2197.170 3977.140 2231.920 ;
        RECT 2881.480 2191.890 3012.760 2197.170 ;
        RECT 6.380 2191.170 3977.140 2191.890 ;
        RECT 2881.480 2185.890 3012.760 2191.170 ;
        RECT 6.380 2151.140 3977.140 2185.890 ;
        RECT 2881.480 2145.860 3012.760 2151.140 ;
        RECT 6.380 2145.140 3977.140 2145.860 ;
        RECT 2881.480 2139.860 2952.760 2145.140 ;
        RECT 2971.480 2139.860 3012.760 2145.140 ;
        RECT 6.380 2105.110 3977.140 2139.860 ;
        RECT 6.380 2099.110 3977.140 2099.830 ;
        RECT 6.380 2059.080 3977.140 2093.830 ;
        RECT 6.380 2053.080 3977.140 2053.800 ;
        RECT 6.380 2013.050 3977.140 2047.800 ;
        RECT 6.380 2007.050 3977.140 2007.770 ;
        RECT 6.380 1967.020 3977.140 2001.770 ;
        RECT 6.380 1961.020 3977.140 1961.740 ;
        RECT 2881.480 1955.740 3012.760 1961.020 ;
        RECT 6.380 1920.990 3977.140 1955.740 ;
        RECT 2881.480 1915.710 3012.760 1920.990 ;
        RECT 6.380 1914.990 3977.140 1915.710 ;
        RECT 2881.480 1909.710 3012.760 1914.990 ;
        RECT 6.380 1874.960 3977.140 1909.710 ;
        RECT 2881.480 1869.680 3012.760 1874.960 ;
        RECT 6.380 1868.960 3977.140 1869.680 ;
        RECT 2881.480 1863.680 3012.760 1868.960 ;
        RECT 6.380 1828.930 3977.140 1863.680 ;
        RECT 2881.480 1823.650 3012.760 1828.930 ;
        RECT 6.380 1822.930 3977.140 1823.650 ;
        RECT 2881.480 1817.650 3012.760 1822.930 ;
        RECT 6.380 1782.900 3977.140 1817.650 ;
        RECT 2881.480 1777.620 3012.760 1782.900 ;
        RECT 6.380 1776.900 3977.140 1777.620 ;
        RECT 2881.480 1771.620 3012.760 1776.900 ;
        RECT 6.380 1736.870 3977.140 1771.620 ;
        RECT 2881.480 1731.590 3012.760 1736.870 ;
        RECT 6.380 1730.870 3977.140 1731.590 ;
        RECT 2881.480 1725.590 3012.760 1730.870 ;
        RECT 6.380 1690.840 3977.140 1725.590 ;
        RECT 2881.480 1685.560 3012.760 1690.840 ;
        RECT 6.380 1684.840 3977.140 1685.560 ;
        RECT 2881.480 1679.560 2952.760 1684.840 ;
        RECT 2971.480 1679.560 3012.760 1684.840 ;
        RECT 6.380 1644.810 3977.140 1679.560 ;
        RECT 6.380 1638.810 3977.140 1639.530 ;
        RECT 6.380 1598.780 3977.140 1633.530 ;
        RECT 6.380 1592.780 3977.140 1593.500 ;
        RECT 6.380 1552.750 3977.140 1587.500 ;
        RECT 6.380 1546.750 3977.140 1547.470 ;
        RECT 6.380 1506.720 3977.140 1541.470 ;
        RECT 6.380 1500.720 3977.140 1501.440 ;
        RECT 2881.480 1495.440 3012.760 1500.720 ;
        RECT 6.380 1460.690 3977.140 1495.440 ;
        RECT 2881.480 1455.410 3012.760 1460.690 ;
        RECT 6.380 1454.690 3977.140 1455.410 ;
        RECT 2881.480 1449.410 3012.760 1454.690 ;
        RECT 6.380 1414.660 3977.140 1449.410 ;
        RECT 2881.480 1409.380 3012.760 1414.660 ;
        RECT 6.380 1408.660 3977.140 1409.380 ;
        RECT 2881.480 1403.380 3012.760 1408.660 ;
        RECT 6.380 1368.630 3977.140 1403.380 ;
        RECT 2881.480 1363.350 3012.760 1368.630 ;
        RECT 6.380 1362.630 3977.140 1363.350 ;
        RECT 2881.480 1357.350 3012.760 1362.630 ;
        RECT 6.380 1322.600 3977.140 1357.350 ;
        RECT 2881.480 1317.320 3012.760 1322.600 ;
        RECT 6.380 1316.600 3977.140 1317.320 ;
        RECT 2881.480 1311.320 3012.760 1316.600 ;
        RECT 6.380 1276.570 3977.140 1311.320 ;
        RECT 2881.480 1271.290 3012.760 1276.570 ;
        RECT 6.380 1270.570 3977.140 1271.290 ;
        RECT 2881.480 1265.290 3012.760 1270.570 ;
        RECT 6.380 1230.540 3977.140 1265.290 ;
        RECT 2881.480 1225.260 3012.760 1230.540 ;
        RECT 6.380 1224.540 3977.140 1225.260 ;
        RECT 2881.480 1219.260 2952.760 1224.540 ;
        RECT 2971.480 1219.260 3012.760 1224.540 ;
        RECT 6.380 1184.510 3977.140 1219.260 ;
        RECT 6.380 1178.510 3977.140 1179.230 ;
        RECT 6.380 1138.480 3977.140 1173.230 ;
        RECT 6.380 1132.480 3977.140 1133.200 ;
        RECT 6.380 1092.450 3977.140 1127.200 ;
        RECT 6.380 1086.450 3977.140 1087.170 ;
        RECT 6.380 1046.420 3977.140 1081.170 ;
        RECT 6.380 1040.420 3977.140 1041.140 ;
        RECT 2881.480 1035.140 3012.760 1040.420 ;
        RECT 6.380 1000.390 3977.140 1035.140 ;
        RECT 2881.480 995.110 3012.760 1000.390 ;
        RECT 6.380 994.390 3977.140 995.110 ;
        RECT 2881.480 989.110 3012.760 994.390 ;
        RECT 6.380 954.360 3977.140 989.110 ;
        RECT 2881.480 949.080 3012.760 954.360 ;
        RECT 6.380 948.360 3977.140 949.080 ;
        RECT 2881.480 943.080 3012.760 948.360 ;
        RECT 6.380 908.330 3977.140 943.080 ;
        RECT 2881.480 903.050 3012.760 908.330 ;
        RECT 6.380 902.330 3977.140 903.050 ;
        RECT 2881.480 897.050 3012.760 902.330 ;
        RECT 6.380 862.300 3977.140 897.050 ;
        RECT 2881.480 857.020 3012.760 862.300 ;
        RECT 6.380 856.300 3977.140 857.020 ;
        RECT 2881.480 851.020 3012.760 856.300 ;
        RECT 6.380 816.270 3977.140 851.020 ;
        RECT 2881.480 810.990 3012.760 816.270 ;
        RECT 6.380 810.270 3977.140 810.990 ;
        RECT 2881.480 804.990 3012.760 810.270 ;
        RECT 6.380 770.240 3977.140 804.990 ;
        RECT 2881.480 764.960 3012.760 770.240 ;
        RECT 6.380 764.240 3977.140 764.960 ;
        RECT 2881.480 758.960 2952.760 764.240 ;
        RECT 2971.480 758.960 3012.760 764.240 ;
        RECT 6.380 724.210 3977.140 758.960 ;
        RECT 6.380 718.210 3977.140 718.930 ;
        RECT 6.380 678.180 3977.140 712.930 ;
        RECT 6.380 672.180 3977.140 672.900 ;
        RECT 6.380 632.150 3977.140 666.900 ;
        RECT 6.380 626.150 3977.140 626.870 ;
        RECT 6.380 586.120 3977.140 620.870 ;
        RECT 6.380 580.120 3977.140 580.840 ;
        RECT 2881.480 574.840 2952.760 580.120 ;
        RECT 2971.480 574.840 3012.760 580.120 ;
        RECT 6.380 540.090 3977.140 574.840 ;
        RECT 2881.480 534.810 3012.760 540.090 ;
        RECT 6.380 534.090 3977.140 534.810 ;
        RECT 2881.480 528.810 3012.760 534.090 ;
        RECT 6.380 494.060 3977.140 528.810 ;
        RECT 2881.480 488.780 3012.760 494.060 ;
        RECT 6.380 488.060 3977.140 488.780 ;
        RECT 2881.480 482.780 3012.760 488.060 ;
        RECT 6.380 448.030 3977.140 482.780 ;
        RECT 2881.480 442.750 3012.760 448.030 ;
        RECT 6.380 442.030 3977.140 442.750 ;
        RECT 2881.480 436.750 3012.760 442.030 ;
        RECT 6.380 402.000 3977.140 436.750 ;
        RECT 2881.480 396.720 3012.760 402.000 ;
        RECT 6.380 396.000 3977.140 396.720 ;
        RECT 2881.480 390.720 3012.760 396.000 ;
        RECT 6.380 355.970 3977.140 390.720 ;
        RECT 2881.480 350.690 3012.760 355.970 ;
        RECT 6.380 349.970 3977.140 350.690 ;
        RECT 2881.480 344.690 3012.760 349.970 ;
        RECT 6.380 309.940 3977.140 344.690 ;
        RECT 2881.480 304.660 3012.760 309.940 ;
        RECT 6.380 303.940 3977.140 304.660 ;
        RECT 2881.480 298.660 2952.760 303.940 ;
        RECT 2971.480 298.660 3012.760 303.940 ;
        RECT 6.380 263.910 3977.140 298.660 ;
        RECT 6.380 257.910 3977.140 258.630 ;
        RECT 6.380 217.880 3977.140 252.630 ;
        RECT 6.380 211.880 3977.140 212.600 ;
        RECT 6.380 171.850 3977.140 206.600 ;
        RECT 6.380 165.850 3977.140 166.570 ;
        RECT 6.380 125.820 3977.140 160.570 ;
        RECT 6.380 119.820 3977.140 120.540 ;
        RECT 6.380 79.790 3977.140 114.540 ;
        RECT 6.380 73.790 3977.140 74.510 ;
        RECT 6.380 35.020 3977.140 68.510 ;
  END
END efpga_subsystem_top
END LIBRARY

